VERSION 5.7 ;
  NOWIREEXTENSIONATPIN ON ;
  DIVIDERCHAR "/" ;
  BUSBITCHARS "[]" ;
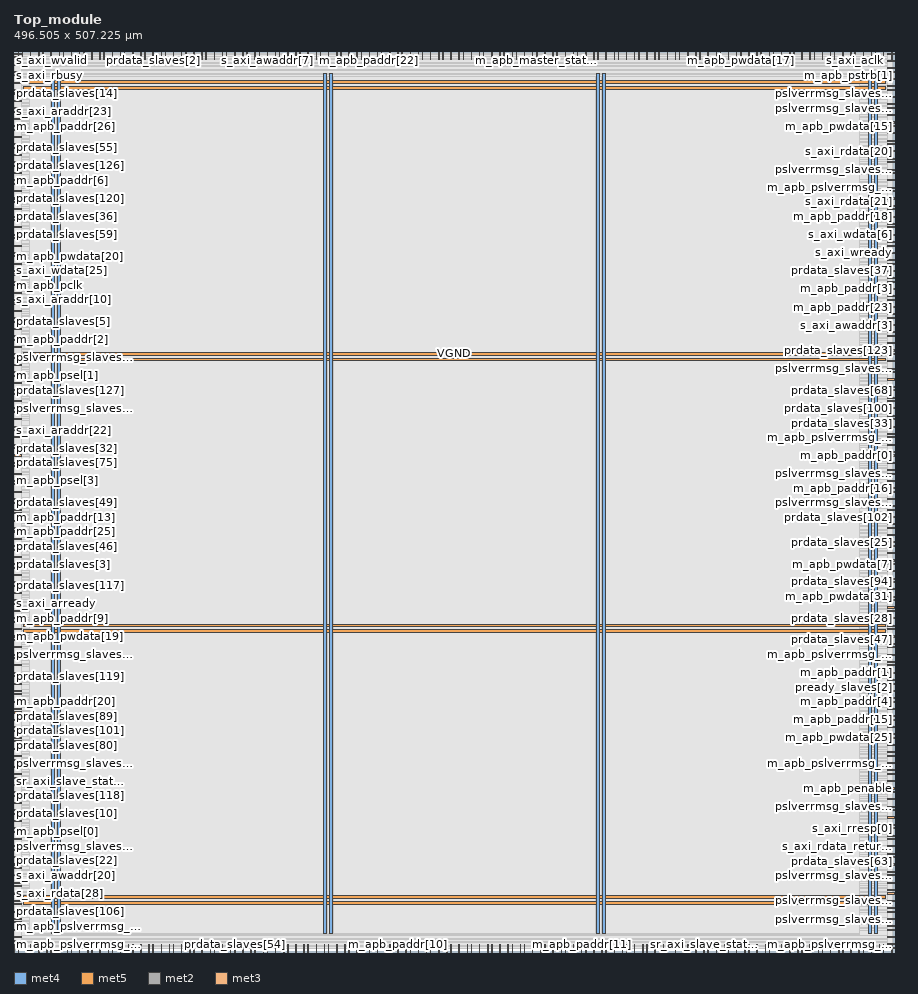
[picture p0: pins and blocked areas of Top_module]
MACRO Top_module
  CLASS BLOCK ;
  FOREIGN Top_module ;
  ORIGIN 0.000 0.000 ;
  SIZE 496.505 BY 507.225 ;
  PIN VGND
    DIRECTION INOUT ;
    USE GROUND ;
    PORT
      LAYER met4 ;
        RECT 24.340 10.640 25.940 495.280 ;
    END
    PORT
      LAYER met4 ;
        RECT 177.940 10.640 179.540 495.280 ;
    END
    PORT
      LAYER met4 ;
        RECT 331.540 10.640 333.140 495.280 ;
    END
    PORT
      LAYER met4 ;
        RECT 485.140 10.640 486.740 495.280 ;
    END
    PORT
      LAYER met5 ;
        RECT 5.280 30.030 491.060 31.630 ;
    END
    PORT
      LAYER met5 ;
        RECT 5.280 183.210 491.060 184.810 ;
    END
    PORT
      LAYER met5 ;
        RECT 5.280 336.390 491.060 337.990 ;
    END
    PORT
      LAYER met5 ;
        RECT 5.280 489.570 491.060 491.170 ;
    END
  END VGND
  PIN VPWR
    DIRECTION INOUT ;
    USE POWER ;
    PORT
      LAYER met4 ;
        RECT 21.040 10.640 22.640 495.280 ;
    END
    PORT
      LAYER met4 ;
        RECT 174.640 10.640 176.240 495.280 ;
    END
    PORT
      LAYER met4 ;
        RECT 328.240 10.640 329.840 495.280 ;
    END
    PORT
      LAYER met4 ;
        RECT 481.840 10.640 483.440 495.280 ;
    END
    PORT
      LAYER met5 ;
        RECT 5.280 26.730 491.060 28.330 ;
    END
    PORT
      LAYER met5 ;
        RECT 5.280 179.910 491.060 181.510 ;
    END
    PORT
      LAYER met5 ;
        RECT 5.280 333.090 491.060 334.690 ;
    END
    PORT
      LAYER met5 ;
        RECT 5.280 486.270 491.060 487.870 ;
    END
  END VPWR
  PIN apb_master_busy
    DIRECTION OUTPUT TRISTATE ;
    USE SIGNAL ;
    ANTENNADIFFAREA 0.795200 ;
    PORT
      LAYER met2 ;
        RECT 494.590 503.225 494.870 507.225 ;
    END
  END apb_master_busy
  PIN m_apb_master_state[0]
    DIRECTION OUTPUT TRISTATE ;
    USE SIGNAL ;
    ANTENNADIFFAREA 0.795200 ;
    PORT
      LAYER met2 ;
        RECT 494.590 0.000 494.870 4.000 ;
    END
  END m_apb_master_state[0]
  PIN m_apb_master_state[1]
    DIRECTION OUTPUT TRISTATE ;
    USE SIGNAL ;
    ANTENNADIFFAREA 0.795200 ;
    PORT
      LAYER met3 ;
        RECT 0.000 304.000 4.000 304.600 ;
    END
  END m_apb_master_state[1]
  PIN m_apb_master_state[2]
    DIRECTION OUTPUT TRISTATE ;
    USE SIGNAL ;
    ANTENNADIFFAREA 0.795200 ;
    PORT
      LAYER met2 ;
        RECT 294.490 503.225 294.770 507.225 ;
    END
  END m_apb_master_state[2]
  PIN m_apb_paddr[0]
    DIRECTION OUTPUT TRISTATE ;
    USE SIGNAL ;
    ANTENNADIFFAREA 0.445500 ;
    PORT
      LAYER met3 ;
        RECT 492.505 279.520 496.505 280.120 ;
    END
  END m_apb_paddr[0]
  PIN m_apb_paddr[10]
    DIRECTION OUTPUT TRISTATE ;
    USE SIGNAL ;
    ANTENNADIFFAREA 0.795200 ;
    PORT
      LAYER met2 ;
        RECT 216.290 0.000 216.570 4.000 ;
    END
  END m_apb_paddr[10]
  PIN m_apb_paddr[11]
    DIRECTION OUTPUT TRISTATE ;
    USE SIGNAL ;
    ANTENNADIFFAREA 0.795200 ;
    PORT
      LAYER met2 ;
        RECT 319.790 0.000 320.070 4.000 ;
    END
  END m_apb_paddr[11]
  PIN m_apb_paddr[12]
    DIRECTION OUTPUT TRISTATE ;
    USE SIGNAL ;
    ANTENNADIFFAREA 0.795200 ;
    PORT
      LAYER met3 ;
        RECT 492.505 75.520 496.505 76.120 ;
    END
  END m_apb_paddr[12]
  PIN m_apb_paddr[13]
    DIRECTION OUTPUT TRISTATE ;
    USE SIGNAL ;
    ANTENNADIFFAREA 0.795200 ;
    PORT
      LAYER met3 ;
        RECT 0.000 248.920 4.000 249.520 ;
    END
  END m_apb_paddr[13]
  PIN m_apb_paddr[14]
    DIRECTION OUTPUT TRISTATE ;
    USE SIGNAL ;
    ANTENNADIFFAREA 0.795200 ;
    PORT
      LAYER met3 ;
        RECT 0.000 126.520 4.000 127.120 ;
    END
  END m_apb_paddr[14]
  PIN m_apb_paddr[15]
    DIRECTION OUTPUT TRISTATE ;
    USE SIGNAL ;
    ANTENNADIFFAREA 0.795200 ;
    PORT
      LAYER met3 ;
        RECT 492.505 130.600 496.505 131.200 ;
    END
  END m_apb_paddr[15]
  PIN m_apb_paddr[16]
    DIRECTION OUTPUT TRISTATE ;
    USE SIGNAL ;
    ANTENNADIFFAREA 0.795200 ;
    PORT
      LAYER met3 ;
        RECT 492.505 261.160 496.505 261.760 ;
    END
  END m_apb_paddr[16]
  PIN m_apb_paddr[17]
    DIRECTION OUTPUT TRISTATE ;
    USE SIGNAL ;
    ANTENNADIFFAREA 0.795200 ;
    PORT
      LAYER met3 ;
        RECT 492.505 32.680 496.505 33.280 ;
    END
  END m_apb_paddr[17]
  PIN m_apb_paddr[18]
    DIRECTION OUTPUT TRISTATE ;
    USE SIGNAL ;
    ANTENNADIFFAREA 0.795200 ;
    PORT
      LAYER met3 ;
        RECT 492.505 414.160 496.505 414.760 ;
    END
  END m_apb_paddr[18]
  PIN m_apb_paddr[19]
    DIRECTION OUTPUT TRISTATE ;
    USE SIGNAL ;
    ANTENNADIFFAREA 0.795200 ;
    PORT
      LAYER met3 ;
        RECT 492.505 501.880 496.505 502.480 ;
    END
  END m_apb_paddr[19]
  PIN m_apb_paddr[1]
    DIRECTION OUTPUT TRISTATE ;
    USE SIGNAL ;
    ANTENNADIFFAREA 0.795200 ;
    PORT
      LAYER met3 ;
        RECT 492.505 157.120 496.505 157.720 ;
    END
  END m_apb_paddr[1]
  PIN m_apb_paddr[20]
    DIRECTION OUTPUT TRISTATE ;
    USE SIGNAL ;
    ANTENNADIFFAREA 0.795200 ;
    PORT
      LAYER met3 ;
        RECT 0.000 140.800 4.000 141.400 ;
    END
  END m_apb_paddr[20]
  PIN m_apb_paddr[21]
    DIRECTION OUTPUT TRISTATE ;
    USE SIGNAL ;
    ANTENNADIFFAREA 0.795200 ;
    PORT
      LAYER met2 ;
        RECT 211.690 0.000 211.970 4.000 ;
    END
  END m_apb_paddr[21]
  PIN m_apb_paddr[22]
    DIRECTION OUTPUT TRISTATE ;
    USE SIGNAL ;
    ANTENNADIFFAREA 0.795200 ;
    PORT
      LAYER met2 ;
        RECT 200.190 503.225 200.470 507.225 ;
    END
  END m_apb_paddr[22]
  PIN m_apb_paddr[23]
    DIRECTION OUTPUT TRISTATE ;
    USE SIGNAL ;
    ANTENNADIFFAREA 0.795200 ;
    PORT
      LAYER met3 ;
        RECT 492.505 363.160 496.505 363.760 ;
    END
  END m_apb_paddr[23]
  PIN m_apb_paddr[24]
    DIRECTION OUTPUT TRISTATE ;
    USE SIGNAL ;
    ANTENNADIFFAREA 0.795200 ;
    PORT
      LAYER met2 ;
        RECT 216.290 503.225 216.570 507.225 ;
    END
  END m_apb_paddr[24]
  PIN m_apb_paddr[25]
    DIRECTION OUTPUT TRISTATE ;
    USE SIGNAL ;
    ANTENNADIFFAREA 0.795200 ;
    PORT
      LAYER met3 ;
        RECT 0.000 236.680 4.000 237.280 ;
    END
  END m_apb_paddr[25]
  PIN m_apb_paddr[26]
    DIRECTION OUTPUT TRISTATE ;
    USE SIGNAL ;
    ANTENNADIFFAREA 0.795200 ;
    PORT
      LAYER met3 ;
        RECT 0.000 465.160 4.000 465.760 ;
    END
  END m_apb_paddr[26]
  PIN m_apb_paddr[27]
    DIRECTION OUTPUT TRISTATE ;
    USE SIGNAL ;
    ANTENNADIFFAREA 0.795200 ;
    PORT
      LAYER met2 ;
        RECT 361.190 503.225 361.470 507.225 ;
    END
  END m_apb_paddr[27]
  PIN m_apb_paddr[28]
    DIRECTION OUTPUT TRISTATE ;
    USE SIGNAL ;
    ANTENNADIFFAREA 0.795200 ;
    PORT
      LAYER met2 ;
        RECT 487.690 0.000 487.970 4.000 ;
    END
  END m_apb_paddr[28]
  PIN m_apb_paddr[29]
    DIRECTION OUTPUT TRISTATE ;
    USE SIGNAL ;
    ANTENNADIFFAREA 0.795200 ;
    PORT
      LAYER met2 ;
        RECT 349.690 503.225 349.970 507.225 ;
    END
  END m_apb_paddr[29]
  PIN m_apb_paddr[2]
    DIRECTION OUTPUT TRISTATE ;
    USE SIGNAL ;
    ANTENNADIFFAREA 0.795200 ;
    PORT
      LAYER met3 ;
        RECT 0.000 344.800 4.000 345.400 ;
    END
  END m_apb_paddr[2]
  PIN m_apb_paddr[30]
    DIRECTION OUTPUT TRISTATE ;
    USE SIGNAL ;
    ANTENNADIFFAREA 0.795200 ;
    PORT
      LAYER met3 ;
        RECT 492.505 34.720 496.505 35.320 ;
    END
  END m_apb_paddr[30]
  PIN m_apb_paddr[31]
    DIRECTION OUTPUT TRISTATE ;
    USE SIGNAL ;
    ANTENNADIFFAREA 0.795200 ;
    PORT
      LAYER met2 ;
        RECT 234.690 503.225 234.970 507.225 ;
    END
  END m_apb_paddr[31]
  PIN m_apb_paddr[3]
    DIRECTION OUTPUT TRISTATE ;
    USE SIGNAL ;
    ANTENNADIFFAREA 0.795200 ;
    PORT
      LAYER met3 ;
        RECT 492.505 373.360 496.505 373.960 ;
    END
  END m_apb_paddr[3]
  PIN m_apb_paddr[4]
    DIRECTION OUTPUT TRISTATE ;
    USE SIGNAL ;
    ANTENNADIFFAREA 0.445500 ;
    PORT
      LAYER met3 ;
        RECT 492.505 140.800 496.505 141.400 ;
    END
  END m_apb_paddr[4]
  PIN m_apb_paddr[5]
    DIRECTION OUTPUT TRISTATE ;
    USE SIGNAL ;
    ANTENNADIFFAREA 0.445500 ;
    PORT
      LAYER met3 ;
        RECT 492.505 197.920 496.505 198.520 ;
    END
  END m_apb_paddr[5]
  PIN m_apb_paddr[6]
    DIRECTION OUTPUT TRISTATE ;
    USE SIGNAL ;
    ANTENNADIFFAREA 0.795200 ;
    PORT
      LAYER met3 ;
        RECT 0.000 434.560 4.000 435.160 ;
    END
  END m_apb_paddr[6]
  PIN m_apb_paddr[7]
    DIRECTION OUTPUT TRISTATE ;
    USE SIGNAL ;
    ANTENNADIFFAREA 0.795200 ;
    PORT
      LAYER met3 ;
        RECT 0.000 263.200 4.000 263.800 ;
    END
  END m_apb_paddr[7]
  PIN m_apb_paddr[8]
    DIRECTION OUTPUT TRISTATE ;
    USE SIGNAL ;
    ANTENNADIFFAREA 0.445500 ;
    PORT
      LAYER met3 ;
        RECT 492.505 326.440 496.505 327.040 ;
    END
  END m_apb_paddr[8]
  PIN m_apb_paddr[9]
    DIRECTION OUTPUT TRISTATE ;
    USE SIGNAL ;
    ANTENNADIFFAREA 0.795200 ;
    PORT
      LAYER met3 ;
        RECT 0.000 187.720 4.000 188.320 ;
    END
  END m_apb_paddr[9]
  PIN m_apb_pclk
    DIRECTION INPUT ;
    USE SIGNAL ;
    ANTENNAGATEAREA 0.247500 ;
    PORT
      LAYER met3 ;
        RECT 0.000 375.400 4.000 376.000 ;
    END
  END m_apb_pclk
  PIN m_apb_penable
    DIRECTION OUTPUT TRISTATE ;
    USE SIGNAL ;
    ANTENNADIFFAREA 0.445500 ;
    PORT
      LAYER met3 ;
        RECT 492.505 91.840 496.505 92.440 ;
    END
  END m_apb_penable
  PIN m_apb_presetn
    DIRECTION INPUT ;
    USE SIGNAL ;
    ANTENNAGATEAREA 0.126000 ;
    PORT
      LAYER met2 ;
        RECT 142.690 0.000 142.970 4.000 ;
    END
  END m_apb_presetn
  PIN m_apb_psel[0]
    DIRECTION OUTPUT TRISTATE ;
    USE SIGNAL ;
    ANTENNADIFFAREA 0.795200 ;
    PORT
      LAYER met3 ;
        RECT 0.000 67.360 4.000 67.960 ;
    END
  END m_apb_psel[0]
  PIN m_apb_psel[1]
    DIRECTION OUTPUT TRISTATE ;
    USE SIGNAL ;
    ANTENNADIFFAREA 0.795200 ;
    PORT
      LAYER met3 ;
        RECT 0.000 320.320 4.000 320.920 ;
    END
  END m_apb_psel[1]
  PIN m_apb_psel[2]
    DIRECTION OUTPUT TRISTATE ;
    USE SIGNAL ;
    ANTENNADIFFAREA 0.795200 ;
    PORT
      LAYER met2 ;
        RECT 197.890 0.000 198.170 4.000 ;
    END
  END m_apb_psel[2]
  PIN m_apb_psel[3]
    DIRECTION OUTPUT TRISTATE ;
    USE SIGNAL ;
    ANTENNADIFFAREA 0.795200 ;
    PORT
      LAYER met3 ;
        RECT 0.000 265.240 4.000 265.840 ;
    END
  END m_apb_psel[3]
  PIN m_apb_pslverrmsg_mux[0]
    DIRECTION OUTPUT TRISTATE ;
    USE SIGNAL ;
    ANTENNADIFFAREA 0.795200 ;
    PORT
      LAYER met3 ;
        RECT 0.000 18.400 4.000 19.000 ;
    END
  END m_apb_pslverrmsg_mux[0]
  PIN m_apb_pslverrmsg_mux[10]
    DIRECTION OUTPUT TRISTATE ;
    USE SIGNAL ;
    PORT
      LAYER met2 ;
        RECT 170.290 503.225 170.570 507.225 ;
    END
  END m_apb_pslverrmsg_mux[10]
  PIN m_apb_pslverrmsg_mux[11]
    DIRECTION OUTPUT TRISTATE ;
    USE SIGNAL ;
    PORT
      LAYER met2 ;
        RECT 395.690 503.225 395.970 507.225 ;
    END
  END m_apb_pslverrmsg_mux[11]
  PIN m_apb_pslverrmsg_mux[12]
    DIRECTION OUTPUT TRISTATE ;
    USE SIGNAL ;
    PORT
      LAYER met3 ;
        RECT 492.505 163.240 496.505 163.840 ;
    END
  END m_apb_pslverrmsg_mux[12]
  PIN m_apb_pslverrmsg_mux[13]
    DIRECTION OUTPUT TRISTATE ;
    USE SIGNAL ;
    PORT
      LAYER met2 ;
        RECT 418.690 503.225 418.970 507.225 ;
    END
  END m_apb_pslverrmsg_mux[13]
  PIN m_apb_pslverrmsg_mux[14]
    DIRECTION OUTPUT TRISTATE ;
    USE SIGNAL ;
    PORT
      LAYER met2 ;
        RECT 117.390 503.225 117.670 507.225 ;
    END
  END m_apb_pslverrmsg_mux[14]
  PIN m_apb_pslverrmsg_mux[15]
    DIRECTION OUTPUT TRISTATE ;
    USE SIGNAL ;
    PORT
      LAYER met2 ;
        RECT 407.190 0.000 407.470 4.000 ;
    END
  END m_apb_pslverrmsg_mux[15]
  PIN m_apb_pslverrmsg_mux[16]
    DIRECTION OUTPUT TRISTATE ;
    USE SIGNAL ;
    PORT
      LAYER met3 ;
        RECT 492.505 289.720 496.505 290.320 ;
    END
  END m_apb_pslverrmsg_mux[16]
  PIN m_apb_pslverrmsg_mux[17]
    DIRECTION OUTPUT TRISTATE ;
    USE SIGNAL ;
    PORT
      LAYER met2 ;
        RECT 71.390 0.000 71.670 4.000 ;
    END
  END m_apb_pslverrmsg_mux[17]
  PIN m_apb_pslverrmsg_mux[18]
    DIRECTION OUTPUT TRISTATE ;
    USE SIGNAL ;
    PORT
      LAYER met2 ;
        RECT 27.690 503.225 27.970 507.225 ;
    END
  END m_apb_pslverrmsg_mux[18]
  PIN m_apb_pslverrmsg_mux[19]
    DIRECTION OUTPUT TRISTATE ;
    USE SIGNAL ;
    PORT
      LAYER met3 ;
        RECT 0.000 397.840 4.000 398.440 ;
    END
  END m_apb_pslverrmsg_mux[19]
  PIN m_apb_pslverrmsg_mux[1]
    DIRECTION OUTPUT TRISTATE ;
    USE SIGNAL ;
    PORT
      LAYER met3 ;
        RECT 492.505 403.960 496.505 404.560 ;
    END
  END m_apb_pslverrmsg_mux[1]
  PIN m_apb_pslverrmsg_mux[20]
    DIRECTION OUTPUT TRISTATE ;
    USE SIGNAL ;
    PORT
      LAYER met2 ;
        RECT 391.090 503.225 391.370 507.225 ;
    END
  END m_apb_pslverrmsg_mux[20]
  PIN m_apb_pslverrmsg_mux[21]
    DIRECTION OUTPUT TRISTATE ;
    USE SIGNAL ;
    PORT
      LAYER met3 ;
        RECT 492.505 281.560 496.505 282.160 ;
    END
  END m_apb_pslverrmsg_mux[21]
  PIN m_apb_pslverrmsg_mux[22]
    DIRECTION OUTPUT TRISTATE ;
    USE SIGNAL ;
    PORT
      LAYER met2 ;
        RECT 193.290 503.225 193.570 507.225 ;
    END
  END m_apb_pslverrmsg_mux[22]
  PIN m_apb_pslverrmsg_mux[23]
    DIRECTION OUTPUT TRISTATE ;
    USE SIGNAL ;
    PORT
      LAYER met3 ;
        RECT 492.505 106.120 496.505 106.720 ;
    END
  END m_apb_pslverrmsg_mux[23]
  PIN m_apb_pslverrmsg_mux[24]
    DIRECTION OUTPUT TRISTATE ;
    USE SIGNAL ;
    PORT
      LAYER met2 ;
        RECT 466.990 0.000 467.270 4.000 ;
    END
  END m_apb_pslverrmsg_mux[24]
  PIN m_apb_pslverrmsg_mux[25]
    DIRECTION OUTPUT TRISTATE ;
    USE SIGNAL ;
    PORT
      LAYER met2 ;
        RECT 64.490 0.000 64.770 4.000 ;
    END
  END m_apb_pslverrmsg_mux[25]
  PIN m_apb_pslverrmsg_mux[26]
    DIRECTION OUTPUT TRISTATE ;
    USE SIGNAL ;
    PORT
      LAYER met2 ;
        RECT 13.890 0.000 14.170 4.000 ;
    END
  END m_apb_pslverrmsg_mux[26]
  PIN m_apb_pslverrmsg_mux[27]
    DIRECTION OUTPUT TRISTATE ;
    USE SIGNAL ;
    PORT
      LAYER met2 ;
        RECT 200.190 0.000 200.470 4.000 ;
    END
  END m_apb_pslverrmsg_mux[27]
  PIN m_apb_pslverrmsg_mux[28]
    DIRECTION OUTPUT TRISTATE ;
    USE SIGNAL ;
    PORT
      LAYER met2 ;
        RECT 282.990 503.225 283.270 507.225 ;
    END
  END m_apb_pslverrmsg_mux[28]
  PIN m_apb_pslverrmsg_mux[29]
    DIRECTION OUTPUT TRISTATE ;
    USE SIGNAL ;
    PORT
      LAYER met3 ;
        RECT 492.505 430.480 496.505 431.080 ;
    END
  END m_apb_pslverrmsg_mux[29]
  PIN m_apb_pslverrmsg_mux[2]
    DIRECTION OUTPUT TRISTATE ;
    USE SIGNAL ;
    PORT
      LAYER met2 ;
        RECT 253.090 503.225 253.370 507.225 ;
    END
  END m_apb_pslverrmsg_mux[2]
  PIN m_apb_pslverrmsg_mux[30]
    DIRECTION OUTPUT TRISTATE ;
    USE SIGNAL ;
    PORT
      LAYER met2 ;
        RECT 149.590 503.225 149.870 507.225 ;
    END
  END m_apb_pslverrmsg_mux[30]
  PIN m_apb_pslverrmsg_mux[31]
    DIRECTION OUTPUT TRISTATE ;
    USE SIGNAL ;
    PORT
      LAYER met2 ;
        RECT 455.490 0.000 455.770 4.000 ;
    END
  END m_apb_pslverrmsg_mux[31]
  PIN m_apb_pslverrmsg_mux[3]
    DIRECTION OUTPUT TRISTATE ;
    USE SIGNAL ;
    PORT
      LAYER met3 ;
        RECT 492.505 367.240 496.505 367.840 ;
    END
  END m_apb_pslverrmsg_mux[3]
  PIN m_apb_pslverrmsg_mux[4]
    DIRECTION OUTPUT TRISTATE ;
    USE SIGNAL ;
    PORT
      LAYER met3 ;
        RECT 492.505 8.200 496.505 8.800 ;
    END
  END m_apb_pslverrmsg_mux[4]
  PIN m_apb_pslverrmsg_mux[5]
    DIRECTION OUTPUT TRISTATE ;
    USE SIGNAL ;
    PORT
      LAYER met3 ;
        RECT 492.505 387.640 496.505 388.240 ;
    END
  END m_apb_pslverrmsg_mux[5]
  PIN m_apb_pslverrmsg_mux[6]
    DIRECTION OUTPUT TRISTATE ;
    USE SIGNAL ;
    PORT
      LAYER met3 ;
        RECT 0.000 346.840 4.000 347.440 ;
    END
  END m_apb_pslverrmsg_mux[6]
  PIN m_apb_pslverrmsg_mux[7]
    DIRECTION OUTPUT TRISTATE ;
    USE SIGNAL ;
    PORT
      LAYER met2 ;
        RECT 273.790 503.225 274.070 507.225 ;
    END
  END m_apb_pslverrmsg_mux[7]
  PIN m_apb_pslverrmsg_mux[8]
    DIRECTION OUTPUT TRISTATE ;
    USE SIGNAL ;
    PORT
      LAYER met3 ;
        RECT 492.505 24.520 496.505 25.120 ;
    END
  END m_apb_pslverrmsg_mux[8]
  PIN m_apb_pslverrmsg_mux[9]
    DIRECTION OUTPUT TRISTATE ;
    USE SIGNAL ;
    PORT
      LAYER met2 ;
        RECT 105.890 503.225 106.170 507.225 ;
    END
  END m_apb_pslverrmsg_mux[9]
  PIN m_apb_pstrb[0]
    DIRECTION OUTPUT TRISTATE ;
    USE SIGNAL ;
    ANTENNADIFFAREA 0.795200 ;
    PORT
      LAYER met3 ;
        RECT 0.000 355.000 4.000 355.600 ;
    END
  END m_apb_pstrb[0]
  PIN m_apb_pstrb[1]
    DIRECTION OUTPUT TRISTATE ;
    USE SIGNAL ;
    ANTENNADIFFAREA 0.795200 ;
    PORT
      LAYER met3 ;
        RECT 492.505 497.800 496.505 498.400 ;
    END
  END m_apb_pstrb[1]
  PIN m_apb_pstrb[2]
    DIRECTION OUTPUT TRISTATE ;
    USE SIGNAL ;
    ANTENNADIFFAREA 0.795200 ;
    PORT
      LAYER met2 ;
        RECT 345.090 0.000 345.370 4.000 ;
    END
  END m_apb_pstrb[2]
  PIN m_apb_pstrb[3]
    DIRECTION OUTPUT TRISTATE ;
    USE SIGNAL ;
    ANTENNADIFFAREA 0.795200 ;
    PORT
      LAYER met2 ;
        RECT 285.290 0.000 285.570 4.000 ;
    END
  END m_apb_pstrb[3]
  PIN m_apb_pwdata[0]
    DIRECTION OUTPUT TRISTATE ;
    USE SIGNAL ;
    ANTENNADIFFAREA 0.445500 ;
    PORT
      LAYER met3 ;
        RECT 492.505 424.360 496.505 424.960 ;
    END
  END m_apb_pwdata[0]
  PIN m_apb_pwdata[10]
    DIRECTION OUTPUT TRISTATE ;
    USE SIGNAL ;
    ANTENNADIFFAREA 0.795200 ;
    PORT
      LAYER met2 ;
        RECT 287.590 0.000 287.870 4.000 ;
    END
  END m_apb_pwdata[10]
  PIN m_apb_pwdata[11]
    DIRECTION OUTPUT TRISTATE ;
    USE SIGNAL ;
    ANTENNADIFFAREA 0.795200 ;
    PORT
      LAYER met3 ;
        RECT 492.505 428.440 496.505 429.040 ;
    END
  END m_apb_pwdata[11]
  PIN m_apb_pwdata[12]
    DIRECTION OUTPUT TRISTATE ;
    USE SIGNAL ;
    ANTENNADIFFAREA 0.795200 ;
    PORT
      LAYER met2 ;
        RECT 119.690 503.225 119.970 507.225 ;
    END
  END m_apb_pwdata[12]
  PIN m_apb_pwdata[13]
    DIRECTION OUTPUT TRISTATE ;
    USE SIGNAL ;
    ANTENNADIFFAREA 0.795200 ;
    PORT
      LAYER met3 ;
        RECT 492.505 295.840 496.505 296.440 ;
    END
  END m_apb_pwdata[13]
  PIN m_apb_pwdata[14]
    DIRECTION OUTPUT TRISTATE ;
    USE SIGNAL ;
    ANTENNADIFFAREA 0.795200 ;
    PORT
      LAYER met3 ;
        RECT 0.000 495.760 4.000 496.360 ;
    END
  END m_apb_pwdata[14]
  PIN m_apb_pwdata[15]
    DIRECTION OUTPUT TRISTATE ;
    USE SIGNAL ;
    ANTENNADIFFAREA 0.445500 ;
    PORT
      LAYER met3 ;
        RECT 492.505 465.160 496.505 465.760 ;
    END
  END m_apb_pwdata[15]
  PIN m_apb_pwdata[16]
    DIRECTION OUTPUT TRISTATE ;
    USE SIGNAL ;
    ANTENNADIFFAREA 0.795200 ;
    PORT
      LAYER met3 ;
        RECT 492.505 310.120 496.505 310.720 ;
    END
  END m_apb_pwdata[16]
  PIN m_apb_pwdata[17]
    DIRECTION OUTPUT TRISTATE ;
    USE SIGNAL ;
    ANTENNADIFFAREA 0.795200 ;
    PORT
      LAYER met2 ;
        RECT 409.490 503.225 409.770 507.225 ;
    END
  END m_apb_pwdata[17]
  PIN m_apb_pwdata[18]
    DIRECTION OUTPUT TRISTATE ;
    USE SIGNAL ;
    ANTENNADIFFAREA 0.795200 ;
    PORT
      LAYER met3 ;
        RECT 0.000 146.920 4.000 147.520 ;
    END
  END m_apb_pwdata[18]
  PIN m_apb_pwdata[19]
    DIRECTION OUTPUT TRISTATE ;
    USE SIGNAL ;
    ANTENNADIFFAREA 0.795200 ;
    PORT
      LAYER met3 ;
        RECT 0.000 177.520 4.000 178.120 ;
    END
  END m_apb_pwdata[19]
  PIN m_apb_pwdata[1]
    DIRECTION OUTPUT TRISTATE ;
    USE SIGNAL ;
    ANTENNADIFFAREA 0.795200 ;
    PORT
      LAYER met3 ;
        RECT 0.000 12.280 4.000 12.880 ;
    END
  END m_apb_pwdata[1]
  PIN m_apb_pwdata[20]
    DIRECTION OUTPUT TRISTATE ;
    USE SIGNAL ;
    ANTENNADIFFAREA 0.795200 ;
    PORT
      LAYER met3 ;
        RECT 0.000 391.720 4.000 392.320 ;
    END
  END m_apb_pwdata[20]
  PIN m_apb_pwdata[21]
    DIRECTION OUTPUT TRISTATE ;
    USE SIGNAL ;
    ANTENNADIFFAREA 0.795200 ;
    PORT
      LAYER met3 ;
        RECT 0.000 79.600 4.000 80.200 ;
    END
  END m_apb_pwdata[21]
  PIN m_apb_pwdata[22]
    DIRECTION OUTPUT TRISTATE ;
    USE SIGNAL ;
    ANTENNADIFFAREA 0.795200 ;
    PORT
      LAYER met3 ;
        RECT 0.000 326.440 4.000 327.040 ;
    END
  END m_apb_pwdata[22]
  PIN m_apb_pwdata[23]
    DIRECTION OUTPUT TRISTATE ;
    USE SIGNAL ;
    ANTENNADIFFAREA 0.795200 ;
    PORT
      LAYER met3 ;
        RECT 0.000 185.680 4.000 186.280 ;
    END
  END m_apb_pwdata[23]
  PIN m_apb_pwdata[24]
    DIRECTION OUTPUT TRISTATE ;
    USE SIGNAL ;
    ANTENNADIFFAREA 0.795200 ;
    PORT
      LAYER met3 ;
        RECT 492.505 454.960 496.505 455.560 ;
    END
  END m_apb_pwdata[24]
  PIN m_apb_pwdata[25]
    DIRECTION OUTPUT TRISTATE ;
    USE SIGNAL ;
    ANTENNADIFFAREA 0.795200 ;
    PORT
      LAYER met3 ;
        RECT 492.505 120.400 496.505 121.000 ;
    END
  END m_apb_pwdata[25]
  PIN m_apb_pwdata[26]
    DIRECTION OUTPUT TRISTATE ;
    USE SIGNAL ;
    ANTENNADIFFAREA 0.795200 ;
    PORT
      LAYER met2 ;
        RECT 462.390 503.225 462.670 507.225 ;
    END
  END m_apb_pwdata[26]
  PIN m_apb_pwdata[27]
    DIRECTION OUTPUT TRISTATE ;
    USE SIGNAL ;
    ANTENNADIFFAREA 0.795200 ;
    PORT
      LAYER met3 ;
        RECT 0.000 63.280 4.000 63.880 ;
    END
  END m_apb_pwdata[27]
  PIN m_apb_pwdata[28]
    DIRECTION OUTPUT TRISTATE ;
    USE SIGNAL ;
    ANTENNADIFFAREA 0.795200 ;
    PORT
      LAYER met2 ;
        RECT 437.090 503.225 437.370 507.225 ;
    END
  END m_apb_pwdata[28]
  PIN m_apb_pwdata[29]
    DIRECTION OUTPUT TRISTATE ;
    USE SIGNAL ;
    ANTENNADIFFAREA 0.795200 ;
    PORT
      LAYER met2 ;
        RECT 280.690 503.225 280.970 507.225 ;
    END
  END m_apb_pwdata[29]
  PIN m_apb_pwdata[2]
    DIRECTION OUTPUT TRISTATE ;
    USE SIGNAL ;
    ANTENNADIFFAREA 0.795200 ;
    PORT
      LAYER met2 ;
        RECT 489.990 503.225 490.270 507.225 ;
    END
  END m_apb_pwdata[2]
  PIN m_apb_pwdata[30]
    DIRECTION OUTPUT TRISTATE ;
    USE SIGNAL ;
    ANTENNADIFFAREA 0.795200 ;
    PORT
      LAYER met2 ;
        RECT 246.190 0.000 246.470 4.000 ;
    END
  END m_apb_pwdata[30]
  PIN m_apb_pwdata[31]
    DIRECTION OUTPUT TRISTATE ;
    USE SIGNAL ;
    ANTENNADIFFAREA 0.795200 ;
    PORT
      LAYER met3 ;
        RECT 492.505 199.960 496.505 200.560 ;
    END
  END m_apb_pwdata[31]
  PIN m_apb_pwdata[3]
    DIRECTION OUTPUT TRISTATE ;
    USE SIGNAL ;
    ANTENNADIFFAREA 0.795200 ;
    PORT
      LAYER met2 ;
        RECT 402.590 503.225 402.870 507.225 ;
    END
  END m_apb_pwdata[3]
  PIN m_apb_pwdata[4]
    DIRECTION OUTPUT TRISTATE ;
    USE SIGNAL ;
    ANTENNADIFFAREA 0.795200 ;
    PORT
      LAYER met2 ;
        RECT 193.290 0.000 193.570 4.000 ;
    END
  END m_apb_pwdata[4]
  PIN m_apb_pwdata[5]
    DIRECTION OUTPUT TRISTATE ;
    USE SIGNAL ;
    ANTENNADIFFAREA 0.795200 ;
    PORT
      LAYER met2 ;
        RECT 432.490 0.000 432.770 4.000 ;
    END
  END m_apb_pwdata[5]
  PIN m_apb_pwdata[6]
    DIRECTION OUTPUT TRISTATE ;
    USE SIGNAL ;
    ANTENNADIFFAREA 0.795200 ;
    PORT
      LAYER met2 ;
        RECT 400.290 0.000 400.570 4.000 ;
    END
  END m_apb_pwdata[6]
  PIN m_apb_pwdata[7]
    DIRECTION OUTPUT TRISTATE ;
    USE SIGNAL ;
    ANTENNADIFFAREA 0.445500 ;
    PORT
      LAYER met3 ;
        RECT 492.505 218.320 496.505 218.920 ;
    END
  END m_apb_pwdata[7]
  PIN m_apb_pwdata[8]
    DIRECTION OUTPUT TRISTATE ;
    USE SIGNAL ;
    ANTENNADIFFAREA 0.795200 ;
    PORT
      LAYER met2 ;
        RECT 443.990 0.000 444.270 4.000 ;
    END
  END m_apb_pwdata[8]
  PIN m_apb_pwdata[9]
    DIRECTION OUTPUT TRISTATE ;
    USE SIGNAL ;
    ANTENNADIFFAREA 0.795200 ;
    PORT
      LAYER met2 ;
        RECT 379.590 503.225 379.870 507.225 ;
    END
  END m_apb_pwdata[9]
  PIN m_apb_pwrite
    DIRECTION OUTPUT TRISTATE ;
    USE SIGNAL ;
    ANTENNADIFFAREA 0.795200 ;
    PORT
      LAYER met2 ;
        RECT 105.890 0.000 106.170 4.000 ;
    END
  END m_apb_pwrite
  PIN prdata_slaves[0]
    DIRECTION INPUT ;
    USE SIGNAL ;
    ANTENNAGATEAREA 0.213000 ;
    PORT
      LAYER met2 ;
        RECT 110.490 0.000 110.770 4.000 ;
    END
  END prdata_slaves[0]
  PIN prdata_slaves[100]
    DIRECTION INPUT ;
    USE SIGNAL ;
    ANTENNAGATEAREA 0.196500 ;
    PORT
      LAYER met3 ;
        RECT 492.505 306.040 496.505 306.640 ;
    END
  END prdata_slaves[100]
  PIN prdata_slaves[101]
    DIRECTION INPUT ;
    USE SIGNAL ;
    ANTENNAGATEAREA 0.159000 ;
    PORT
      LAYER met3 ;
        RECT 0.000 124.480 4.000 125.080 ;
    END
  END prdata_slaves[101]
  PIN prdata_slaves[102]
    DIRECTION INPUT ;
    USE SIGNAL ;
    ANTENNAGATEAREA 0.213000 ;
    PORT
      LAYER met3 ;
        RECT 492.505 244.840 496.505 245.440 ;
    END
  END prdata_slaves[102]
  PIN prdata_slaves[103]
    DIRECTION INPUT ;
    USE SIGNAL ;
    ANTENNAGATEAREA 0.159000 ;
    PORT
      LAYER met2 ;
        RECT 36.890 0.000 37.170 4.000 ;
    END
  END prdata_slaves[103]
  PIN prdata_slaves[104]
    DIRECTION INPUT ;
    USE SIGNAL ;
    ANTENNAGATEAREA 0.159000 ;
    PORT
      LAYER met2 ;
        RECT 489.990 0.000 490.270 4.000 ;
    END
  END prdata_slaves[104]
  PIN prdata_slaves[105]
    DIRECTION INPUT ;
    USE SIGNAL ;
    ANTENNAGATEAREA 0.196500 ;
    PORT
      LAYER met3 ;
        RECT 492.505 318.280 496.505 318.880 ;
    END
  END prdata_slaves[105]
  PIN prdata_slaves[106]
    DIRECTION INPUT ;
    USE SIGNAL ;
    ANTENNAGATEAREA 0.159000 ;
    PORT
      LAYER met3 ;
        RECT 0.000 22.480 4.000 23.080 ;
    END
  END prdata_slaves[106]
  PIN prdata_slaves[107]
    DIRECTION INPUT ;
    USE SIGNAL ;
    ANTENNAGATEAREA 0.213000 ;
    PORT
      LAYER met2 ;
        RECT 439.390 503.225 439.670 507.225 ;
    END
  END prdata_slaves[107]
  PIN prdata_slaves[108]
    DIRECTION INPUT ;
    USE SIGNAL ;
    ANTENNAGATEAREA 0.213000 ;
    PORT
      LAYER met2 ;
        RECT 230.090 503.225 230.370 507.225 ;
    END
  END prdata_slaves[108]
  PIN prdata_slaves[109]
    DIRECTION INPUT ;
    USE SIGNAL ;
    ANTENNAGATEAREA 0.196500 ;
    PORT
      LAYER met2 ;
        RECT 340.490 503.225 340.770 507.225 ;
    END
  END prdata_slaves[109]
  PIN prdata_slaves[10]
    DIRECTION INPUT ;
    USE SIGNAL ;
    ANTENNAGATEAREA 0.213000 ;
    PORT
      LAYER met3 ;
        RECT 0.000 77.560 4.000 78.160 ;
    END
  END prdata_slaves[10]
  PIN prdata_slaves[110]
    DIRECTION INPUT ;
    USE SIGNAL ;
    ANTENNAGATEAREA 0.247500 ;
    PORT
      LAYER met2 ;
        RECT 308.290 0.000 308.570 4.000 ;
    END
  END prdata_slaves[110]
  PIN prdata_slaves[111]
    DIRECTION INPUT ;
    USE SIGNAL ;
    ANTENNAGATEAREA 0.159000 ;
    PORT
      LAYER met2 ;
        RECT 32.290 503.225 32.570 507.225 ;
    END
  END prdata_slaves[111]
  PIN prdata_slaves[112]
    DIRECTION INPUT ;
    USE SIGNAL ;
    ANTENNAGATEAREA 0.159000 ;
    PORT
      LAYER met2 ;
        RECT 384.190 503.225 384.470 507.225 ;
    END
  END prdata_slaves[112]
  PIN prdata_slaves[113]
    DIRECTION INPUT ;
    USE SIGNAL ;
    ANTENNAGATEAREA 0.213000 ;
    PORT
      LAYER met2 ;
        RECT 2.390 503.225 2.670 507.225 ;
    END
  END prdata_slaves[113]
  PIN prdata_slaves[114]
    DIRECTION INPUT ;
    USE SIGNAL ;
    ANTENNAGATEAREA 0.213000 ;
    PORT
      LAYER met2 ;
        RECT 287.590 503.225 287.870 507.225 ;
    END
  END prdata_slaves[114]
  PIN prdata_slaves[115]
    DIRECTION INPUT ;
    USE SIGNAL ;
    ANTENNAGATEAREA 0.159000 ;
    PORT
      LAYER met2 ;
        RECT 243.890 0.000 244.170 4.000 ;
    END
  END prdata_slaves[115]
  PIN prdata_slaves[116]
    DIRECTION INPUT ;
    USE SIGNAL ;
    ANTENNAGATEAREA 0.159000 ;
    PORT
      LAYER met3 ;
        RECT 0.000 463.120 4.000 463.720 ;
    END
  END prdata_slaves[116]
  PIN prdata_slaves[117]
    DIRECTION INPUT ;
    USE SIGNAL ;
    ANTENNAGATEAREA 0.159000 ;
    PORT
      LAYER met3 ;
        RECT 0.000 206.080 4.000 206.680 ;
    END
  END prdata_slaves[117]
  PIN prdata_slaves[118]
    DIRECTION INPUT ;
    USE SIGNAL ;
    ANTENNAGATEAREA 0.213000 ;
    PORT
      LAYER met3 ;
        RECT 0.000 87.760 4.000 88.360 ;
    END
  END prdata_slaves[118]
  PIN prdata_slaves[119]
    DIRECTION INPUT ;
    USE SIGNAL ;
    ANTENNAGATEAREA 0.126000 ;
    PORT
      LAYER met3 ;
        RECT 0.000 155.080 4.000 155.680 ;
    END
  END prdata_slaves[119]
  PIN prdata_slaves[11]
    DIRECTION INPUT ;
    USE SIGNAL ;
    ANTENNAGATEAREA 0.196500 ;
    PORT
      LAYER met2 ;
        RECT 16.190 503.225 16.470 507.225 ;
    END
  END prdata_slaves[11]
  PIN prdata_slaves[120]
    DIRECTION INPUT ;
    USE SIGNAL ;
    ANTENNAGATEAREA 0.126000 ;
    PORT
      LAYER met3 ;
        RECT 0.000 424.360 4.000 424.960 ;
    END
  END prdata_slaves[120]
  PIN prdata_slaves[121]
    DIRECTION INPUT ;
    USE SIGNAL ;
    ANTENNAGATEAREA 0.159000 ;
    PORT
      LAYER met2 ;
        RECT 338.190 0.000 338.470 4.000 ;
    END
  END prdata_slaves[121]
  PIN prdata_slaves[122]
    DIRECTION INPUT ;
    USE SIGNAL ;
    ANTENNAGATEAREA 0.196500 ;
    PORT
      LAYER met2 ;
        RECT 322.090 503.225 322.370 507.225 ;
    END
  END prdata_slaves[122]
  PIN prdata_slaves[123]
    DIRECTION INPUT ;
    USE SIGNAL ;
    ANTENNAGATEAREA 0.213000 ;
    PORT
      LAYER met3 ;
        RECT 492.505 338.680 496.505 339.280 ;
    END
  END prdata_slaves[123]
  PIN prdata_slaves[124]
    DIRECTION INPUT ;
    USE SIGNAL ;
    ANTENNAGATEAREA 0.213000 ;
    PORT
      LAYER met2 ;
        RECT 255.390 0.000 255.670 4.000 ;
    END
  END prdata_slaves[124]
  PIN prdata_slaves[125]
    DIRECTION INPUT ;
    USE SIGNAL ;
    ANTENNAGATEAREA 0.159000 ;
    PORT
      LAYER met3 ;
        RECT 492.505 477.400 496.505 478.000 ;
    END
  END prdata_slaves[125]
  PIN prdata_slaves[126]
    DIRECTION INPUT ;
    USE SIGNAL ;
    ANTENNAGATEAREA 0.159000 ;
    PORT
      LAYER met3 ;
        RECT 0.000 442.720 4.000 443.320 ;
    END
  END prdata_slaves[126]
  PIN prdata_slaves[127]
    DIRECTION INPUT ;
    USE SIGNAL ;
    ANTENNAGATEAREA 0.213000 ;
    PORT
      LAYER met3 ;
        RECT 0.000 316.240 4.000 316.840 ;
    END
  END prdata_slaves[127]
  PIN prdata_slaves[12]
    DIRECTION INPUT ;
    USE SIGNAL ;
    ANTENNAGATEAREA 0.159000 ;
    PORT
      LAYER met3 ;
        RECT 0.000 134.680 4.000 135.280 ;
    END
  END prdata_slaves[12]
  PIN prdata_slaves[13]
    DIRECTION INPUT ;
    USE SIGNAL ;
    ANTENNAGATEAREA 0.196500 ;
    PORT
      LAYER met2 ;
        RECT 386.490 503.225 386.770 507.225 ;
    END
  END prdata_slaves[13]
  PIN prdata_slaves[14]
    DIRECTION INPUT ;
    USE SIGNAL ;
    ANTENNAGATEAREA 0.196500 ;
    PORT
      LAYER met3 ;
        RECT 0.000 479.440 4.000 480.040 ;
    END
  END prdata_slaves[14]
  PIN prdata_slaves[15]
    DIRECTION INPUT ;
    USE SIGNAL ;
    ANTENNAGATEAREA 0.196500 ;
    PORT
      LAYER met2 ;
        RECT 241.590 503.225 241.870 507.225 ;
    END
  END prdata_slaves[15]
  PIN prdata_slaves[16]
    DIRECTION INPUT ;
    USE SIGNAL ;
    ANTENNAGATEAREA 0.196500 ;
    PORT
      LAYER met2 ;
        RECT 218.590 503.225 218.870 507.225 ;
    END
  END prdata_slaves[16]
  PIN prdata_slaves[17]
    DIRECTION INPUT ;
    USE SIGNAL ;
    ANTENNAGATEAREA 0.213000 ;
    PORT
      LAYER met2 ;
        RECT 55.290 0.000 55.570 4.000 ;
    END
  END prdata_slaves[17]
  PIN prdata_slaves[18]
    DIRECTION INPUT ;
    USE SIGNAL ;
    ANTENNAGATEAREA 0.159000 ;
    PORT
      LAYER met2 ;
        RECT 209.390 0.000 209.670 4.000 ;
    END
  END prdata_slaves[18]
  PIN prdata_slaves[19]
    DIRECTION INPUT ;
    USE SIGNAL ;
    ANTENNAGATEAREA 0.247500 ;
    PORT
      LAYER met2 ;
        RECT 2.390 0.000 2.670 4.000 ;
    END
  END prdata_slaves[19]
  PIN prdata_slaves[1]
    DIRECTION INPUT ;
    USE SIGNAL ;
    ANTENNAGATEAREA 0.196500 ;
    PORT
      LAYER met3 ;
        RECT 492.505 369.280 496.505 369.880 ;
    END
  END prdata_slaves[1]
  PIN prdata_slaves[20]
    DIRECTION INPUT ;
    USE SIGNAL ;
    ANTENNAGATEAREA 0.213000 ;
    PORT
      LAYER met2 ;
        RECT 349.690 0.000 349.970 4.000 ;
    END
  END prdata_slaves[20]
  PIN prdata_slaves[21]
    DIRECTION INPUT ;
    USE SIGNAL ;
    ANTENNAGATEAREA 0.213000 ;
    PORT
      LAYER met2 ;
        RECT 50.690 503.225 50.970 507.225 ;
    END
  END prdata_slaves[21]
  PIN prdata_slaves[22]
    DIRECTION INPUT ;
    USE SIGNAL ;
    ANTENNAGATEAREA 0.213000 ;
    PORT
      LAYER met3 ;
        RECT 0.000 46.960 4.000 47.560 ;
    END
  END prdata_slaves[22]
  PIN prdata_slaves[23]
    DIRECTION INPUT ;
    USE SIGNAL ;
    ANTENNAGATEAREA 0.159000 ;
    PORT
      LAYER met3 ;
        RECT 492.505 126.520 496.505 127.120 ;
    END
  END prdata_slaves[23]
  PIN prdata_slaves[24]
    DIRECTION INPUT ;
    USE SIGNAL ;
    ANTENNAGATEAREA 0.213000 ;
    PORT
      LAYER met2 ;
        RECT 62.190 503.225 62.470 507.225 ;
    END
  END prdata_slaves[24]
  PIN prdata_slaves[25]
    DIRECTION INPUT ;
    USE SIGNAL ;
    ANTENNAGATEAREA 0.213000 ;
    PORT
      LAYER met3 ;
        RECT 492.505 230.560 496.505 231.160 ;
    END
  END prdata_slaves[25]
  PIN prdata_slaves[26]
    DIRECTION INPUT ;
    USE SIGNAL ;
    ANTENNAGATEAREA 0.196500 ;
    PORT
      LAYER met2 ;
        RECT 397.990 503.225 398.270 507.225 ;
    END
  END prdata_slaves[26]
  PIN prdata_slaves[27]
    DIRECTION INPUT ;
    USE SIGNAL ;
    ANTENNAGATEAREA 0.213000 ;
    PORT
      LAYER met2 ;
        RECT 9.290 503.225 9.570 507.225 ;
    END
  END prdata_slaves[27]
  PIN prdata_slaves[28]
    DIRECTION INPUT ;
    USE SIGNAL ;
    ANTENNAGATEAREA 0.213000 ;
    PORT
      LAYER met3 ;
        RECT 492.505 187.720 496.505 188.320 ;
    END
  END prdata_slaves[28]
  PIN prdata_slaves[29]
    DIRECTION INPUT ;
    USE SIGNAL ;
    ANTENNAGATEAREA 0.196500 ;
    PORT
      LAYER met2 ;
        RECT 239.290 503.225 239.570 507.225 ;
    END
  END prdata_slaves[29]
  PIN prdata_slaves[2]
    DIRECTION INPUT ;
    USE SIGNAL ;
    ANTENNAGATEAREA 0.213000 ;
    PORT
      LAYER met2 ;
        RECT 78.290 503.225 78.570 507.225 ;
    END
  END prdata_slaves[2]
  PIN prdata_slaves[30]
    DIRECTION INPUT ;
    USE SIGNAL ;
    ANTENNAGATEAREA 0.213000 ;
    PORT
      LAYER met2 ;
        RECT 427.890 503.225 428.170 507.225 ;
    END
  END prdata_slaves[30]
  PIN prdata_slaves[31]
    DIRECTION INPUT ;
    USE SIGNAL ;
    ANTENNAGATEAREA 0.159000 ;
    PORT
      LAYER met2 ;
        RECT 112.790 503.225 113.070 507.225 ;
    END
  END prdata_slaves[31]
  PIN prdata_slaves[32]
    DIRECTION INPUT ;
    USE SIGNAL ;
    ANTENNAGATEAREA 0.213000 ;
    PORT
      LAYER met3 ;
        RECT 0.000 283.600 4.000 284.200 ;
    END
  END prdata_slaves[32]
  PIN prdata_slaves[33]
    DIRECTION INPUT ;
    USE SIGNAL ;
    ANTENNAGATEAREA 0.196500 ;
    PORT
      LAYER met3 ;
        RECT 492.505 301.960 496.505 302.560 ;
    END
  END prdata_slaves[33]
  PIN prdata_slaves[34]
    DIRECTION INPUT ;
    USE SIGNAL ;
    ANTENNAGATEAREA 0.159000 ;
    PORT
      LAYER met3 ;
        RECT 492.505 38.800 496.505 39.400 ;
    END
  END prdata_slaves[34]
  PIN prdata_slaves[35]
    DIRECTION INPUT ;
    USE SIGNAL ;
    ANTENNAGATEAREA 0.126000 ;
    PORT
      LAYER met2 ;
        RECT 71.390 503.225 71.670 507.225 ;
    END
  END prdata_slaves[35]
  PIN prdata_slaves[36]
    DIRECTION INPUT ;
    USE SIGNAL ;
    ANTENNAGATEAREA 0.213000 ;
    PORT
      LAYER met3 ;
        RECT 0.000 414.160 4.000 414.760 ;
    END
  END prdata_slaves[36]
  PIN prdata_slaves[37]
    DIRECTION INPUT ;
    USE SIGNAL ;
    ANTENNAGATEAREA 0.213000 ;
    PORT
      LAYER met3 ;
        RECT 492.505 379.480 496.505 380.080 ;
    END
  END prdata_slaves[37]
  PIN prdata_slaves[38]
    DIRECTION INPUT ;
    USE SIGNAL ;
    ANTENNAGATEAREA 0.159000 ;
    PORT
      LAYER met2 ;
        RECT 154.190 503.225 154.470 507.225 ;
    END
  END prdata_slaves[38]
  PIN prdata_slaves[39]
    DIRECTION INPUT ;
    USE SIGNAL ;
    ANTENNAGATEAREA 0.213000 ;
    PORT
      LAYER met3 ;
        RECT 492.505 383.560 496.505 384.160 ;
    END
  END prdata_slaves[39]
  PIN prdata_slaves[3]
    DIRECTION INPUT ;
    USE SIGNAL ;
    ANTENNAGATEAREA 0.213000 ;
    PORT
      LAYER met3 ;
        RECT 0.000 218.320 4.000 218.920 ;
    END
  END prdata_slaves[3]
  PIN prdata_slaves[40]
    DIRECTION INPUT ;
    USE SIGNAL ;
    ANTENNAGATEAREA 0.159000 ;
    PORT
      LAYER met2 ;
        RECT 418.690 0.000 418.970 4.000 ;
    END
  END prdata_slaves[40]
  PIN prdata_slaves[41]
    DIRECTION INPUT ;
    USE SIGNAL ;
    ANTENNAGATEAREA 0.196500 ;
    PORT
      LAYER met3 ;
        RECT 492.505 291.760 496.505 292.360 ;
    END
  END prdata_slaves[41]
  PIN prdata_slaves[42]
    DIRECTION INPUT ;
    USE SIGNAL ;
    ANTENNAGATEAREA 0.159000 ;
    PORT
      LAYER met2 ;
        RECT 181.790 503.225 182.070 507.225 ;
    END
  END prdata_slaves[42]
  PIN prdata_slaves[43]
    DIRECTION INPUT ;
    USE SIGNAL ;
    ANTENNAGATEAREA 0.213000 ;
    PORT
      LAYER met2 ;
        RECT 443.990 503.225 444.270 507.225 ;
    END
  END prdata_slaves[43]
  PIN prdata_slaves[44]
    DIRECTION INPUT ;
    USE SIGNAL ;
    ANTENNAGATEAREA 0.196500 ;
    PORT
      LAYER met2 ;
        RECT 147.290 503.225 147.570 507.225 ;
    END
  END prdata_slaves[44]
  PIN prdata_slaves[45]
    DIRECTION INPUT ;
    USE SIGNAL ;
    ANTENNAGATEAREA 0.159000 ;
    PORT
      LAYER met3 ;
        RECT 492.505 142.840 496.505 143.440 ;
    END
  END prdata_slaves[45]
  PIN prdata_slaves[46]
    DIRECTION INPUT ;
    USE SIGNAL ;
    ANTENNAGATEAREA 0.196500 ;
    PORT
      LAYER met3 ;
        RECT 0.000 232.600 4.000 233.200 ;
    END
  END prdata_slaves[46]
  PIN prdata_slaves[47]
    DIRECTION INPUT ;
    USE SIGNAL ;
    ANTENNAGATEAREA 0.213000 ;
    PORT
      LAYER met3 ;
        RECT 492.505 171.400 496.505 172.000 ;
    END
  END prdata_slaves[47]
  PIN prdata_slaves[48]
    DIRECTION INPUT ;
    USE SIGNAL ;
    ANTENNAGATEAREA 0.159000 ;
    PORT
      LAYER met2 ;
        RECT 165.690 0.000 165.970 4.000 ;
    END
  END prdata_slaves[48]
  PIN prdata_slaves[49]
    DIRECTION INPUT ;
    USE SIGNAL ;
    ANTENNAGATEAREA 0.196500 ;
    PORT
      LAYER met3 ;
        RECT 0.000 253.000 4.000 253.600 ;
    END
  END prdata_slaves[49]
  PIN prdata_slaves[4]
    DIRECTION INPUT ;
    USE SIGNAL ;
    ANTENNAGATEAREA 0.247500 ;
    PORT
      LAYER met3 ;
        RECT 0.000 104.080 4.000 104.680 ;
    END
  END prdata_slaves[4]
  PIN prdata_slaves[50]
    DIRECTION INPUT ;
    USE SIGNAL ;
    ANTENNAGATEAREA 0.196500 ;
    PORT
      LAYER met3 ;
        RECT 0.000 228.520 4.000 229.120 ;
    END
  END prdata_slaves[50]
  PIN prdata_slaves[51]
    DIRECTION INPUT ;
    USE SIGNAL ;
    ANTENNAGATEAREA 0.159000 ;
    PORT
      LAYER met2 ;
        RECT 483.090 503.225 483.370 507.225 ;
    END
  END prdata_slaves[51]
  PIN prdata_slaves[52]
    DIRECTION INPUT ;
    USE SIGNAL ;
    ANTENNAGATEAREA 0.159000 ;
    PORT
      LAYER met3 ;
        RECT 492.505 181.600 496.505 182.200 ;
    END
  END prdata_slaves[52]
  PIN prdata_slaves[53]
    DIRECTION INPUT ;
    USE SIGNAL ;
    ANTENNAGATEAREA 0.159000 ;
    PORT
      LAYER met2 ;
        RECT 414.090 503.225 414.370 507.225 ;
    END
  END prdata_slaves[53]
  PIN prdata_slaves[54]
    DIRECTION INPUT ;
    USE SIGNAL ;
    ANTENNAGATEAREA 0.196500 ;
    PORT
      LAYER met2 ;
        RECT 124.290 0.000 124.570 4.000 ;
    END
  END prdata_slaves[54]
  PIN prdata_slaves[55]
    DIRECTION INPUT ;
    USE SIGNAL ;
    ANTENNAGATEAREA 0.213000 ;
    PORT
      LAYER met3 ;
        RECT 0.000 452.920 4.000 453.520 ;
    END
  END prdata_slaves[55]
  PIN prdata_slaves[56]
    DIRECTION INPUT ;
    USE SIGNAL ;
    ANTENNAGATEAREA 0.159000 ;
    PORT
      LAYER met2 ;
        RECT 163.390 0.000 163.670 4.000 ;
    END
  END prdata_slaves[56]
  PIN prdata_slaves[57]
    DIRECTION INPUT ;
    USE SIGNAL ;
    ANTENNAGATEAREA 0.213000 ;
    PORT
      LAYER met3 ;
        RECT 0.000 503.920 4.000 504.520 ;
    END
  END prdata_slaves[57]
  PIN prdata_slaves[58]
    DIRECTION INPUT ;
    USE SIGNAL ;
    ANTENNAGATEAREA 0.126000 ;
    PORT
      LAYER met3 ;
        RECT 492.505 457.000 496.505 457.600 ;
    END
  END prdata_slaves[58]
  PIN prdata_slaves[59]
    DIRECTION INPUT ;
    USE SIGNAL ;
    ANTENNAGATEAREA 0.126000 ;
    PORT
      LAYER met3 ;
        RECT 0.000 408.040 4.000 408.640 ;
    END
  END prdata_slaves[59]
  PIN prdata_slaves[5]
    DIRECTION INPUT ;
    USE SIGNAL ;
    ANTENNAGATEAREA 0.196500 ;
    PORT
      LAYER met3 ;
        RECT 0.000 350.920 4.000 351.520 ;
    END
  END prdata_slaves[5]
  PIN prdata_slaves[60]
    DIRECTION INPUT ;
    USE SIGNAL ;
    ANTENNAGATEAREA 0.159000 ;
    PORT
      LAYER met3 ;
        RECT 0.000 53.080 4.000 53.680 ;
    END
  END prdata_slaves[60]
  PIN prdata_slaves[61]
    DIRECTION INPUT ;
    USE SIGNAL ;
    ANTENNAGATEAREA 0.213000 ;
    PORT
      LAYER met2 ;
        RECT 154.190 0.000 154.470 4.000 ;
    END
  END prdata_slaves[61]
  PIN prdata_slaves[62]
    DIRECTION INPUT ;
    USE SIGNAL ;
    ANTENNAGATEAREA 0.247500 ;
    PORT
      LAYER met2 ;
        RECT 82.890 0.000 83.170 4.000 ;
    END
  END prdata_slaves[62]
  PIN prdata_slaves[63]
    DIRECTION INPUT ;
    USE SIGNAL ;
    ANTENNAGATEAREA 0.213000 ;
    PORT
      LAYER met3 ;
        RECT 492.505 55.120 496.505 55.720 ;
    END
  END prdata_slaves[63]
  PIN prdata_slaves[64]
    DIRECTION INPUT ;
    USE SIGNAL ;
    ANTENNAGATEAREA 0.213000 ;
    PORT
      LAYER met2 ;
        RECT 257.690 0.000 257.970 4.000 ;
    END
  END prdata_slaves[64]
  PIN prdata_slaves[65]
    DIRECTION INPUT ;
    USE SIGNAL ;
    ANTENNAGATEAREA 0.159000 ;
    PORT
      LAYER met3 ;
        RECT 492.505 18.400 496.505 19.000 ;
    END
  END prdata_slaves[65]
  PIN prdata_slaves[66]
    DIRECTION INPUT ;
    USE SIGNAL ;
    ANTENNAGATEAREA 0.247500 ;
    PORT
      LAYER met2 ;
        RECT 101.290 0.000 101.570 4.000 ;
    END
  END prdata_slaves[66]
  PIN prdata_slaves[67]
    DIRECTION INPUT ;
    USE SIGNAL ;
    ANTENNAGATEAREA 0.213000 ;
    PORT
      LAYER met2 ;
        RECT 204.790 503.225 205.070 507.225 ;
    END
  END prdata_slaves[67]
  PIN prdata_slaves[68]
    DIRECTION INPUT ;
    USE SIGNAL ;
    ANTENNAGATEAREA 0.196500 ;
    PORT
      LAYER met3 ;
        RECT 492.505 312.160 496.505 312.760 ;
    END
  END prdata_slaves[68]
  PIN prdata_slaves[69]
    DIRECTION INPUT ;
    USE SIGNAL ;
    ANTENNAGATEAREA 0.196500 ;
    PORT
      LAYER met2 ;
        RECT 96.690 503.225 96.970 507.225 ;
    END
  END prdata_slaves[69]
  PIN prdata_slaves[6]
    DIRECTION INPUT ;
    USE SIGNAL ;
    ANTENNAGATEAREA 0.213000 ;
    PORT
      LAYER met2 ;
        RECT 303.690 0.000 303.970 4.000 ;
    END
  END prdata_slaves[6]
  PIN prdata_slaves[70]
    DIRECTION INPUT ;
    USE SIGNAL ;
    ANTENNAGATEAREA 0.126000 ;
    PORT
      LAYER met3 ;
        RECT 492.505 485.560 496.505 486.160 ;
    END
  END prdata_slaves[70]
  PIN prdata_slaves[71]
    DIRECTION INPUT ;
    USE SIGNAL ;
    ANTENNAGATEAREA 0.196500 ;
    PORT
      LAYER met3 ;
        RECT 0.000 401.920 4.000 402.520 ;
    END
  END prdata_slaves[71]
  PIN prdata_slaves[72]
    DIRECTION INPUT ;
    USE SIGNAL ;
    ANTENNAGATEAREA 0.126000 ;
    PORT
      LAYER met3 ;
        RECT 492.505 224.440 496.505 225.040 ;
    END
  END prdata_slaves[72]
  PIN prdata_slaves[73]
    DIRECTION INPUT ;
    USE SIGNAL ;
    ANTENNAGATEAREA 0.247500 ;
    PORT
      LAYER met2 ;
        RECT 135.790 0.000 136.070 4.000 ;
    END
  END prdata_slaves[73]
  PIN prdata_slaves[74]
    DIRECTION INPUT ;
    USE SIGNAL ;
    ANTENNAGATEAREA 0.196500 ;
    PORT
      LAYER met3 ;
        RECT 0.000 361.120 4.000 361.720 ;
    END
  END prdata_slaves[74]
  PIN prdata_slaves[75]
    DIRECTION INPUT ;
    USE SIGNAL ;
    ANTENNAGATEAREA 0.196500 ;
    PORT
      LAYER met3 ;
        RECT 0.000 275.440 4.000 276.040 ;
    END
  END prdata_slaves[75]
  PIN prdata_slaves[76]
    DIRECTION INPUT ;
    USE SIGNAL ;
    ANTENNAGATEAREA 0.213000 ;
    PORT
      LAYER met2 ;
        RECT 280.690 0.000 280.970 4.000 ;
    END
  END prdata_slaves[76]
  PIN prdata_slaves[77]
    DIRECTION INPUT ;
    USE SIGNAL ;
    ANTENNAGATEAREA 0.126000 ;
    PORT
      LAYER met3 ;
        RECT 492.505 299.920 496.505 300.520 ;
    END
  END prdata_slaves[77]
  PIN prdata_slaves[78]
    DIRECTION INPUT ;
    USE SIGNAL ;
    ANTENNAGATEAREA 0.159000 ;
    PORT
      LAYER met2 ;
        RECT 195.590 503.225 195.870 507.225 ;
    END
  END prdata_slaves[78]
  PIN prdata_slaves[79]
    DIRECTION INPUT ;
    USE SIGNAL ;
    ANTENNAGATEAREA 0.213000 ;
    PORT
      LAYER met2 ;
        RECT 423.290 0.000 423.570 4.000 ;
    END
  END prdata_slaves[79]
  PIN prdata_slaves[7]
    DIRECTION INPUT ;
    USE SIGNAL ;
    ANTENNAGATEAREA 0.196500 ;
    PORT
      LAYER met3 ;
        RECT 0.000 428.440 4.000 429.040 ;
    END
  END prdata_slaves[7]
  PIN prdata_slaves[80]
    DIRECTION INPUT ;
    USE SIGNAL ;
    ANTENNAGATEAREA 0.213000 ;
    PORT
      LAYER met3 ;
        RECT 0.000 120.400 4.000 121.000 ;
    END
  END prdata_slaves[80]
  PIN prdata_slaves[81]
    DIRECTION INPUT ;
    USE SIGNAL ;
    ANTENNAGATEAREA 0.159000 ;
    PORT
      LAYER met2 ;
        RECT 181.790 0.000 182.070 4.000 ;
    END
  END prdata_slaves[81]
  PIN prdata_slaves[82]
    DIRECTION INPUT ;
    USE SIGNAL ;
    ANTENNAGATEAREA 0.213000 ;
    PORT
      LAYER met3 ;
        RECT 0.000 26.560 4.000 27.160 ;
    END
  END prdata_slaves[82]
  PIN prdata_slaves[83]
    DIRECTION INPUT ;
    USE SIGNAL ;
    ANTENNAGATEAREA 0.159000 ;
    PORT
      LAYER met3 ;
        RECT 492.505 467.200 496.505 467.800 ;
    END
  END prdata_slaves[83]
  PIN prdata_slaves[84]
    DIRECTION INPUT ;
    USE SIGNAL ;
    ANTENNAGATEAREA 0.126000 ;
    PORT
      LAYER met3 ;
        RECT 0.000 238.720 4.000 239.320 ;
    END
  END prdata_slaves[84]
  PIN prdata_slaves[85]
    DIRECTION INPUT ;
    USE SIGNAL ;
    ANTENNAGATEAREA 0.159000 ;
    PORT
      LAYER met3 ;
        RECT 492.505 336.640 496.505 337.240 ;
    END
  END prdata_slaves[85]
  PIN prdata_slaves[86]
    DIRECTION INPUT ;
    USE SIGNAL ;
    ANTENNAGATEAREA 0.247500 ;
    PORT
      LAYER met3 ;
        RECT 492.505 505.960 496.505 506.560 ;
    END
  END prdata_slaves[86]
  PIN prdata_slaves[87]
    DIRECTION INPUT ;
    USE SIGNAL ;
    ANTENNAGATEAREA 0.213000 ;
    PORT
      LAYER met3 ;
        RECT 492.505 89.800 496.505 90.400 ;
    END
  END prdata_slaves[87]
  PIN prdata_slaves[88]
    DIRECTION INPUT ;
    USE SIGNAL ;
    ANTENNAGATEAREA 0.159000 ;
    PORT
      LAYER met2 ;
        RECT 158.790 0.000 159.070 4.000 ;
    END
  END prdata_slaves[88]
  PIN prdata_slaves[89]
    DIRECTION INPUT ;
    USE SIGNAL ;
    ANTENNAGATEAREA 0.159000 ;
    PORT
      LAYER met3 ;
        RECT 0.000 136.720 4.000 137.320 ;
    END
  END prdata_slaves[89]
  PIN prdata_slaves[8]
    DIRECTION INPUT ;
    USE SIGNAL ;
    ANTENNAGATEAREA 0.213000 ;
    PORT
      LAYER met2 ;
        RECT 39.190 503.225 39.470 507.225 ;
    END
  END prdata_slaves[8]
  PIN prdata_slaves[90]
    DIRECTION INPUT ;
    USE SIGNAL ;
    ANTENNAGATEAREA 0.196500 ;
    PORT
      LAYER met2 ;
        RECT 368.090 503.225 368.370 507.225 ;
    END
  END prdata_slaves[90]
  PIN prdata_slaves[91]
    DIRECTION INPUT ;
    USE SIGNAL ;
    ANTENNAGATEAREA 0.196500 ;
    PORT
      LAYER met2 ;
        RECT 161.090 503.225 161.370 507.225 ;
    END
  END prdata_slaves[91]
  PIN prdata_slaves[92]
    DIRECTION INPUT ;
    USE SIGNAL ;
    ANTENNAGATEAREA 0.159000 ;
    PORT
      LAYER met3 ;
        RECT 0.000 49.000 4.000 49.600 ;
    END
  END prdata_slaves[92]
  PIN prdata_slaves[93]
    DIRECTION INPUT ;
    USE SIGNAL ;
    ANTENNAGATEAREA 0.213000 ;
    PORT
      LAYER met2 ;
        RECT 78.290 0.000 78.570 4.000 ;
    END
  END prdata_slaves[93]
  PIN prdata_slaves[94]
    DIRECTION INPUT ;
    USE SIGNAL ;
    ANTENNAGATEAREA 0.159000 ;
    PORT
      LAYER met3 ;
        RECT 492.505 204.040 496.505 204.640 ;
    END
  END prdata_slaves[94]
  PIN prdata_slaves[95]
    DIRECTION INPUT ;
    USE SIGNAL ;
    ANTENNAGATEAREA 0.213000 ;
    PORT
      LAYER met2 ;
        RECT 420.990 503.225 421.270 507.225 ;
    END
  END prdata_slaves[95]
  PIN prdata_slaves[96]
    DIRECTION INPUT ;
    USE SIGNAL ;
    ANTENNAGATEAREA 0.213000 ;
    PORT
      LAYER met2 ;
        RECT 257.690 503.225 257.970 507.225 ;
    END
  END prdata_slaves[96]
  PIN prdata_slaves[97]
    DIRECTION INPUT ;
    USE SIGNAL ;
    ANTENNAGATEAREA 0.213000 ;
    PORT
      LAYER met3 ;
        RECT 0.000 269.320 4.000 269.920 ;
    END
  END prdata_slaves[97]
  PIN prdata_slaves[98]
    DIRECTION INPUT ;
    USE SIGNAL ;
    ANTENNAGATEAREA 0.196500 ;
    PORT
      LAYER met3 ;
        RECT 492.505 348.880 496.505 349.480 ;
    END
  END prdata_slaves[98]
  PIN prdata_slaves[99]
    DIRECTION INPUT ;
    USE SIGNAL ;
    ANTENNAGATEAREA 0.159000 ;
    PORT
      LAYER met3 ;
        RECT 0.000 151.000 4.000 151.600 ;
    END
  END prdata_slaves[99]
  PIN prdata_slaves[9]
    DIRECTION INPUT ;
    USE SIGNAL ;
    ANTENNAGATEAREA 0.159000 ;
    PORT
      LAYER met2 ;
        RECT 207.090 503.225 207.370 507.225 ;
    END
  END prdata_slaves[9]
  PIN pready_slaves[0]
    DIRECTION INPUT ;
    USE SIGNAL ;
    ANTENNAGATEAREA 0.213000 ;
    PORT
      LAYER met3 ;
        RECT 0.000 403.960 4.000 404.560 ;
    END
  END pready_slaves[0]
  PIN pready_slaves[1]
    DIRECTION INPUT ;
    USE SIGNAL ;
    ANTENNAGATEAREA 0.213000 ;
    PORT
      LAYER met3 ;
        RECT 0.000 181.600 4.000 182.200 ;
    END
  END pready_slaves[1]
  PIN pready_slaves[2]
    DIRECTION INPUT ;
    USE SIGNAL ;
    ANTENNAGATEAREA 0.159000 ;
    PORT
      LAYER met3 ;
        RECT 492.505 153.040 496.505 153.640 ;
    END
  END pready_slaves[2]
  PIN pready_slaves[3]
    DIRECTION INPUT ;
    USE SIGNAL ;
    ANTENNAGATEAREA 0.126000 ;
    PORT
      LAYER met2 ;
        RECT 223.190 0.000 223.470 4.000 ;
    END
  END pready_slaves[3]
  PIN pslverr_slaves[0]
    DIRECTION INPUT ;
    USE SIGNAL ;
    ANTENNAGATEAREA 0.159000 ;
    PORT
      LAYER met3 ;
        RECT 0.000 273.400 4.000 274.000 ;
    END
  END pslverr_slaves[0]
  PIN pslverr_slaves[1]
    DIRECTION INPUT ;
    USE SIGNAL ;
    ANTENNAGATEAREA 0.213000 ;
    PORT
      LAYER met3 ;
        RECT 492.505 461.080 496.505 461.680 ;
    END
  END pslverr_slaves[1]
  PIN pslverr_slaves[2]
    DIRECTION INPUT ;
    USE SIGNAL ;
    ANTENNAGATEAREA 0.159000 ;
    PORT
      LAYER met3 ;
        RECT 0.000 242.800 4.000 243.400 ;
    END
  END pslverr_slaves[2]
  PIN pslverr_slaves[3]
    DIRECTION INPUT ;
    USE SIGNAL ;
    ANTENNAGATEAREA 0.159000 ;
    PORT
      LAYER met3 ;
        RECT 0.000 393.760 4.000 394.360 ;
    END
  END pslverr_slaves[3]
  PIN pslverrmsg_slaves[0]
    DIRECTION INPUT ;
    USE SIGNAL ;
    ANTENNAGATEAREA 0.213000 ;
    PORT
      LAYER met3 ;
        RECT 492.505 122.440 496.505 123.040 ;
    END
  END pslverrmsg_slaves[0]
  PIN pslverrmsg_slaves[100]
    DIRECTION INPUT ;
    USE SIGNAL ;
    PORT
      LAYER met3 ;
        RECT 0.000 246.880 4.000 247.480 ;
    END
  END pslverrmsg_slaves[100]
  PIN pslverrmsg_slaves[101]
    DIRECTION INPUT ;
    USE SIGNAL ;
    PORT
      LAYER met3 ;
        RECT 0.000 448.840 4.000 449.440 ;
    END
  END pslverrmsg_slaves[101]
  PIN pslverrmsg_slaves[102]
    DIRECTION INPUT ;
    USE SIGNAL ;
    PORT
      LAYER met3 ;
        RECT 492.505 28.600 496.505 29.200 ;
    END
  END pslverrmsg_slaves[102]
  PIN pslverrmsg_slaves[103]
    DIRECTION INPUT ;
    USE SIGNAL ;
    PORT
      LAYER met3 ;
        RECT 492.505 399.880 496.505 400.480 ;
    END
  END pslverrmsg_slaves[103]
  PIN pslverrmsg_slaves[104]
    DIRECTION INPUT ;
    USE SIGNAL ;
    PORT
      LAYER met2 ;
        RECT 356.590 503.225 356.870 507.225 ;
    END
  END pslverrmsg_slaves[104]
  PIN pslverrmsg_slaves[105]
    DIRECTION INPUT ;
    USE SIGNAL ;
    PORT
      LAYER met2 ;
        RECT 471.590 0.000 471.870 4.000 ;
    END
  END pslverrmsg_slaves[105]
  PIN pslverrmsg_slaves[106]
    DIRECTION INPUT ;
    USE SIGNAL ;
    PORT
      LAYER met3 ;
        RECT 0.000 365.200 4.000 365.800 ;
    END
  END pslverrmsg_slaves[106]
  PIN pslverrmsg_slaves[107]
    DIRECTION INPUT ;
    USE SIGNAL ;
    PORT
      LAYER met2 ;
        RECT 59.890 503.225 60.170 507.225 ;
    END
  END pslverrmsg_slaves[107]
  PIN pslverrmsg_slaves[108]
    DIRECTION INPUT ;
    USE SIGNAL ;
    PORT
      LAYER met3 ;
        RECT 492.505 151.000 496.505 151.600 ;
    END
  END pslverrmsg_slaves[108]
  PIN pslverrmsg_slaves[109]
    DIRECTION INPUT ;
    USE SIGNAL ;
    PORT
      LAYER met2 ;
        RECT 234.690 0.000 234.970 4.000 ;
    END
  END pslverrmsg_slaves[109]
  PIN pslverrmsg_slaves[10]
    DIRECTION INPUT ;
    USE SIGNAL ;
    ANTENNAGATEAREA 0.213000 ;
    PORT
      LAYER met3 ;
        RECT 492.505 112.240 496.505 112.840 ;
    END
  END pslverrmsg_slaves[10]
  PIN pslverrmsg_slaves[110]
    DIRECTION INPUT ;
    USE SIGNAL ;
    PORT
      LAYER met3 ;
        RECT 0.000 279.520 4.000 280.120 ;
    END
  END pslverrmsg_slaves[110]
  PIN pslverrmsg_slaves[111]
    DIRECTION INPUT ;
    USE SIGNAL ;
    PORT
      LAYER met2 ;
        RECT 342.790 0.000 343.070 4.000 ;
    END
  END pslverrmsg_slaves[111]
  PIN pslverrmsg_slaves[112]
    DIRECTION INPUT ;
    USE SIGNAL ;
    PORT
      LAYER met2 ;
        RECT 188.690 503.225 188.970 507.225 ;
    END
  END pslverrmsg_slaves[112]
  PIN pslverrmsg_slaves[113]
    DIRECTION INPUT ;
    USE SIGNAL ;
    PORT
      LAYER met2 ;
        RECT 29.990 0.000 30.270 4.000 ;
    END
  END pslverrmsg_slaves[113]
  PIN pslverrmsg_slaves[114]
    DIRECTION INPUT ;
    USE SIGNAL ;
    PORT
      LAYER met2 ;
        RECT 48.390 0.000 48.670 4.000 ;
    END
  END pslverrmsg_slaves[114]
  PIN pslverrmsg_slaves[115]
    DIRECTION INPUT ;
    USE SIGNAL ;
    PORT
      LAYER met2 ;
        RECT 414.090 0.000 414.370 4.000 ;
    END
  END pslverrmsg_slaves[115]
  PIN pslverrmsg_slaves[116]
    DIRECTION INPUT ;
    USE SIGNAL ;
    PORT
      LAYER met3 ;
        RECT 492.505 12.280 496.505 12.880 ;
    END
  END pslverrmsg_slaves[116]
  PIN pslverrmsg_slaves[117]
    DIRECTION INPUT ;
    USE SIGNAL ;
    PORT
      LAYER met3 ;
        RECT 0.000 171.400 4.000 172.000 ;
    END
  END pslverrmsg_slaves[117]
  PIN pslverrmsg_slaves[118]
    DIRECTION INPUT ;
    USE SIGNAL ;
    PORT
      LAYER met3 ;
        RECT 492.505 110.200 496.505 110.800 ;
    END
  END pslverrmsg_slaves[118]
  PIN pslverrmsg_slaves[119]
    DIRECTION INPUT ;
    USE SIGNAL ;
    PORT
      LAYER met3 ;
        RECT 0.000 144.880 4.000 145.480 ;
    END
  END pslverrmsg_slaves[119]
  PIN pslverrmsg_slaves[11]
    DIRECTION INPUT ;
    USE SIGNAL ;
    ANTENNAGATEAREA 0.213000 ;
    PORT
      LAYER met2 ;
        RECT 177.190 503.225 177.470 507.225 ;
    END
  END pslverrmsg_slaves[11]
  PIN pslverrmsg_slaves[120]
    DIRECTION INPUT ;
    USE SIGNAL ;
    PORT
      LAYER met2 ;
        RECT 135.790 503.225 136.070 507.225 ;
    END
  END pslverrmsg_slaves[120]
  PIN pslverrmsg_slaves[121]
    DIRECTION INPUT ;
    USE SIGNAL ;
    PORT
      LAYER met3 ;
        RECT 0.000 59.200 4.000 59.800 ;
    END
  END pslverrmsg_slaves[121]
  PIN pslverrmsg_slaves[122]
    DIRECTION INPUT ;
    USE SIGNAL ;
    PORT
      LAYER met2 ;
        RECT 172.590 503.225 172.870 507.225 ;
    END
  END pslverrmsg_slaves[122]
  PIN pslverrmsg_slaves[123]
    DIRECTION INPUT ;
    USE SIGNAL ;
    PORT
      LAYER met3 ;
        RECT 0.000 499.840 4.000 500.440 ;
    END
  END pslverrmsg_slaves[123]
  PIN pslverrmsg_slaves[124]
    DIRECTION INPUT ;
    USE SIGNAL ;
    PORT
      LAYER met3 ;
        RECT 492.505 220.360 496.505 220.960 ;
    END
  END pslverrmsg_slaves[124]
  PIN pslverrmsg_slaves[125]
    DIRECTION INPUT ;
    USE SIGNAL ;
    PORT
      LAYER met3 ;
        RECT 492.505 22.480 496.505 23.080 ;
    END
  END pslverrmsg_slaves[125]
  PIN pslverrmsg_slaves[126]
    DIRECTION INPUT ;
    USE SIGNAL ;
    PORT
      LAYER met3 ;
        RECT 492.505 210.160 496.505 210.760 ;
    END
  END pslverrmsg_slaves[126]
  PIN pslverrmsg_slaves[127]
    DIRECTION INPUT ;
    USE SIGNAL ;
    PORT
      LAYER met2 ;
        RECT 250.790 503.225 251.070 507.225 ;
    END
  END pslverrmsg_slaves[127]
  PIN pslverrmsg_slaves[12]
    DIRECTION INPUT ;
    USE SIGNAL ;
    ANTENNAGATEAREA 0.213000 ;
    PORT
      LAYER met2 ;
        RECT 262.290 0.000 262.570 4.000 ;
    END
  END pslverrmsg_slaves[12]
  PIN pslverrmsg_slaves[13]
    DIRECTION INPUT ;
    USE SIGNAL ;
    ANTENNAGATEAREA 0.196500 ;
    PORT
      LAYER met2 ;
        RECT 292.190 503.225 292.470 507.225 ;
    END
  END pslverrmsg_slaves[13]
  PIN pslverrmsg_slaves[14]
    DIRECTION INPUT ;
    USE SIGNAL ;
    ANTENNAGATEAREA 0.213000 ;
    PORT
      LAYER met3 ;
        RECT 0.000 505.960 4.000 506.560 ;
    END
  END pslverrmsg_slaves[14]
  PIN pslverrmsg_slaves[15]
    DIRECTION INPUT ;
    USE SIGNAL ;
    ANTENNAGATEAREA 0.213000 ;
    PORT
      LAYER met3 ;
        RECT 492.505 487.600 496.505 488.200 ;
    END
  END pslverrmsg_slaves[15]
  PIN pslverrmsg_slaves[16]
    DIRECTION INPUT ;
    USE SIGNAL ;
    PORT
      LAYER met2 ;
        RECT 66.790 0.000 67.070 4.000 ;
    END
  END pslverrmsg_slaves[16]
  PIN pslverrmsg_slaves[17]
    DIRECTION INPUT ;
    USE SIGNAL ;
    PORT
      LAYER met2 ;
        RECT 391.090 0.000 391.370 4.000 ;
    END
  END pslverrmsg_slaves[17]
  PIN pslverrmsg_slaves[18]
    DIRECTION INPUT ;
    USE SIGNAL ;
    PORT
      LAYER met2 ;
        RECT 437.090 0.000 437.370 4.000 ;
    END
  END pslverrmsg_slaves[18]
  PIN pslverrmsg_slaves[19]
    DIRECTION INPUT ;
    USE SIGNAL ;
    PORT
      LAYER met3 ;
        RECT 492.505 238.720 496.505 239.320 ;
    END
  END pslverrmsg_slaves[19]
  PIN pslverrmsg_slaves[1]
    DIRECTION INPUT ;
    USE SIGNAL ;
    ANTENNAGATEAREA 0.213000 ;
    PORT
      LAYER met3 ;
        RECT 0.000 110.200 4.000 110.800 ;
    END
  END pslverrmsg_slaves[1]
  PIN pslverrmsg_slaves[20]
    DIRECTION INPUT ;
    USE SIGNAL ;
    PORT
      LAYER met3 ;
        RECT 492.505 63.280 496.505 63.880 ;
    END
  END pslverrmsg_slaves[20]
  PIN pslverrmsg_slaves[21]
    DIRECTION INPUT ;
    USE SIGNAL ;
    PORT
      LAYER met2 ;
        RECT 239.290 0.000 239.570 4.000 ;
    END
  END pslverrmsg_slaves[21]
  PIN pslverrmsg_slaves[22]
    DIRECTION INPUT ;
    USE SIGNAL ;
    PORT
      LAYER met2 ;
        RECT 356.590 0.000 356.870 4.000 ;
    END
  END pslverrmsg_slaves[22]
  PIN pslverrmsg_slaves[23]
    DIRECTION INPUT ;
    USE SIGNAL ;
    PORT
      LAYER met2 ;
        RECT 227.790 503.225 228.070 507.225 ;
    END
  END pslverrmsg_slaves[23]
  PIN pslverrmsg_slaves[24]
    DIRECTION INPUT ;
    USE SIGNAL ;
    PORT
      LAYER met3 ;
        RECT 0.000 118.360 4.000 118.960 ;
    END
  END pslverrmsg_slaves[24]
  PIN pslverrmsg_slaves[25]
    DIRECTION INPUT ;
    USE SIGNAL ;
    PORT
      LAYER met3 ;
        RECT 0.000 306.040 4.000 306.640 ;
    END
  END pslverrmsg_slaves[25]
  PIN pslverrmsg_slaves[26]
    DIRECTION INPUT ;
    USE SIGNAL ;
    PORT
      LAYER met2 ;
        RECT 377.290 0.000 377.570 4.000 ;
    END
  END pslverrmsg_slaves[26]
  PIN pslverrmsg_slaves[27]
    DIRECTION INPUT ;
    USE SIGNAL ;
    PORT
      LAYER met2 ;
        RECT 299.090 0.000 299.370 4.000 ;
    END
  END pslverrmsg_slaves[27]
  PIN pslverrmsg_slaves[28]
    DIRECTION INPUT ;
    USE SIGNAL ;
    PORT
      LAYER met3 ;
        RECT 0.000 259.120 4.000 259.720 ;
    END
  END pslverrmsg_slaves[28]
  PIN pslverrmsg_slaves[29]
    DIRECTION INPUT ;
    USE SIGNAL ;
    PORT
      LAYER met3 ;
        RECT 492.505 255.040 496.505 255.640 ;
    END
  END pslverrmsg_slaves[29]
  PIN pslverrmsg_slaves[2]
    DIRECTION INPUT ;
    USE SIGNAL ;
    ANTENNAGATEAREA 0.196500 ;
    PORT
      LAYER met2 ;
        RECT 250.790 0.000 251.070 4.000 ;
    END
  END pslverrmsg_slaves[2]
  PIN pslverrmsg_slaves[30]
    DIRECTION INPUT ;
    USE SIGNAL ;
    PORT
      LAYER met2 ;
        RECT 25.390 503.225 25.670 507.225 ;
    END
  END pslverrmsg_slaves[30]
  PIN pslverrmsg_slaves[31]
    DIRECTION INPUT ;
    USE SIGNAL ;
    PORT
      LAYER met2 ;
        RECT 476.190 0.000 476.470 4.000 ;
    END
  END pslverrmsg_slaves[31]
  PIN pslverrmsg_slaves[32]
    DIRECTION INPUT ;
    USE SIGNAL ;
    PORT
      LAYER met3 ;
        RECT 492.505 102.040 496.505 102.640 ;
    END
  END pslverrmsg_slaves[32]
  PIN pslverrmsg_slaves[33]
    DIRECTION INPUT ;
    USE SIGNAL ;
    PORT
      LAYER met3 ;
        RECT 492.505 79.600 496.505 80.200 ;
    END
  END pslverrmsg_slaves[33]
  PIN pslverrmsg_slaves[34]
    DIRECTION INPUT ;
    USE SIGNAL ;
    PORT
      LAYER met2 ;
        RECT 188.690 0.000 188.970 4.000 ;
    END
  END pslverrmsg_slaves[34]
  PIN pslverrmsg_slaves[35]
    DIRECTION INPUT ;
    USE SIGNAL ;
    PORT
      LAYER met3 ;
        RECT 0.000 489.640 4.000 490.240 ;
    END
  END pslverrmsg_slaves[35]
  PIN pslverrmsg_slaves[36]
    DIRECTION INPUT ;
    USE SIGNAL ;
    PORT
      LAYER met2 ;
        RECT 354.290 0.000 354.570 4.000 ;
    END
  END pslverrmsg_slaves[36]
  PIN pslverrmsg_slaves[37]
    DIRECTION INPUT ;
    USE SIGNAL ;
    PORT
      LAYER met3 ;
        RECT 0.000 412.120 4.000 412.720 ;
    END
  END pslverrmsg_slaves[37]
  PIN pslverrmsg_slaves[38]
    DIRECTION INPUT ;
    USE SIGNAL ;
    PORT
      LAYER met2 ;
        RECT 411.790 0.000 412.070 4.000 ;
    END
  END pslverrmsg_slaves[38]
  PIN pslverrmsg_slaves[39]
    DIRECTION INPUT ;
    USE SIGNAL ;
    PORT
      LAYER met3 ;
        RECT 492.505 410.080 496.505 410.680 ;
    END
  END pslverrmsg_slaves[39]
  PIN pslverrmsg_slaves[3]
    DIRECTION INPUT ;
    USE SIGNAL ;
    ANTENNAGATEAREA 0.213000 ;
    PORT
      LAYER met3 ;
        RECT 0.000 93.880 4.000 94.480 ;
    END
  END pslverrmsg_slaves[3]
  PIN pslverrmsg_slaves[40]
    DIRECTION INPUT ;
    USE SIGNAL ;
    PORT
      LAYER met3 ;
        RECT 492.505 4.120 496.505 4.720 ;
    END
  END pslverrmsg_slaves[40]
  PIN pslverrmsg_slaves[41]
    DIRECTION INPUT ;
    USE SIGNAL ;
    PORT
      LAYER met3 ;
        RECT 492.505 240.760 496.505 241.360 ;
    END
  END pslverrmsg_slaves[41]
  PIN pslverrmsg_slaves[42]
    DIRECTION INPUT ;
    USE SIGNAL ;
    PORT
      LAYER met3 ;
        RECT 0.000 108.160 4.000 108.760 ;
    END
  END pslverrmsg_slaves[42]
  PIN pslverrmsg_slaves[43]
    DIRECTION INPUT ;
    USE SIGNAL ;
    PORT
      LAYER met3 ;
        RECT 0.000 334.600 4.000 335.200 ;
    END
  END pslverrmsg_slaves[43]
  PIN pslverrmsg_slaves[44]
    DIRECTION INPUT ;
    USE SIGNAL ;
    PORT
      LAYER met2 ;
        RECT 128.890 0.000 129.170 4.000 ;
    END
  END pslverrmsg_slaves[44]
  PIN pslverrmsg_slaves[45]
    DIRECTION INPUT ;
    USE SIGNAL ;
    PORT
      LAYER met2 ;
        RECT 4.690 503.225 4.970 507.225 ;
    END
  END pslverrmsg_slaves[45]
  PIN pslverrmsg_slaves[46]
    DIRECTION INPUT ;
    USE SIGNAL ;
    PORT
      LAYER met2 ;
        RECT 379.590 0.000 379.870 4.000 ;
    END
  END pslverrmsg_slaves[46]
  PIN pslverrmsg_slaves[47]
    DIRECTION INPUT ;
    USE SIGNAL ;
    PORT
      LAYER met3 ;
        RECT 0.000 89.800 4.000 90.400 ;
    END
  END pslverrmsg_slaves[47]
  PIN pslverrmsg_slaves[48]
    DIRECTION INPUT ;
    USE SIGNAL ;
    PORT
      LAYER met2 ;
        RECT 478.490 503.225 478.770 507.225 ;
    END
  END pslverrmsg_slaves[48]
  PIN pslverrmsg_slaves[49]
    DIRECTION INPUT ;
    USE SIGNAL ;
    PORT
      LAYER met3 ;
        RECT 0.000 422.320 4.000 422.920 ;
    END
  END pslverrmsg_slaves[49]
  PIN pslverrmsg_slaves[4]
    DIRECTION INPUT ;
    USE SIGNAL ;
    ANTENNAGATEAREA 0.159000 ;
    PORT
      LAYER met2 ;
        RECT 82.890 503.225 83.170 507.225 ;
    END
  END pslverrmsg_slaves[4]
  PIN pslverrmsg_slaves[50]
    DIRECTION INPUT ;
    USE SIGNAL ;
    PORT
      LAYER met2 ;
        RECT 395.690 0.000 395.970 4.000 ;
    END
  END pslverrmsg_slaves[50]
  PIN pslverrmsg_slaves[51]
    DIRECTION INPUT ;
    USE SIGNAL ;
    PORT
      LAYER met3 ;
        RECT 492.505 146.920 496.505 147.520 ;
    END
  END pslverrmsg_slaves[51]
  PIN pslverrmsg_slaves[52]
    DIRECTION INPUT ;
    USE SIGNAL ;
    PORT
      LAYER met2 ;
        RECT 20.790 503.225 21.070 507.225 ;
    END
  END pslverrmsg_slaves[52]
  PIN pslverrmsg_slaves[53]
    DIRECTION INPUT ;
    USE SIGNAL ;
    PORT
      LAYER met2 ;
        RECT 460.090 503.225 460.370 507.225 ;
    END
  END pslverrmsg_slaves[53]
  PIN pslverrmsg_slaves[54]
    DIRECTION INPUT ;
    USE SIGNAL ;
    PORT
      LAYER met3 ;
        RECT 492.505 14.320 496.505 14.920 ;
    END
  END pslverrmsg_slaves[54]
  PIN pslverrmsg_slaves[55]
    DIRECTION INPUT ;
    USE SIGNAL ;
    PORT
      LAYER met2 ;
        RECT 232.390 0.000 232.670 4.000 ;
    END
  END pslverrmsg_slaves[55]
  PIN pslverrmsg_slaves[56]
    DIRECTION INPUT ;
    USE SIGNAL ;
    PORT
      LAYER met2 ;
        RECT 269.190 0.000 269.470 4.000 ;
    END
  END pslverrmsg_slaves[56]
  PIN pslverrmsg_slaves[57]
    DIRECTION INPUT ;
    USE SIGNAL ;
    PORT
      LAYER met3 ;
        RECT 492.505 450.880 496.505 451.480 ;
    END
  END pslverrmsg_slaves[57]
  PIN pslverrmsg_slaves[58]
    DIRECTION INPUT ;
    USE SIGNAL ;
    PORT
      LAYER met3 ;
        RECT 492.505 65.320 496.505 65.920 ;
    END
  END pslverrmsg_slaves[58]
  PIN pslverrmsg_slaves[59]
    DIRECTION INPUT ;
    USE SIGNAL ;
    PORT
      LAYER met2 ;
        RECT 466.990 503.225 467.270 507.225 ;
    END
  END pslverrmsg_slaves[59]
  PIN pslverrmsg_slaves[5]
    DIRECTION INPUT ;
    USE SIGNAL ;
    ANTENNAGATEAREA 0.196500 ;
    PORT
      LAYER met2 ;
        RECT 133.490 0.000 133.770 4.000 ;
    END
  END pslverrmsg_slaves[5]
  PIN pslverrmsg_slaves[60]
    DIRECTION INPUT ;
    USE SIGNAL ;
    PORT
      LAYER met2 ;
        RECT 138.090 503.225 138.370 507.225 ;
    END
  END pslverrmsg_slaves[60]
  PIN pslverrmsg_slaves[61]
    DIRECTION INPUT ;
    USE SIGNAL ;
    PORT
      LAYER met2 ;
        RECT 43.790 503.225 44.070 507.225 ;
    END
  END pslverrmsg_slaves[61]
  PIN pslverrmsg_slaves[62]
    DIRECTION INPUT ;
    USE SIGNAL ;
    PORT
      LAYER met2 ;
        RECT 124.290 503.225 124.570 507.225 ;
    END
  END pslverrmsg_slaves[62]
  PIN pslverrmsg_slaves[63]
    DIRECTION INPUT ;
    USE SIGNAL ;
    PORT
      LAYER met3 ;
        RECT 492.505 265.240 496.505 265.840 ;
    END
  END pslverrmsg_slaves[63]
  PIN pslverrmsg_slaves[64]
    DIRECTION INPUT ;
    USE SIGNAL ;
    PORT
      LAYER met2 ;
        RECT 372.690 503.225 372.970 507.225 ;
    END
  END pslverrmsg_slaves[64]
  PIN pslverrmsg_slaves[65]
    DIRECTION INPUT ;
    USE SIGNAL ;
    PORT
      LAYER met2 ;
        RECT 432.490 503.225 432.770 507.225 ;
    END
  END pslverrmsg_slaves[65]
  PIN pslverrmsg_slaves[66]
    DIRECTION INPUT ;
    USE SIGNAL ;
    PORT
      LAYER met3 ;
        RECT 0.000 38.800 4.000 39.400 ;
    END
  END pslverrmsg_slaves[66]
  PIN pslverrmsg_slaves[67]
    DIRECTION INPUT ;
    USE SIGNAL ;
    PORT
      LAYER met3 ;
        RECT 0.000 418.240 4.000 418.840 ;
    END
  END pslverrmsg_slaves[67]
  PIN pslverrmsg_slaves[68]
    DIRECTION INPUT ;
    USE SIGNAL ;
    PORT
      LAYER met2 ;
        RECT 372.690 0.000 372.970 4.000 ;
    END
  END pslverrmsg_slaves[68]
  PIN pslverrmsg_slaves[69]
    DIRECTION INPUT ;
    USE SIGNAL ;
    PORT
      LAYER met3 ;
        RECT 492.505 248.920 496.505 249.520 ;
    END
  END pslverrmsg_slaves[69]
  PIN pslverrmsg_slaves[6]
    DIRECTION INPUT ;
    USE SIGNAL ;
    ANTENNAGATEAREA 0.196500 ;
    PORT
      LAYER met2 ;
        RECT 98.990 0.000 99.270 4.000 ;
    END
  END pslverrmsg_slaves[6]
  PIN pslverrmsg_slaves[70]
    DIRECTION INPUT ;
    USE SIGNAL ;
    PORT
      LAYER met2 ;
        RECT 328.990 503.225 329.270 507.225 ;
    END
  END pslverrmsg_slaves[70]
  PIN pslverrmsg_slaves[71]
    DIRECTION INPUT ;
    USE SIGNAL ;
    PORT
      LAYER met2 ;
        RECT 296.790 0.000 297.070 4.000 ;
    END
  END pslverrmsg_slaves[71]
  PIN pslverrmsg_slaves[72]
    DIRECTION INPUT ;
    USE SIGNAL ;
    PORT
      LAYER met3 ;
        RECT 0.000 459.040 4.000 459.640 ;
    END
  END pslverrmsg_slaves[72]
  PIN pslverrmsg_slaves[73]
    DIRECTION INPUT ;
    USE SIGNAL ;
    PORT
      LAYER met2 ;
        RECT 73.690 503.225 73.970 507.225 ;
    END
  END pslverrmsg_slaves[73]
  PIN pslverrmsg_slaves[74]
    DIRECTION INPUT ;
    USE SIGNAL ;
    PORT
      LAYER met3 ;
        RECT 492.505 191.800 496.505 192.400 ;
    END
  END pslverrmsg_slaves[74]
  PIN pslverrmsg_slaves[75]
    DIRECTION INPUT ;
    USE SIGNAL ;
    PORT
      LAYER met3 ;
        RECT 492.505 42.880 496.505 43.480 ;
    END
  END pslverrmsg_slaves[75]
  PIN pslverrmsg_slaves[76]
    DIRECTION INPUT ;
    USE SIGNAL ;
    PORT
      LAYER met3 ;
        RECT 492.505 271.360 496.505 271.960 ;
    END
  END pslverrmsg_slaves[76]
  PIN pslverrmsg_slaves[77]
    DIRECTION INPUT ;
    USE SIGNAL ;
    PORT
      LAYER met3 ;
        RECT 0.000 340.720 4.000 341.320 ;
    END
  END pslverrmsg_slaves[77]
  PIN pslverrmsg_slaves[78]
    DIRECTION INPUT ;
    USE SIGNAL ;
    PORT
      LAYER met2 ;
        RECT 186.390 0.000 186.670 4.000 ;
    END
  END pslverrmsg_slaves[78]
  PIN pslverrmsg_slaves[79]
    DIRECTION INPUT ;
    USE SIGNAL ;
    PORT
      LAYER met2 ;
        RECT 128.890 503.225 129.170 507.225 ;
    END
  END pslverrmsg_slaves[79]
  PIN pslverrmsg_slaves[7]
    DIRECTION INPUT ;
    USE SIGNAL ;
    ANTENNAGATEAREA 0.159000 ;
    PORT
      LAYER met2 ;
        RECT 94.390 503.225 94.670 507.225 ;
    END
  END pslverrmsg_slaves[7]
  PIN pslverrmsg_slaves[80]
    DIRECTION INPUT ;
    USE SIGNAL ;
    PORT
      LAYER met2 ;
        RECT 108.190 503.225 108.470 507.225 ;
    END
  END pslverrmsg_slaves[80]
  PIN pslverrmsg_slaves[81]
    DIRECTION INPUT ;
    USE SIGNAL ;
    PORT
      LAYER met3 ;
        RECT 492.505 234.640 496.505 235.240 ;
    END
  END pslverrmsg_slaves[81]
  PIN pslverrmsg_slaves[82]
    DIRECTION INPUT ;
    USE SIGNAL ;
    PORT
      LAYER met3 ;
        RECT 0.000 255.040 4.000 255.640 ;
    END
  END pslverrmsg_slaves[82]
  PIN pslverrmsg_slaves[83]
    DIRECTION INPUT ;
    USE SIGNAL ;
    PORT
      LAYER met3 ;
        RECT 492.505 132.640 496.505 133.240 ;
    END
  END pslverrmsg_slaves[83]
  PIN pslverrmsg_slaves[84]
    DIRECTION INPUT ;
    USE SIGNAL ;
    PORT
      LAYER met3 ;
        RECT 492.505 328.480 496.505 329.080 ;
    END
  END pslverrmsg_slaves[84]
  PIN pslverrmsg_slaves[85]
    DIRECTION INPUT ;
    USE SIGNAL ;
    PORT
      LAYER met3 ;
        RECT 0.000 8.200 4.000 8.800 ;
    END
  END pslverrmsg_slaves[85]
  PIN pslverrmsg_slaves[86]
    DIRECTION INPUT ;
    USE SIGNAL ;
    PORT
      LAYER met3 ;
        RECT 0.000 69.400 4.000 70.000 ;
    END
  END pslverrmsg_slaves[86]
  PIN pslverrmsg_slaves[87]
    DIRECTION INPUT ;
    USE SIGNAL ;
    PORT
      LAYER met2 ;
        RECT 278.390 0.000 278.670 4.000 ;
    END
  END pslverrmsg_slaves[87]
  PIN pslverrmsg_slaves[88]
    DIRECTION INPUT ;
    USE SIGNAL ;
    PORT
      LAYER met3 ;
        RECT 0.000 381.520 4.000 382.120 ;
    END
  END pslverrmsg_slaves[88]
  PIN pslverrmsg_slaves[89]
    DIRECTION INPUT ;
    USE SIGNAL ;
    PORT
      LAYER met3 ;
        RECT 492.505 95.920 496.505 96.520 ;
    END
  END pslverrmsg_slaves[89]
  PIN pslverrmsg_slaves[8]
    DIRECTION INPUT ;
    USE SIGNAL ;
    ANTENNAGATEAREA 0.213000 ;
    PORT
      LAYER met2 ;
        RECT 32.290 0.000 32.570 4.000 ;
    END
  END pslverrmsg_slaves[8]
  PIN pslverrmsg_slaves[90]
    DIRECTION INPUT ;
    USE SIGNAL ;
    PORT
      LAYER met2 ;
        RECT 151.890 0.000 152.170 4.000 ;
    END
  END pslverrmsg_slaves[90]
  PIN pslverrmsg_slaves[91]
    DIRECTION INPUT ;
    USE SIGNAL ;
    PORT
      LAYER met3 ;
        RECT 492.505 85.720 496.505 86.320 ;
    END
  END pslverrmsg_slaves[91]
  PIN pslverrmsg_slaves[92]
    DIRECTION INPUT ;
    USE SIGNAL ;
    PORT
      LAYER met3 ;
        RECT 492.505 440.680 496.505 441.280 ;
    END
  END pslverrmsg_slaves[92]
  PIN pslverrmsg_slaves[93]
    DIRECTION INPUT ;
    USE SIGNAL ;
    PORT
      LAYER met3 ;
        RECT 492.505 208.120 496.505 208.720 ;
    END
  END pslverrmsg_slaves[93]
  PIN pslverrmsg_slaves[94]
    DIRECTION INPUT ;
    USE SIGNAL ;
    PORT
      LAYER met3 ;
        RECT 0.000 336.640 4.000 337.240 ;
    END
  END pslverrmsg_slaves[94]
  PIN pslverrmsg_slaves[95]
    DIRECTION INPUT ;
    USE SIGNAL ;
    PORT
      LAYER met3 ;
        RECT 492.505 177.520 496.505 178.120 ;
    END
  END pslverrmsg_slaves[95]
  PIN pslverrmsg_slaves[96]
    DIRECTION INPUT ;
    USE SIGNAL ;
    PORT
      LAYER met2 ;
        RECT 361.190 0.000 361.470 4.000 ;
    END
  END pslverrmsg_slaves[96]
  PIN pslverrmsg_slaves[97]
    DIRECTION INPUT ;
    USE SIGNAL ;
    PORT
      LAYER met2 ;
        RECT 471.590 503.225 471.870 507.225 ;
    END
  END pslverrmsg_slaves[97]
  PIN pslverrmsg_slaves[98]
    DIRECTION INPUT ;
    USE SIGNAL ;
    PORT
      LAYER met2 ;
        RECT 333.590 0.000 333.870 4.000 ;
    END
  END pslverrmsg_slaves[98]
  PIN pslverrmsg_slaves[99]
    DIRECTION INPUT ;
    USE SIGNAL ;
    PORT
      LAYER met3 ;
        RECT 0.000 2.080 4.000 2.680 ;
    END
  END pslverrmsg_slaves[99]
  PIN pslverrmsg_slaves[9]
    DIRECTION INPUT ;
    USE SIGNAL ;
    ANTENNAGATEAREA 0.213000 ;
    PORT
      LAYER met3 ;
        RECT 492.505 475.360 496.505 475.960 ;
    END
  END pslverrmsg_slaves[9]
  PIN s_axi_aclk
    DIRECTION INPUT ;
    USE SIGNAL ;
    ANTENNAGATEAREA 1.286700 ;
    ANTENNADIFFAREA 0.434700 ;
    PORT
      LAYER met2 ;
        RECT 473.890 503.225 474.170 507.225 ;
    END
  END s_axi_aclk
  PIN s_axi_araddr[0]
    DIRECTION INPUT ;
    USE SIGNAL ;
    ANTENNAGATEAREA 0.159000 ;
    PORT
      LAYER met2 ;
        RECT 345.090 503.225 345.370 507.225 ;
    END
  END s_axi_araddr[0]
  PIN s_axi_araddr[10]
    DIRECTION INPUT ;
    USE SIGNAL ;
    ANTENNAGATEAREA 0.196500 ;
    PORT
      LAYER met3 ;
        RECT 0.000 367.240 4.000 367.840 ;
    END
  END s_axi_araddr[10]
  PIN s_axi_araddr[11]
    DIRECTION INPUT ;
    USE SIGNAL ;
    ANTENNAGATEAREA 0.213000 ;
    PORT
      LAYER met2 ;
        RECT 158.790 503.225 159.070 507.225 ;
    END
  END s_axi_araddr[11]
  PIN s_axi_araddr[12]
    DIRECTION INPUT ;
    USE SIGNAL ;
    ANTENNAGATEAREA 0.196500 ;
    PORT
      LAYER met2 ;
        RECT 170.290 0.000 170.570 4.000 ;
    END
  END s_axi_araddr[12]
  PIN s_axi_araddr[13]
    DIRECTION INPUT ;
    USE SIGNAL ;
    ANTENNAGATEAREA 0.126000 ;
    PORT
      LAYER met2 ;
        RECT 66.790 503.225 67.070 507.225 ;
    END
  END s_axi_araddr[13]
  PIN s_axi_araddr[14]
    DIRECTION INPUT ;
    USE SIGNAL ;
    ANTENNAGATEAREA 0.196500 ;
    PORT
      LAYER met3 ;
        RECT 0.000 357.040 4.000 357.640 ;
    END
  END s_axi_araddr[14]
  PIN s_axi_araddr[15]
    DIRECTION INPUT ;
    USE SIGNAL ;
    ANTENNAGATEAREA 0.213000 ;
    PORT
      LAYER met3 ;
        RECT 492.505 285.640 496.505 286.240 ;
    END
  END s_axi_araddr[15]
  PIN s_axi_araddr[16]
    DIRECTION INPUT ;
    USE SIGNAL ;
    ANTENNAGATEAREA 0.159000 ;
    PORT
      LAYER met2 ;
        RECT 264.590 503.225 264.870 507.225 ;
    END
  END s_axi_araddr[16]
  PIN s_axi_araddr[17]
    DIRECTION INPUT ;
    USE SIGNAL ;
    ANTENNAGATEAREA 0.159000 ;
    PORT
      LAYER met2 ;
        RECT 402.590 0.000 402.870 4.000 ;
    END
  END s_axi_araddr[17]
  PIN s_axi_araddr[18]
    DIRECTION INPUT ;
    USE SIGNAL ;
    ANTENNAGATEAREA 0.196500 ;
    PORT
      LAYER met3 ;
        RECT 0.000 32.680 4.000 33.280 ;
    END
  END s_axi_araddr[18]
  PIN s_axi_araddr[19]
    DIRECTION INPUT ;
    USE SIGNAL ;
    ANTENNAGATEAREA 0.213000 ;
    PORT
      LAYER met3 ;
        RECT 492.505 332.560 496.505 333.160 ;
    END
  END s_axi_araddr[19]
  PIN s_axi_araddr[1]
    DIRECTION INPUT ;
    USE SIGNAL ;
    ANTENNAGATEAREA 0.213000 ;
    PORT
      LAYER met2 ;
        RECT 485.390 503.225 485.670 507.225 ;
    END
  END s_axi_araddr[1]
  PIN s_axi_araddr[20]
    DIRECTION INPUT ;
    USE SIGNAL ;
    ANTENNAGATEAREA 0.213000 ;
    PORT
      LAYER met3 ;
        RECT 492.505 434.560 496.505 435.160 ;
    END
  END s_axi_araddr[20]
  PIN s_axi_araddr[21]
    DIRECTION INPUT ;
    USE SIGNAL ;
    ANTENNAGATEAREA 0.159000 ;
    PORT
      LAYER met2 ;
        RECT 483.090 0.000 483.370 4.000 ;
    END
  END s_axi_araddr[21]
  PIN s_axi_araddr[22]
    DIRECTION INPUT ;
    USE SIGNAL ;
    ANTENNAGATEAREA 0.196500 ;
    PORT
      LAYER met3 ;
        RECT 0.000 293.800 4.000 294.400 ;
    END
  END s_axi_araddr[22]
  PIN s_axi_araddr[23]
    DIRECTION INPUT ;
    USE SIGNAL ;
    ANTENNAGATEAREA 0.213000 ;
    PORT
      LAYER met3 ;
        RECT 0.000 469.240 4.000 469.840 ;
    END
  END s_axi_araddr[23]
  PIN s_axi_araddr[24]
    DIRECTION INPUT ;
    USE SIGNAL ;
    ANTENNAGATEAREA 0.196500 ;
    PORT
      LAYER met3 ;
        RECT 0.000 377.440 4.000 378.040 ;
    END
  END s_axi_araddr[24]
  PIN s_axi_araddr[25]
    DIRECTION INPUT ;
    USE SIGNAL ;
    ANTENNAGATEAREA 0.196500 ;
    PORT
      LAYER met2 ;
        RECT 94.390 0.000 94.670 4.000 ;
    END
  END s_axi_araddr[25]
  PIN s_axi_araddr[26]
    DIRECTION INPUT ;
    USE SIGNAL ;
    ANTENNAGATEAREA 0.196500 ;
    PORT
      LAYER met2 ;
        RECT 140.390 0.000 140.670 4.000 ;
    END
  END s_axi_araddr[26]
  PIN s_axi_araddr[27]
    DIRECTION INPUT ;
    USE SIGNAL ;
    ANTENNAGATEAREA 0.159000 ;
    PORT
      LAYER met3 ;
        RECT 492.505 2.080 496.505 2.680 ;
    END
  END s_axi_araddr[27]
  PIN s_axi_araddr[28]
    DIRECTION INPUT ;
    USE SIGNAL ;
    ANTENNAGATEAREA 0.159000 ;
    PORT
      LAYER met3 ;
        RECT 0.000 473.320 4.000 473.920 ;
    END
  END s_axi_araddr[28]
  PIN s_axi_araddr[29]
    DIRECTION INPUT ;
    USE SIGNAL ;
    ANTENNAGATEAREA 0.213000 ;
    PORT
      LAYER met3 ;
        RECT 492.505 397.840 496.505 398.440 ;
    END
  END s_axi_araddr[29]
  PIN s_axi_araddr[2]
    DIRECTION INPUT ;
    USE SIGNAL ;
    ANTENNAGATEAREA 0.196500 ;
    PORT
      LAYER met3 ;
        RECT 0.000 208.120 4.000 208.720 ;
    END
  END s_axi_araddr[2]
  PIN s_axi_araddr[30]
    DIRECTION INPUT ;
    USE SIGNAL ;
    ANTENNAGATEAREA 0.213000 ;
    PORT
      LAYER met2 ;
        RECT 246.190 503.225 246.470 507.225 ;
    END
  END s_axi_araddr[30]
  PIN s_axi_araddr[31]
    DIRECTION INPUT ;
    USE SIGNAL ;
    ANTENNAGATEAREA 0.126000 ;
    PORT
      LAYER met2 ;
        RECT 165.690 503.225 165.970 507.225 ;
    END
  END s_axi_araddr[31]
  PIN s_axi_araddr[3]
    DIRECTION INPUT ;
    USE SIGNAL ;
    ANTENNAGATEAREA 0.196500 ;
    PORT
      LAYER met3 ;
        RECT 0.000 167.320 4.000 167.920 ;
    END
  END s_axi_araddr[3]
  PIN s_axi_araddr[4]
    DIRECTION INPUT ;
    USE SIGNAL ;
    ANTENNAGATEAREA 0.196500 ;
    PORT
      LAYER met3 ;
        RECT 0.000 330.520 4.000 331.120 ;
    END
  END s_axi_araddr[4]
  PIN s_axi_araddr[5]
    DIRECTION INPUT ;
    USE SIGNAL ;
    ANTENNAGATEAREA 0.213000 ;
    PORT
      LAYER met3 ;
        RECT 492.505 49.000 496.505 49.600 ;
    END
  END s_axi_araddr[5]
  PIN s_axi_araddr[6]
    DIRECTION INPUT ;
    USE SIGNAL ;
    ANTENNAGATEAREA 0.159000 ;
    PORT
      LAYER met2 ;
        RECT 131.190 503.225 131.470 507.225 ;
    END
  END s_axi_araddr[6]
  PIN s_axi_araddr[7]
    DIRECTION INPUT ;
    USE SIGNAL ;
    ANTENNAGATEAREA 0.196500 ;
    PORT
      LAYER met3 ;
        RECT 0.000 73.480 4.000 74.080 ;
    END
  END s_axi_araddr[7]
  PIN s_axi_araddr[8]
    DIRECTION INPUT ;
    USE SIGNAL ;
    ANTENNAGATEAREA 0.159000 ;
    PORT
      LAYER met3 ;
        RECT 492.505 393.760 496.505 394.360 ;
    END
  END s_axi_araddr[8]
  PIN s_axi_araddr[9]
    DIRECTION INPUT ;
    USE SIGNAL ;
    ANTENNAGATEAREA 0.196500 ;
    PORT
      LAYER met3 ;
        RECT 0.000 175.480 4.000 176.080 ;
    END
  END s_axi_araddr[9]
  PIN s_axi_aresetn
    DIRECTION INPUT ;
    USE SIGNAL ;
    ANTENNAGATEAREA 0.126000 ;
    PORT
      LAYER met2 ;
        RECT 333.590 503.225 333.870 507.225 ;
    END
  END s_axi_aresetn
  PIN s_axi_arready
    DIRECTION OUTPUT TRISTATE ;
    USE SIGNAL ;
    ANTENNADIFFAREA 0.795200 ;
    PORT
      LAYER met3 ;
        RECT 0.000 191.800 4.000 192.400 ;
    END
  END s_axi_arready
  PIN s_axi_arvalid
    DIRECTION INPUT ;
    USE SIGNAL ;
    ANTENNAGATEAREA 0.159000 ;
    PORT
      LAYER met2 ;
        RECT 448.590 503.225 448.870 507.225 ;
    END
  END s_axi_arvalid
  PIN s_axi_awaddr[0]
    DIRECTION INPUT ;
    USE SIGNAL ;
    ANTENNAGATEAREA 0.126000 ;
    PORT
      LAYER met2 ;
        RECT 455.490 503.225 455.770 507.225 ;
    END
  END s_axi_awaddr[0]
  PIN s_axi_awaddr[10]
    DIRECTION INPUT ;
    USE SIGNAL ;
    ANTENNAGATEAREA 0.196500 ;
    PORT
      LAYER met3 ;
        RECT 0.000 289.720 4.000 290.320 ;
    END
  END s_axi_awaddr[10]
  PIN s_axi_awaddr[11]
    DIRECTION INPUT ;
    USE SIGNAL ;
    ANTENNAGATEAREA 0.159000 ;
    PORT
      LAYER met2 ;
        RECT 276.090 503.225 276.370 507.225 ;
    END
  END s_axi_awaddr[11]
  PIN s_axi_awaddr[12]
    DIRECTION INPUT ;
    USE SIGNAL ;
    ANTENNAGATEAREA 0.196500 ;
    PORT
      LAYER met2 ;
        RECT 18.490 0.000 18.770 4.000 ;
    END
  END s_axi_awaddr[12]
  PIN s_axi_awaddr[13]
    DIRECTION INPUT ;
    USE SIGNAL ;
    ANTENNAGATEAREA 0.196500 ;
    PORT
      LAYER met2 ;
        RECT 6.990 0.000 7.270 4.000 ;
    END
  END s_axi_awaddr[13]
  PIN s_axi_awaddr[14]
    DIRECTION INPUT ;
    USE SIGNAL ;
    ANTENNAGATEAREA 0.196500 ;
    PORT
      LAYER met3 ;
        RECT 0.000 299.920 4.000 300.520 ;
    END
  END s_axi_awaddr[14]
  PIN s_axi_awaddr[15]
    DIRECTION INPUT ;
    USE SIGNAL ;
    ANTENNAGATEAREA 0.159000 ;
    PORT
      LAYER met2 ;
        RECT 315.190 0.000 315.470 4.000 ;
    END
  END s_axi_awaddr[15]
  PIN s_axi_awaddr[16]
    DIRECTION INPUT ;
    USE SIGNAL ;
    ANTENNAGATEAREA 0.213000 ;
    PORT
      LAYER met3 ;
        RECT 492.505 116.320 496.505 116.920 ;
    END
  END s_axi_awaddr[16]
  PIN s_axi_awaddr[17]
    DIRECTION INPUT ;
    USE SIGNAL ;
    ANTENNAGATEAREA 0.159000 ;
    PORT
      LAYER met2 ;
        RECT 326.690 503.225 326.970 507.225 ;
    END
  END s_axi_awaddr[17]
  PIN s_axi_awaddr[18]
    DIRECTION INPUT ;
    USE SIGNAL ;
    ANTENNAGATEAREA 0.213000 ;
    PORT
      LAYER met3 ;
        RECT 492.505 161.200 496.505 161.800 ;
    END
  END s_axi_awaddr[18]
  PIN s_axi_awaddr[19]
    DIRECTION INPUT ;
    USE SIGNAL ;
    ANTENNAGATEAREA 0.126000 ;
    PORT
      LAYER met3 ;
        RECT 0.000 485.560 4.000 486.160 ;
    END
  END s_axi_awaddr[19]
  PIN s_axi_awaddr[1]
    DIRECTION INPUT ;
    USE SIGNAL ;
    ANTENNAGATEAREA 0.196500 ;
    PORT
      LAYER met3 ;
        RECT 0.000 222.400 4.000 223.000 ;
    END
  END s_axi_awaddr[1]
  PIN s_axi_awaddr[20]
    DIRECTION INPUT ;
    USE SIGNAL ;
    ANTENNAGATEAREA 0.196500 ;
    PORT
      LAYER met3 ;
        RECT 0.000 42.880 4.000 43.480 ;
    END
  END s_axi_awaddr[20]
  PIN s_axi_awaddr[21]
    DIRECTION INPUT ;
    USE SIGNAL ;
    ANTENNAGATEAREA 0.196500 ;
    PORT
      LAYER met2 ;
        RECT 266.890 0.000 267.170 4.000 ;
    END
  END s_axi_awaddr[21]
  PIN s_axi_awaddr[22]
    DIRECTION INPUT ;
    USE SIGNAL ;
    ANTENNAGATEAREA 0.159000 ;
    PORT
      LAYER met2 ;
        RECT 262.290 503.225 262.570 507.225 ;
    END
  END s_axi_awaddr[22]
  PIN s_axi_awaddr[23]
    DIRECTION INPUT ;
    USE SIGNAL ;
    ANTENNAGATEAREA 0.159000 ;
    PORT
      LAYER met2 ;
        RECT 478.490 0.000 478.770 4.000 ;
    END
  END s_axi_awaddr[23]
  PIN s_axi_awaddr[24]
    DIRECTION INPUT ;
    USE SIGNAL ;
    ANTENNAGATEAREA 0.196500 ;
    PORT
      LAYER met2 ;
        RECT 227.790 0.000 228.070 4.000 ;
    END
  END s_axi_awaddr[24]
  PIN s_axi_awaddr[25]
    DIRECTION INPUT ;
    USE SIGNAL ;
    ANTENNAGATEAREA 0.213000 ;
    PORT
      LAYER met2 ;
        RECT 448.590 0.000 448.870 4.000 ;
    END
  END s_axi_awaddr[25]
  PIN s_axi_awaddr[26]
    DIRECTION INPUT ;
    USE SIGNAL ;
    ANTENNAGATEAREA 0.196500 ;
    PORT
      LAYER met3 ;
        RECT 0.000 165.280 4.000 165.880 ;
    END
  END s_axi_awaddr[26]
  PIN s_axi_awaddr[27]
    DIRECTION INPUT ;
    USE SIGNAL ;
    ANTENNAGATEAREA 0.213000 ;
    PORT
      LAYER met3 ;
        RECT 492.505 444.760 496.505 445.360 ;
    END
  END s_axi_awaddr[27]
  PIN s_axi_awaddr[28]
    DIRECTION INPUT ;
    USE SIGNAL ;
    ANTENNAGATEAREA 0.159000 ;
    PORT
      LAYER met2 ;
        RECT 460.090 0.000 460.370 4.000 ;
    END
  END s_axi_awaddr[28]
  PIN s_axi_awaddr[29]
    DIRECTION INPUT ;
    USE SIGNAL ;
    ANTENNAGATEAREA 0.126000 ;
    PORT
      LAYER met3 ;
        RECT 0.000 483.520 4.000 484.120 ;
    END
  END s_axi_awaddr[29]
  PIN s_axi_awaddr[2]
    DIRECTION INPUT ;
    USE SIGNAL ;
    ANTENNAGATEAREA 0.196500 ;
    PORT
      LAYER met3 ;
        RECT 492.505 81.640 496.505 82.240 ;
    END
  END s_axi_awaddr[2]
  PIN s_axi_awaddr[30]
    DIRECTION INPUT ;
    USE SIGNAL ;
    ANTENNAGATEAREA 0.159000 ;
    PORT
      LAYER met3 ;
        RECT 0.000 83.680 4.000 84.280 ;
    END
  END s_axi_awaddr[30]
  PIN s_axi_awaddr[31]
    DIRECTION INPUT ;
    USE SIGNAL ;
    ANTENNAGATEAREA 0.196500 ;
    PORT
      LAYER met2 ;
        RECT 184.090 503.225 184.370 507.225 ;
    END
  END s_axi_awaddr[31]
  PIN s_axi_awaddr[3]
    DIRECTION INPUT ;
    USE SIGNAL ;
    ANTENNAGATEAREA 0.196500 ;
    PORT
      LAYER met3 ;
        RECT 492.505 357.040 496.505 357.640 ;
    END
  END s_axi_awaddr[3]
  PIN s_axi_awaddr[4]
    DIRECTION INPUT ;
    USE SIGNAL ;
    ANTENNAGATEAREA 0.196500 ;
    PORT
      LAYER met3 ;
        RECT 0.000 161.200 4.000 161.800 ;
    END
  END s_axi_awaddr[4]
  PIN s_axi_awaddr[5]
    DIRECTION INPUT ;
    USE SIGNAL ;
    ANTENNAGATEAREA 0.196500 ;
    PORT
      LAYER met3 ;
        RECT 0.000 371.320 4.000 371.920 ;
    END
  END s_axi_awaddr[5]
  PIN s_axi_awaddr[6]
    DIRECTION INPUT ;
    USE SIGNAL ;
    ANTENNAGATEAREA 0.196500 ;
    PORT
      LAYER met3 ;
        RECT 492.505 136.720 496.505 137.320 ;
    END
  END s_axi_awaddr[6]
  PIN s_axi_awaddr[7]
    DIRECTION INPUT ;
    USE SIGNAL ;
    ANTENNAGATEAREA 0.126000 ;
    PORT
      LAYER met2 ;
        RECT 142.690 503.225 142.970 507.225 ;
    END
  END s_axi_awaddr[7]
  PIN s_axi_awaddr[8]
    DIRECTION INPUT ;
    USE SIGNAL ;
    ANTENNAGATEAREA 0.196500 ;
    PORT
      LAYER met3 ;
        RECT 492.505 44.920 496.505 45.520 ;
    END
  END s_axi_awaddr[8]
  PIN s_axi_awaddr[9]
    DIRECTION INPUT ;
    USE SIGNAL ;
    ANTENNAGATEAREA 0.196500 ;
    PORT
      LAYER met3 ;
        RECT 0.000 454.960 4.000 455.560 ;
    END
  END s_axi_awaddr[9]
  PIN s_axi_awready
    DIRECTION OUTPUT TRISTATE ;
    USE SIGNAL ;
    ANTENNADIFFAREA 0.795200 ;
    PORT
      LAYER met2 ;
        RECT 75.990 0.000 76.270 4.000 ;
    END
  END s_axi_awready
  PIN s_axi_awvalid
    DIRECTION INPUT ;
    USE SIGNAL ;
    ANTENNAGATEAREA 0.159000 ;
    PORT
      LAYER met3 ;
        RECT 492.505 342.760 496.505 343.360 ;
    END
  END s_axi_awvalid
  PIN s_axi_bready
    DIRECTION INPUT ;
    USE SIGNAL ;
    ANTENNAGATEAREA 0.213000 ;
    PORT
      LAYER met2 ;
        RECT 331.290 0.000 331.570 4.000 ;
    END
  END s_axi_bready
  PIN s_axi_bresp[0]
    DIRECTION OUTPUT TRISTATE ;
    USE SIGNAL ;
    PORT
      LAYER met3 ;
        RECT 492.505 420.280 496.505 420.880 ;
    END
  END s_axi_bresp[0]
  PIN s_axi_bresp[1]
    DIRECTION OUTPUT TRISTATE ;
    USE SIGNAL ;
    ANTENNADIFFAREA 0.795200 ;
    PORT
      LAYER met2 ;
        RECT 147.290 0.000 147.570 4.000 ;
    END
  END s_axi_bresp[1]
  PIN s_axi_bvalid
    DIRECTION OUTPUT TRISTATE ;
    USE SIGNAL ;
    ANTENNADIFFAREA 0.795200 ;
    PORT
      LAYER met3 ;
        RECT 0.000 314.200 4.000 314.800 ;
    END
  END s_axi_bvalid
  PIN s_axi_rbusy
    DIRECTION OUTPUT TRISTATE ;
    USE SIGNAL ;
    ANTENNADIFFAREA 0.795200 ;
    PORT
      LAYER met3 ;
        RECT 0.000 493.720 4.000 494.320 ;
    END
  END s_axi_rbusy
  PIN s_axi_rdata[0]
    DIRECTION OUTPUT TRISTATE ;
    USE SIGNAL ;
    ANTENNADIFFAREA 0.795200 ;
    PORT
      LAYER met2 ;
        RECT 315.190 503.225 315.470 507.225 ;
    END
  END s_axi_rdata[0]
  PIN s_axi_rdata[10]
    DIRECTION OUTPUT TRISTATE ;
    USE SIGNAL ;
    ANTENNADIFFAREA 0.445500 ;
    PORT
      LAYER met3 ;
        RECT 492.505 471.280 496.505 471.880 ;
    END
  END s_axi_rdata[10]
  PIN s_axi_rdata[11]
    DIRECTION OUTPUT TRISTATE ;
    USE SIGNAL ;
    ANTENNADIFFAREA 0.795200 ;
    PORT
      LAYER met3 ;
        RECT 0.000 475.360 4.000 475.960 ;
    END
  END s_axi_rdata[11]
  PIN s_axi_rdata[12]
    DIRECTION OUTPUT TRISTATE ;
    USE SIGNAL ;
    ANTENNADIFFAREA 0.795200 ;
    PORT
      LAYER met3 ;
        RECT 0.000 16.360 4.000 16.960 ;
    END
  END s_axi_rdata[12]
  PIN s_axi_rdata[13]
    DIRECTION OUTPUT TRISTATE ;
    USE SIGNAL ;
    ANTENNADIFFAREA 0.795200 ;
    PORT
      LAYER met3 ;
        RECT 492.505 167.320 496.505 167.920 ;
    END
  END s_axi_rdata[13]
  PIN s_axi_rdata[14]
    DIRECTION OUTPUT TRISTATE ;
    USE SIGNAL ;
    ANTENNADIFFAREA 0.795200 ;
    PORT
      LAYER met3 ;
        RECT 0.000 444.760 4.000 445.360 ;
    END
  END s_axi_rdata[14]
  PIN s_axi_rdata[15]
    DIRECTION OUTPUT TRISTATE ;
    USE SIGNAL ;
    ANTENNADIFFAREA 0.445500 ;
    PORT
      LAYER met3 ;
        RECT 492.505 250.960 496.505 251.560 ;
    END
  END s_axi_rdata[15]
  PIN s_axi_rdata[16]
    DIRECTION OUTPUT TRISTATE ;
    USE SIGNAL ;
    ANTENNADIFFAREA 0.795200 ;
    PORT
      LAYER met3 ;
        RECT 0.000 226.480 4.000 227.080 ;
    END
  END s_axi_rdata[16]
  PIN s_axi_rdata[17]
    DIRECTION OUTPUT TRISTATE ;
    USE SIGNAL ;
    ANTENNADIFFAREA 0.795200 ;
    PORT
      LAYER met2 ;
        RECT 89.790 503.225 90.070 507.225 ;
    END
  END s_axi_rdata[17]
  PIN s_axi_rdata[18]
    DIRECTION OUTPUT TRISTATE ;
    USE SIGNAL ;
    ANTENNADIFFAREA 0.795200 ;
    PORT
      LAYER met3 ;
        RECT 0.000 6.160 4.000 6.760 ;
    END
  END s_axi_rdata[18]
  PIN s_axi_rdata[19]
    DIRECTION OUTPUT TRISTATE ;
    USE SIGNAL ;
    ANTENNADIFFAREA 0.795200 ;
    PORT
      LAYER met2 ;
        RECT 52.990 0.000 53.270 4.000 ;
    END
  END s_axi_rdata[19]
  PIN s_axi_rdata[1]
    DIRECTION OUTPUT TRISTATE ;
    USE SIGNAL ;
    ANTENNADIFFAREA 0.795200 ;
    PORT
      LAYER met3 ;
        RECT 0.000 212.200 4.000 212.800 ;
    END
  END s_axi_rdata[1]
  PIN s_axi_rdata[20]
    DIRECTION OUTPUT TRISTATE ;
    USE SIGNAL ;
    ANTENNADIFFAREA 0.445500 ;
    PORT
      LAYER met3 ;
        RECT 492.505 446.800 496.505 447.400 ;
    END
  END s_axi_rdata[20]
  PIN s_axi_rdata[21]
    DIRECTION OUTPUT TRISTATE ;
    USE SIGNAL ;
    ANTENNADIFFAREA 0.445500 ;
    PORT
      LAYER met3 ;
        RECT 492.505 418.240 496.505 418.840 ;
    END
  END s_axi_rdata[21]
  PIN s_axi_rdata[22]
    DIRECTION OUTPUT TRISTATE ;
    USE SIGNAL ;
    ANTENNADIFFAREA 0.795200 ;
    PORT
      LAYER met3 ;
        RECT 0.000 97.960 4.000 98.560 ;
    END
  END s_axi_rdata[22]
  PIN s_axi_rdata[23]
    DIRECTION OUTPUT TRISTATE ;
    USE SIGNAL ;
    ANTENNADIFFAREA 0.795200 ;
    PORT
      LAYER met3 ;
        RECT 492.505 377.440 496.505 378.040 ;
    END
  END s_axi_rdata[23]
  PIN s_axi_rdata[24]
    DIRECTION OUTPUT TRISTATE ;
    USE SIGNAL ;
    ANTENNADIFFAREA 0.795200 ;
    PORT
      LAYER met3 ;
        RECT 492.505 228.520 496.505 229.120 ;
    END
  END s_axi_rdata[24]
  PIN s_axi_rdata[25]
    DIRECTION OUTPUT TRISTATE ;
    USE SIGNAL ;
    ANTENNADIFFAREA 0.795200 ;
    PORT
      LAYER met3 ;
        RECT 492.505 53.080 496.505 53.680 ;
    END
  END s_axi_rdata[25]
  PIN s_axi_rdata[26]
    DIRECTION OUTPUT TRISTATE ;
    USE SIGNAL ;
    ANTENNADIFFAREA 0.795200 ;
    PORT
      LAYER met2 ;
        RECT 211.690 503.225 211.970 507.225 ;
    END
  END s_axi_rdata[26]
  PIN s_axi_rdata[27]
    DIRECTION OUTPUT TRISTATE ;
    USE SIGNAL ;
    ANTENNADIFFAREA 0.795200 ;
    PORT
      LAYER met2 ;
        RECT 374.990 503.225 375.270 507.225 ;
    END
  END s_axi_rdata[27]
  PIN s_axi_rdata[28]
    DIRECTION OUTPUT TRISTATE ;
    USE SIGNAL ;
    ANTENNADIFFAREA 0.795200 ;
    PORT
      LAYER met3 ;
        RECT 0.000 28.600 4.000 29.200 ;
    END
  END s_axi_rdata[28]
  PIN s_axi_rdata[29]
    DIRECTION OUTPUT TRISTATE ;
    USE SIGNAL ;
    ANTENNADIFFAREA 0.795200 ;
    PORT
      LAYER met2 ;
        RECT 464.690 0.000 464.970 4.000 ;
    END
  END s_axi_rdata[29]
  PIN s_axi_rdata[2]
    DIRECTION OUTPUT TRISTATE ;
    USE SIGNAL ;
    ANTENNADIFFAREA 0.795200 ;
    PORT
      LAYER met3 ;
        RECT 492.505 183.640 496.505 184.240 ;
    END
  END s_axi_rdata[2]
  PIN s_axi_rdata[30]
    DIRECTION OUTPUT TRISTATE ;
    USE SIGNAL ;
    ANTENNADIFFAREA 0.795200 ;
    PORT
      LAYER met3 ;
        RECT 0.000 202.000 4.000 202.600 ;
    END
  END s_axi_rdata[30]
  PIN s_axi_rdata[31]
    DIRECTION OUTPUT TRISTATE ;
    USE SIGNAL ;
    ANTENNADIFFAREA 0.795200 ;
    PORT
      LAYER met2 ;
        RECT 310.590 0.000 310.870 4.000 ;
    END
  END s_axi_rdata[31]
  PIN s_axi_rdata[3]
    DIRECTION OUTPUT TRISTATE ;
    USE SIGNAL ;
    ANTENNADIFFAREA 0.795200 ;
    PORT
      LAYER met2 ;
        RECT 59.890 0.000 60.170 4.000 ;
    END
  END s_axi_rdata[3]
  PIN s_axi_rdata[4]
    DIRECTION OUTPUT TRISTATE ;
    USE SIGNAL ;
    ANTENNADIFFAREA 0.795200 ;
    PORT
      LAYER met2 ;
        RECT 48.390 503.225 48.670 507.225 ;
    END
  END s_axi_rdata[4]
  PIN s_axi_rdata[5]
    DIRECTION OUTPUT TRISTATE ;
    USE SIGNAL ;
    ANTENNADIFFAREA 0.795200 ;
    PORT
      LAYER met3 ;
        RECT 492.505 359.080 496.505 359.680 ;
    END
  END s_axi_rdata[5]
  PIN s_axi_rdata[6]
    DIRECTION OUTPUT TRISTATE ;
    USE SIGNAL ;
    ANTENNADIFFAREA 0.795200 ;
    PORT
      LAYER met2 ;
        RECT 450.890 503.225 451.170 507.225 ;
    END
  END s_axi_rdata[6]
  PIN s_axi_rdata[7]
    DIRECTION OUTPUT TRISTATE ;
    USE SIGNAL ;
    ANTENNADIFFAREA 0.795200 ;
    PORT
      LAYER met2 ;
        RECT 220.890 0.000 221.170 4.000 ;
    END
  END s_axi_rdata[7]
  PIN s_axi_rdata[8]
    DIRECTION OUTPUT TRISTATE ;
    USE SIGNAL ;
    ANTENNADIFFAREA 0.795200 ;
    PORT
      LAYER met2 ;
        RECT 310.590 503.225 310.870 507.225 ;
    END
  END s_axi_rdata[8]
  PIN s_axi_rdata[9]
    DIRECTION OUTPUT TRISTATE ;
    USE SIGNAL ;
    ANTENNADIFFAREA 0.795200 ;
    PORT
      LAYER met3 ;
        RECT 492.505 275.440 496.505 276.040 ;
    END
  END s_axi_rdata[9]
  PIN s_axi_rdata_return[0]
    DIRECTION OUTPUT TRISTATE ;
    USE SIGNAL ;
    ANTENNADIFFAREA 0.795200 ;
    PORT
      LAYER met2 ;
        RECT 441.690 0.000 441.970 4.000 ;
    END
  END s_axi_rdata_return[0]
  PIN s_axi_rdata_return[10]
    DIRECTION OUTPUT TRISTATE ;
    USE SIGNAL ;
    ANTENNADIFFAREA 0.795200 ;
    PORT
      LAYER met2 ;
        RECT 303.690 503.225 303.970 507.225 ;
    END
  END s_axi_rdata_return[10]
  PIN s_axi_rdata_return[11]
    DIRECTION OUTPUT TRISTATE ;
    USE SIGNAL ;
    ANTENNADIFFAREA 0.795200 ;
    PORT
      LAYER met2 ;
        RECT 425.590 0.000 425.870 4.000 ;
    END
  END s_axi_rdata_return[11]
  PIN s_axi_rdata_return[12]
    DIRECTION OUTPUT TRISTATE ;
    USE SIGNAL ;
    ANTENNADIFFAREA 0.795200 ;
    PORT
      LAYER met2 ;
        RECT 177.190 0.000 177.470 4.000 ;
    END
  END s_axi_rdata_return[12]
  PIN s_axi_rdata_return[13]
    DIRECTION OUTPUT TRISTATE ;
    USE SIGNAL ;
    ANTENNADIFFAREA 0.795200 ;
    PORT
      LAYER met2 ;
        RECT 25.390 0.000 25.670 4.000 ;
    END
  END s_axi_rdata_return[13]
  PIN s_axi_rdata_return[14]
    DIRECTION OUTPUT TRISTATE ;
    USE SIGNAL ;
    ANTENNADIFFAREA 0.445500 ;
    PORT
      LAYER met3 ;
        RECT 492.505 59.200 496.505 59.800 ;
    END
  END s_axi_rdata_return[14]
  PIN s_axi_rdata_return[15]
    DIRECTION OUTPUT TRISTATE ;
    USE SIGNAL ;
    ANTENNADIFFAREA 0.795200 ;
    PORT
      LAYER met3 ;
        RECT 0.000 157.120 4.000 157.720 ;
    END
  END s_axi_rdata_return[15]
  PIN s_axi_rdata_return[16]
    DIRECTION OUTPUT TRISTATE ;
    USE SIGNAL ;
    ANTENNADIFFAREA 0.795200 ;
    PORT
      LAYER met2 ;
        RECT 55.290 503.225 55.570 507.225 ;
    END
  END s_axi_rdata_return[16]
  PIN s_axi_rdata_return[17]
    DIRECTION OUTPUT TRISTATE ;
    USE SIGNAL ;
    ANTENNADIFFAREA 0.795200 ;
    PORT
      LAYER met3 ;
        RECT 492.505 495.760 496.505 496.360 ;
    END
  END s_axi_rdata_return[17]
  PIN s_axi_rdata_return[18]
    DIRECTION OUTPUT TRISTATE ;
    USE SIGNAL ;
    ANTENNADIFFAREA 0.795200 ;
    PORT
      LAYER met3 ;
        RECT 0.000 285.640 4.000 286.240 ;
    END
  END s_axi_rdata_return[18]
  PIN s_axi_rdata_return[19]
    DIRECTION OUTPUT TRISTATE ;
    USE SIGNAL ;
    ANTENNADIFFAREA 0.795200 ;
    PORT
      LAYER met3 ;
        RECT 0.000 324.400 4.000 325.000 ;
    END
  END s_axi_rdata_return[19]
  PIN s_axi_rdata_return[1]
    DIRECTION OUTPUT TRISTATE ;
    USE SIGNAL ;
    ANTENNADIFFAREA 0.795200 ;
    PORT
      LAYER met3 ;
        RECT 0.000 310.120 4.000 310.720 ;
    END
  END s_axi_rdata_return[1]
  PIN s_axi_rdata_return[20]
    DIRECTION OUTPUT TRISTATE ;
    USE SIGNAL ;
    ANTENNADIFFAREA 0.795200 ;
    PORT
      LAYER met2 ;
        RECT 20.790 0.000 21.070 4.000 ;
    END
  END s_axi_rdata_return[20]
  PIN s_axi_rdata_return[21]
    DIRECTION OUTPUT TRISTATE ;
    USE SIGNAL ;
    ANTENNADIFFAREA 0.795200 ;
    PORT
      LAYER met2 ;
        RECT 121.990 0.000 122.270 4.000 ;
    END
  END s_axi_rdata_return[21]
  PIN s_axi_rdata_return[22]
    DIRECTION OUTPUT TRISTATE ;
    USE SIGNAL ;
    ANTENNADIFFAREA 0.795200 ;
    PORT
      LAYER met3 ;
        RECT 492.505 316.240 496.505 316.840 ;
    END
  END s_axi_rdata_return[22]
  PIN s_axi_rdata_return[23]
    DIRECTION OUTPUT TRISTATE ;
    USE SIGNAL ;
    ANTENNADIFFAREA 0.795200 ;
    PORT
      LAYER met3 ;
        RECT 0.000 36.760 4.000 37.360 ;
    END
  END s_axi_rdata_return[23]
  PIN s_axi_rdata_return[24]
    DIRECTION OUTPUT TRISTATE ;
    USE SIGNAL ;
    ANTENNADIFFAREA 0.795200 ;
    PORT
      LAYER met2 ;
        RECT 269.190 503.225 269.470 507.225 ;
    END
  END s_axi_rdata_return[24]
  PIN s_axi_rdata_return[25]
    DIRECTION OUTPUT TRISTATE ;
    USE SIGNAL ;
    ANTENNADIFFAREA 0.795200 ;
    PORT
      LAYER met2 ;
        RECT 407.190 503.225 407.470 507.225 ;
    END
  END s_axi_rdata_return[25]
  PIN s_axi_rdata_return[26]
    DIRECTION OUTPUT TRISTATE ;
    USE SIGNAL ;
    ANTENNADIFFAREA 0.795200 ;
    PORT
      LAYER met3 ;
        RECT 0.000 438.640 4.000 439.240 ;
    END
  END s_axi_rdata_return[26]
  PIN s_axi_rdata_return[27]
    DIRECTION OUTPUT TRISTATE ;
    USE SIGNAL ;
    ANTENNADIFFAREA 0.795200 ;
    PORT
      LAYER met2 ;
        RECT 87.490 0.000 87.770 4.000 ;
    END
  END s_axi_rdata_return[27]
  PIN s_axi_rdata_return[28]
    DIRECTION OUTPUT TRISTATE ;
    USE SIGNAL ;
    ANTENNADIFFAREA 0.795200 ;
    PORT
      LAYER met3 ;
        RECT 492.505 352.960 496.505 353.560 ;
    END
  END s_axi_rdata_return[28]
  PIN s_axi_rdata_return[29]
    DIRECTION OUTPUT TRISTATE ;
    USE SIGNAL ;
    ANTENNADIFFAREA 0.795200 ;
    PORT
      LAYER met2 ;
        RECT 425.590 503.225 425.870 507.225 ;
    END
  END s_axi_rdata_return[29]
  PIN s_axi_rdata_return[2]
    DIRECTION OUTPUT TRISTATE ;
    USE SIGNAL ;
    ANTENNADIFFAREA 0.795200 ;
    PORT
      LAYER met3 ;
        RECT 0.000 216.280 4.000 216.880 ;
    END
  END s_axi_rdata_return[2]
  PIN s_axi_rdata_return[30]
    DIRECTION OUTPUT TRISTATE ;
    USE SIGNAL ;
    ANTENNADIFFAREA 0.445500 ;
    PORT
      LAYER met3 ;
        RECT 492.505 438.640 496.505 439.240 ;
    END
  END s_axi_rdata_return[30]
  PIN s_axi_rdata_return[31]
    DIRECTION OUTPUT TRISTATE ;
    USE SIGNAL ;
    ANTENNADIFFAREA 0.795200 ;
    PORT
      LAYER met3 ;
        RECT 492.505 214.240 496.505 214.840 ;
    END
  END s_axi_rdata_return[31]
  PIN s_axi_rdata_return[3]
    DIRECTION OUTPUT TRISTATE ;
    USE SIGNAL ;
    ANTENNADIFFAREA 0.795200 ;
    PORT
      LAYER met2 ;
        RECT 384.190 0.000 384.470 4.000 ;
    END
  END s_axi_rdata_return[3]
  PIN s_axi_rdata_return[4]
    DIRECTION OUTPUT TRISTATE ;
    USE SIGNAL ;
    ANTENNADIFFAREA 0.795200 ;
    PORT
      LAYER met2 ;
        RECT 363.490 503.225 363.770 507.225 ;
    END
  END s_axi_rdata_return[4]
  PIN s_axi_rdata_return[5]
    DIRECTION OUTPUT TRISTATE ;
    USE SIGNAL ;
    ANTENNADIFFAREA 0.795200 ;
    PORT
      LAYER met2 ;
        RECT 36.890 503.225 37.170 507.225 ;
    END
  END s_axi_rdata_return[5]
  PIN s_axi_rdata_return[6]
    DIRECTION OUTPUT TRISTATE ;
    USE SIGNAL ;
    ANTENNADIFFAREA 0.795200 ;
    PORT
      LAYER met2 ;
        RECT 174.890 0.000 175.170 4.000 ;
    END
  END s_axi_rdata_return[6]
  PIN s_axi_rdata_return[7]
    DIRECTION OUTPUT TRISTATE ;
    USE SIGNAL ;
    ANTENNADIFFAREA 0.445500 ;
    PORT
      LAYER met3 ;
        RECT 492.505 346.840 496.505 347.440 ;
    END
  END s_axi_rdata_return[7]
  PIN s_axi_rdata_return[8]
    DIRECTION OUTPUT TRISTATE ;
    USE SIGNAL ;
    ANTENNADIFFAREA 0.795200 ;
    PORT
      LAYER met2 ;
        RECT 453.190 0.000 453.470 4.000 ;
    END
  END s_axi_rdata_return[8]
  PIN s_axi_rdata_return[9]
    DIRECTION OUTPUT TRISTATE ;
    USE SIGNAL ;
    ANTENNADIFFAREA 0.795200 ;
    PORT
      LAYER met3 ;
        RECT 492.505 193.840 496.505 194.440 ;
    END
  END s_axi_rdata_return[9]
  PIN s_axi_rready
    DIRECTION INPUT ;
    USE SIGNAL ;
    ANTENNAGATEAREA 0.213000 ;
    PORT
      LAYER met3 ;
        RECT 0.000 197.920 4.000 198.520 ;
    END
  END s_axi_rready
  PIN s_axi_rresp[0]
    DIRECTION OUTPUT TRISTATE ;
    USE SIGNAL ;
    PORT
      LAYER met3 ;
        RECT 492.505 69.400 496.505 70.000 ;
    END
  END s_axi_rresp[0]
  PIN s_axi_rresp[1]
    DIRECTION OUTPUT TRISTATE ;
    USE SIGNAL ;
    PORT
      LAYER met2 ;
        RECT 89.790 0.000 90.070 4.000 ;
    END
  END s_axi_rresp[1]
  PIN s_axi_rvalid
    DIRECTION OUTPUT TRISTATE ;
    USE SIGNAL ;
    ANTENNADIFFAREA 0.795200 ;
    PORT
      LAYER met2 ;
        RECT 273.790 0.000 274.070 4.000 ;
    END
  END s_axi_rvalid
  PIN s_axi_wdata[0]
    DIRECTION INPUT ;
    USE SIGNAL ;
    ANTENNAGATEAREA 0.196500 ;
    PORT
      LAYER met3 ;
        RECT 492.505 259.120 496.505 259.720 ;
    END
  END s_axi_wdata[0]
  PIN s_axi_wdata[10]
    DIRECTION INPUT ;
    USE SIGNAL ;
    ANTENNAGATEAREA 0.213000 ;
    PORT
      LAYER met2 ;
        RECT 351.990 503.225 352.270 507.225 ;
    END
  END s_axi_wdata[10]
  PIN s_axi_wdata[11]
    DIRECTION INPUT ;
    USE SIGNAL ;
    ANTENNAGATEAREA 0.213000 ;
    PORT
      LAYER met3 ;
        RECT 492.505 481.480 496.505 482.080 ;
    END
  END s_axi_wdata[11]
  PIN s_axi_wdata[12]
    DIRECTION INPUT ;
    USE SIGNAL ;
    ANTENNAGATEAREA 0.196500 ;
    PORT
      LAYER met3 ;
        RECT 492.505 71.440 496.505 72.040 ;
    END
  END s_axi_wdata[12]
  PIN s_axi_wdata[13]
    DIRECTION INPUT ;
    USE SIGNAL ;
    ANTENNAGATEAREA 0.159000 ;
    PORT
      LAYER met2 ;
        RECT 43.790 0.000 44.070 4.000 ;
    END
  END s_axi_wdata[13]
  PIN s_axi_wdata[14]
    DIRECTION INPUT ;
    USE SIGNAL ;
    ANTENNAGATEAREA 0.196500 ;
    PORT
      LAYER met3 ;
        RECT 492.505 322.360 496.505 322.960 ;
    END
  END s_axi_wdata[14]
  PIN s_axi_wdata[15]
    DIRECTION INPUT ;
    USE SIGNAL ;
    ANTENNAGATEAREA 0.159000 ;
    PORT
      LAYER met2 ;
        RECT 9.290 0.000 9.570 4.000 ;
    END
  END s_axi_wdata[15]
  PIN s_axi_wdata[16]
    DIRECTION INPUT ;
    USE SIGNAL ;
    ANTENNAGATEAREA 0.159000 ;
    PORT
      LAYER met3 ;
        RECT 492.505 491.680 496.505 492.280 ;
    END
  END s_axi_wdata[16]
  PIN s_axi_wdata[17]
    DIRECTION INPUT ;
    USE SIGNAL ;
    ANTENNAGATEAREA 0.159000 ;
    PORT
      LAYER met2 ;
        RECT 338.190 503.225 338.470 507.225 ;
    END
  END s_axi_wdata[17]
  PIN s_axi_wdata[18]
    DIRECTION INPUT ;
    USE SIGNAL ;
    ANTENNAGATEAREA 0.196500 ;
    PORT
      LAYER met3 ;
        RECT 492.505 100.000 496.505 100.600 ;
    END
  END s_axi_wdata[18]
  PIN s_axi_wdata[19]
    DIRECTION INPUT ;
    USE SIGNAL ;
    ANTENNAGATEAREA 0.196500 ;
    PORT
      LAYER met3 ;
        RECT 0.000 57.160 4.000 57.760 ;
    END
  END s_axi_wdata[19]
  PIN s_axi_wdata[1]
    DIRECTION INPUT ;
    USE SIGNAL ;
    ANTENNAGATEAREA 0.159000 ;
    PORT
      LAYER met2 ;
        RECT 368.090 0.000 368.370 4.000 ;
    END
  END s_axi_wdata[1]
  PIN s_axi_wdata[20]
    DIRECTION INPUT ;
    USE SIGNAL ;
    ANTENNAGATEAREA 0.196500 ;
    PORT
      LAYER met3 ;
        RECT 0.000 114.280 4.000 114.880 ;
    END
  END s_axi_wdata[20]
  PIN s_axi_wdata[21]
    DIRECTION INPUT ;
    USE SIGNAL ;
    ANTENNAGATEAREA 0.196500 ;
    PORT
      LAYER met2 ;
        RECT 365.790 0.000 366.070 4.000 ;
    END
  END s_axi_wdata[21]
  PIN s_axi_wdata[22]
    DIRECTION INPUT ;
    USE SIGNAL ;
    ANTENNAGATEAREA 0.196500 ;
    PORT
      LAYER met2 ;
        RECT 0.090 0.000 0.370 4.000 ;
    END
  END s_axi_wdata[22]
  PIN s_axi_wdata[23]
    DIRECTION INPUT ;
    USE SIGNAL ;
    ANTENNAGATEAREA 0.196500 ;
    PORT
      LAYER met2 ;
        RECT 430.190 0.000 430.470 4.000 ;
    END
  END s_axi_wdata[23]
  PIN s_axi_wdata[24]
    DIRECTION INPUT ;
    USE SIGNAL ;
    ANTENNAGATEAREA 0.196500 ;
    PORT
      LAYER met3 ;
        RECT 0.000 195.880 4.000 196.480 ;
    END
  END s_axi_wdata[24]
  PIN s_axi_wdata[25]
    DIRECTION INPUT ;
    USE SIGNAL ;
    ANTENNAGATEAREA 0.213000 ;
    PORT
      LAYER met3 ;
        RECT 0.000 383.560 4.000 384.160 ;
    END
  END s_axi_wdata[25]
  PIN s_axi_wdata[26]
    DIRECTION INPUT ;
    USE SIGNAL ;
    ANTENNAGATEAREA 0.213000 ;
    PORT
      LAYER met2 ;
        RECT 85.190 503.225 85.470 507.225 ;
    END
  END s_axi_wdata[26]
  PIN s_axi_wdata[27]
    DIRECTION INPUT ;
    USE SIGNAL ;
    ANTENNAGATEAREA 0.213000 ;
    PORT
      LAYER met3 ;
        RECT 0.000 130.600 4.000 131.200 ;
    END
  END s_axi_wdata[27]
  PIN s_axi_wdata[28]
    DIRECTION INPUT ;
    USE SIGNAL ;
    ANTENNAGATEAREA 0.196500 ;
    PORT
      LAYER met2 ;
        RECT 112.790 0.000 113.070 4.000 ;
    END
  END s_axi_wdata[28]
  PIN s_axi_wdata[29]
    DIRECTION INPUT ;
    USE SIGNAL ;
    ANTENNAGATEAREA 0.196500 ;
    PORT
      LAYER met2 ;
        RECT 41.490 0.000 41.770 4.000 ;
    END
  END s_axi_wdata[29]
  PIN s_axi_wdata[2]
    DIRECTION INPUT ;
    USE SIGNAL ;
    ANTENNAGATEAREA 0.196500 ;
    PORT
      LAYER met2 ;
        RECT 223.190 503.225 223.470 507.225 ;
    END
  END s_axi_wdata[2]
  PIN s_axi_wdata[30]
    DIRECTION INPUT ;
    USE SIGNAL ;
    ANTENNAGATEAREA 0.213000 ;
    PORT
      LAYER met2 ;
        RECT 101.290 503.225 101.570 507.225 ;
    END
  END s_axi_wdata[30]
  PIN s_axi_wdata[31]
    DIRECTION INPUT ;
    USE SIGNAL ;
    ANTENNAGATEAREA 0.196500 ;
    PORT
      LAYER met2 ;
        RECT 292.190 0.000 292.470 4.000 ;
    END
  END s_axi_wdata[31]
  PIN s_axi_wdata[3]
    DIRECTION INPUT ;
    USE SIGNAL ;
    ANTENNAGATEAREA 0.196500 ;
    PORT
      LAYER met2 ;
        RECT 317.490 503.225 317.770 507.225 ;
    END
  END s_axi_wdata[3]
  PIN s_axi_wdata[4]
    DIRECTION INPUT ;
    USE SIGNAL ;
    ANTENNAGATEAREA 0.213000 ;
    PORT
      LAYER met3 ;
        RECT 492.505 173.440 496.505 174.040 ;
    END
  END s_axi_wdata[4]
  PIN s_axi_wdata[5]
    DIRECTION INPUT ;
    USE SIGNAL ;
    ANTENNAGATEAREA 0.159000 ;
    PORT
      LAYER met3 ;
        RECT 0.000 295.840 4.000 296.440 ;
    END
  END s_axi_wdata[5]
  PIN s_axi_wdata[6]
    DIRECTION INPUT ;
    USE SIGNAL ;
    ANTENNAGATEAREA 0.196500 ;
    PORT
      LAYER met3 ;
        RECT 492.505 408.040 496.505 408.640 ;
    END
  END s_axi_wdata[6]
  PIN s_axi_wdata[7]
    DIRECTION INPUT ;
    USE SIGNAL ;
    ANTENNAGATEAREA 0.213000 ;
    PORT
      LAYER met2 ;
        RECT 117.390 0.000 117.670 4.000 ;
    END
  END s_axi_wdata[7]
  PIN s_axi_wdata[8]
    DIRECTION INPUT ;
    USE SIGNAL ;
    ANTENNAGATEAREA 0.196500 ;
    PORT
      LAYER met2 ;
        RECT 204.790 0.000 205.070 4.000 ;
    END
  END s_axi_wdata[8]
  PIN s_axi_wdata[9]
    DIRECTION INPUT ;
    USE SIGNAL ;
    ANTENNAGATEAREA 0.196500 ;
    PORT
      LAYER met2 ;
        RECT 322.090 0.000 322.370 4.000 ;
    END
  END s_axi_wdata[9]
  PIN s_axi_wready
    DIRECTION OUTPUT TRISTATE ;
    USE SIGNAL ;
    ANTENNADIFFAREA 0.445500 ;
    PORT
      LAYER met3 ;
        RECT 492.505 389.680 496.505 390.280 ;
    END
  END s_axi_wready
  PIN s_axi_wstrb[0]
    DIRECTION INPUT ;
    USE SIGNAL ;
    ANTENNAGATEAREA 0.213000 ;
    PORT
      LAYER met2 ;
        RECT 326.690 0.000 326.970 4.000 ;
    END
  END s_axi_wstrb[0]
  PIN s_axi_wstrb[1]
    DIRECTION INPUT ;
    USE SIGNAL ;
    ANTENNAGATEAREA 0.196500 ;
    PORT
      LAYER met2 ;
        RECT 305.990 503.225 306.270 507.225 ;
    END
  END s_axi_wstrb[1]
  PIN s_axi_wstrb[2]
    DIRECTION INPUT ;
    USE SIGNAL ;
    ANTENNAGATEAREA 0.196500 ;
    PORT
      LAYER met2 ;
        RECT 299.090 503.225 299.370 507.225 ;
    END
  END s_axi_wstrb[2]
  PIN s_axi_wstrb[3]
    DIRECTION INPUT ;
    USE SIGNAL ;
    ANTENNAGATEAREA 0.159000 ;
    PORT
      LAYER met3 ;
        RECT 0.000 432.520 4.000 433.120 ;
    END
  END s_axi_wstrb[3]
  PIN s_axi_wvalid
    DIRECTION INPUT ;
    USE SIGNAL ;
    ANTENNAGATEAREA 0.159000 ;
    PORT
      LAYER met2 ;
        RECT 13.890 503.225 14.170 507.225 ;
    END
  END s_axi_wvalid
  PIN sr_axi_slave_state[0]
    DIRECTION OUTPUT TRISTATE ;
    USE SIGNAL ;
    ANTENNADIFFAREA 0.795200 ;
    PORT
      LAYER met2 ;
        RECT 388.790 0.000 389.070 4.000 ;
    END
  END sr_axi_slave_state[0]
  PIN sr_axi_slave_state[1]
    DIRECTION OUTPUT TRISTATE ;
    USE SIGNAL ;
    ANTENNADIFFAREA 0.795200 ;
    PORT
      LAYER met3 ;
        RECT 0.000 100.000 4.000 100.600 ;
    END
  END sr_axi_slave_state[1]
  PIN sw_axi_slave_state[0]
    DIRECTION OUTPUT TRISTATE ;
    USE SIGNAL ;
    ANTENNADIFFAREA 0.795200 ;
    PORT
      LAYER met3 ;
        RECT 0.000 387.640 4.000 388.240 ;
    END
  END sw_axi_slave_state[0]
  PIN sw_axi_slave_state[1]
    DIRECTION OUTPUT TRISTATE ;
    USE SIGNAL ;
    ANTENNADIFFAREA 0.795200 ;
    PORT
      LAYER met3 ;
        RECT 492.505 269.320 496.505 269.920 ;
    END
  END sw_axi_slave_state[1]
  OBS
      LAYER li1 ;
        RECT 5.520 10.795 490.820 495.125 ;
      LAYER met1 ;
        RECT 0.070 8.200 494.890 496.700 ;
      LAYER met2 ;
        RECT 0.100 502.945 2.110 506.445 ;
        RECT 2.950 502.945 4.410 506.445 ;
        RECT 5.250 502.945 9.010 506.445 ;
        RECT 9.850 502.945 13.610 506.445 ;
        RECT 14.450 502.945 15.910 506.445 ;
        RECT 16.750 502.945 20.510 506.445 ;
        RECT 21.350 502.945 25.110 506.445 ;
        RECT 25.950 502.945 27.410 506.445 ;
        RECT 28.250 502.945 32.010 506.445 ;
        RECT 32.850 502.945 36.610 506.445 ;
        RECT 37.450 502.945 38.910 506.445 ;
        RECT 39.750 502.945 43.510 506.445 ;
        RECT 44.350 502.945 48.110 506.445 ;
        RECT 48.950 502.945 50.410 506.445 ;
        RECT 51.250 502.945 55.010 506.445 ;
        RECT 55.850 502.945 59.610 506.445 ;
        RECT 60.450 502.945 61.910 506.445 ;
        RECT 62.750 502.945 66.510 506.445 ;
        RECT 67.350 502.945 71.110 506.445 ;
        RECT 71.950 502.945 73.410 506.445 ;
        RECT 74.250 502.945 78.010 506.445 ;
        RECT 78.850 502.945 82.610 506.445 ;
        RECT 83.450 502.945 84.910 506.445 ;
        RECT 85.750 502.945 89.510 506.445 ;
        RECT 90.350 502.945 94.110 506.445 ;
        RECT 94.950 502.945 96.410 506.445 ;
        RECT 97.250 502.945 101.010 506.445 ;
        RECT 101.850 502.945 105.610 506.445 ;
        RECT 106.450 502.945 107.910 506.445 ;
        RECT 108.750 502.945 112.510 506.445 ;
        RECT 113.350 502.945 117.110 506.445 ;
        RECT 117.950 502.945 119.410 506.445 ;
        RECT 120.250 502.945 124.010 506.445 ;
        RECT 124.850 502.945 128.610 506.445 ;
        RECT 129.450 502.945 130.910 506.445 ;
        RECT 131.750 502.945 135.510 506.445 ;
        RECT 136.350 502.945 137.810 506.445 ;
        RECT 138.650 502.945 142.410 506.445 ;
        RECT 143.250 502.945 147.010 506.445 ;
        RECT 147.850 502.945 149.310 506.445 ;
        RECT 150.150 502.945 153.910 506.445 ;
        RECT 154.750 502.945 158.510 506.445 ;
        RECT 159.350 502.945 160.810 506.445 ;
        RECT 161.650 502.945 165.410 506.445 ;
        RECT 166.250 502.945 170.010 506.445 ;
        RECT 170.850 502.945 172.310 506.445 ;
        RECT 173.150 502.945 176.910 506.445 ;
        RECT 177.750 502.945 181.510 506.445 ;
        RECT 182.350 502.945 183.810 506.445 ;
        RECT 184.650 502.945 188.410 506.445 ;
        RECT 189.250 502.945 193.010 506.445 ;
        RECT 193.850 502.945 195.310 506.445 ;
        RECT 196.150 502.945 199.910 506.445 ;
        RECT 200.750 502.945 204.510 506.445 ;
        RECT 205.350 502.945 206.810 506.445 ;
        RECT 207.650 502.945 211.410 506.445 ;
        RECT 212.250 502.945 216.010 506.445 ;
        RECT 216.850 502.945 218.310 506.445 ;
        RECT 219.150 502.945 222.910 506.445 ;
        RECT 223.750 502.945 227.510 506.445 ;
        RECT 228.350 502.945 229.810 506.445 ;
        RECT 230.650 502.945 234.410 506.445 ;
        RECT 235.250 502.945 239.010 506.445 ;
        RECT 239.850 502.945 241.310 506.445 ;
        RECT 242.150 502.945 245.910 506.445 ;
        RECT 246.750 502.945 250.510 506.445 ;
        RECT 251.350 502.945 252.810 506.445 ;
        RECT 253.650 502.945 257.410 506.445 ;
        RECT 258.250 502.945 262.010 506.445 ;
        RECT 262.850 502.945 264.310 506.445 ;
        RECT 265.150 502.945 268.910 506.445 ;
        RECT 269.750 502.945 273.510 506.445 ;
        RECT 274.350 502.945 275.810 506.445 ;
        RECT 276.650 502.945 280.410 506.445 ;
        RECT 281.250 502.945 282.710 506.445 ;
        RECT 283.550 502.945 287.310 506.445 ;
        RECT 288.150 502.945 291.910 506.445 ;
        RECT 292.750 502.945 294.210 506.445 ;
        RECT 295.050 502.945 298.810 506.445 ;
        RECT 299.650 502.945 303.410 506.445 ;
        RECT 304.250 502.945 305.710 506.445 ;
        RECT 306.550 502.945 310.310 506.445 ;
        RECT 311.150 502.945 314.910 506.445 ;
        RECT 315.750 502.945 317.210 506.445 ;
        RECT 318.050 502.945 321.810 506.445 ;
        RECT 322.650 502.945 326.410 506.445 ;
        RECT 327.250 502.945 328.710 506.445 ;
        RECT 329.550 502.945 333.310 506.445 ;
        RECT 334.150 502.945 337.910 506.445 ;
        RECT 338.750 502.945 340.210 506.445 ;
        RECT 341.050 502.945 344.810 506.445 ;
        RECT 345.650 502.945 349.410 506.445 ;
        RECT 350.250 502.945 351.710 506.445 ;
        RECT 352.550 502.945 356.310 506.445 ;
        RECT 357.150 502.945 360.910 506.445 ;
        RECT 361.750 502.945 363.210 506.445 ;
        RECT 364.050 502.945 367.810 506.445 ;
        RECT 368.650 502.945 372.410 506.445 ;
        RECT 373.250 502.945 374.710 506.445 ;
        RECT 375.550 502.945 379.310 506.445 ;
        RECT 380.150 502.945 383.910 506.445 ;
        RECT 384.750 502.945 386.210 506.445 ;
        RECT 387.050 502.945 390.810 506.445 ;
        RECT 391.650 502.945 395.410 506.445 ;
        RECT 396.250 502.945 397.710 506.445 ;
        RECT 398.550 502.945 402.310 506.445 ;
        RECT 403.150 502.945 406.910 506.445 ;
        RECT 407.750 502.945 409.210 506.445 ;
        RECT 410.050 502.945 413.810 506.445 ;
        RECT 414.650 502.945 418.410 506.445 ;
        RECT 419.250 502.945 420.710 506.445 ;
        RECT 421.550 502.945 425.310 506.445 ;
        RECT 426.150 502.945 427.610 506.445 ;
        RECT 428.450 502.945 432.210 506.445 ;
        RECT 433.050 502.945 436.810 506.445 ;
        RECT 437.650 502.945 439.110 506.445 ;
        RECT 439.950 502.945 443.710 506.445 ;
        RECT 444.550 502.945 448.310 506.445 ;
        RECT 449.150 502.945 450.610 506.445 ;
        RECT 451.450 502.945 455.210 506.445 ;
        RECT 456.050 502.945 459.810 506.445 ;
        RECT 460.650 502.945 462.110 506.445 ;
        RECT 462.950 502.945 466.710 506.445 ;
        RECT 467.550 502.945 471.310 506.445 ;
        RECT 472.150 502.945 473.610 506.445 ;
        RECT 474.450 502.945 478.210 506.445 ;
        RECT 479.050 502.945 482.810 506.445 ;
        RECT 483.650 502.945 485.110 506.445 ;
        RECT 485.950 502.945 489.710 506.445 ;
        RECT 490.550 502.945 494.310 506.445 ;
        RECT 0.100 4.280 494.860 502.945 ;
        RECT 0.650 2.195 2.110 4.280 ;
        RECT 2.950 2.195 6.710 4.280 ;
        RECT 7.550 2.195 9.010 4.280 ;
        RECT 9.850 2.195 13.610 4.280 ;
        RECT 14.450 2.195 18.210 4.280 ;
        RECT 19.050 2.195 20.510 4.280 ;
        RECT 21.350 2.195 25.110 4.280 ;
        RECT 25.950 2.195 29.710 4.280 ;
        RECT 30.550 2.195 32.010 4.280 ;
        RECT 32.850 2.195 36.610 4.280 ;
        RECT 37.450 2.195 41.210 4.280 ;
        RECT 42.050 2.195 43.510 4.280 ;
        RECT 44.350 2.195 48.110 4.280 ;
        RECT 48.950 2.195 52.710 4.280 ;
        RECT 53.550 2.195 55.010 4.280 ;
        RECT 55.850 2.195 59.610 4.280 ;
        RECT 60.450 2.195 64.210 4.280 ;
        RECT 65.050 2.195 66.510 4.280 ;
        RECT 67.350 2.195 71.110 4.280 ;
        RECT 71.950 2.195 75.710 4.280 ;
        RECT 76.550 2.195 78.010 4.280 ;
        RECT 78.850 2.195 82.610 4.280 ;
        RECT 83.450 2.195 87.210 4.280 ;
        RECT 88.050 2.195 89.510 4.280 ;
        RECT 90.350 2.195 94.110 4.280 ;
        RECT 94.950 2.195 98.710 4.280 ;
        RECT 99.550 2.195 101.010 4.280 ;
        RECT 101.850 2.195 105.610 4.280 ;
        RECT 106.450 2.195 110.210 4.280 ;
        RECT 111.050 2.195 112.510 4.280 ;
        RECT 113.350 2.195 117.110 4.280 ;
        RECT 117.950 2.195 121.710 4.280 ;
        RECT 122.550 2.195 124.010 4.280 ;
        RECT 124.850 2.195 128.610 4.280 ;
        RECT 129.450 2.195 133.210 4.280 ;
        RECT 134.050 2.195 135.510 4.280 ;
        RECT 136.350 2.195 140.110 4.280 ;
        RECT 140.950 2.195 142.410 4.280 ;
        RECT 143.250 2.195 147.010 4.280 ;
        RECT 147.850 2.195 151.610 4.280 ;
        RECT 152.450 2.195 153.910 4.280 ;
        RECT 154.750 2.195 158.510 4.280 ;
        RECT 159.350 2.195 163.110 4.280 ;
        RECT 163.950 2.195 165.410 4.280 ;
        RECT 166.250 2.195 170.010 4.280 ;
        RECT 170.850 2.195 174.610 4.280 ;
        RECT 175.450 2.195 176.910 4.280 ;
        RECT 177.750 2.195 181.510 4.280 ;
        RECT 182.350 2.195 186.110 4.280 ;
        RECT 186.950 2.195 188.410 4.280 ;
        RECT 189.250 2.195 193.010 4.280 ;
        RECT 193.850 2.195 197.610 4.280 ;
        RECT 198.450 2.195 199.910 4.280 ;
        RECT 200.750 2.195 204.510 4.280 ;
        RECT 205.350 2.195 209.110 4.280 ;
        RECT 209.950 2.195 211.410 4.280 ;
        RECT 212.250 2.195 216.010 4.280 ;
        RECT 216.850 2.195 220.610 4.280 ;
        RECT 221.450 2.195 222.910 4.280 ;
        RECT 223.750 2.195 227.510 4.280 ;
        RECT 228.350 2.195 232.110 4.280 ;
        RECT 232.950 2.195 234.410 4.280 ;
        RECT 235.250 2.195 239.010 4.280 ;
        RECT 239.850 2.195 243.610 4.280 ;
        RECT 244.450 2.195 245.910 4.280 ;
        RECT 246.750 2.195 250.510 4.280 ;
        RECT 251.350 2.195 255.110 4.280 ;
        RECT 255.950 2.195 257.410 4.280 ;
        RECT 258.250 2.195 262.010 4.280 ;
        RECT 262.850 2.195 266.610 4.280 ;
        RECT 267.450 2.195 268.910 4.280 ;
        RECT 269.750 2.195 273.510 4.280 ;
        RECT 274.350 2.195 278.110 4.280 ;
        RECT 278.950 2.195 280.410 4.280 ;
        RECT 281.250 2.195 285.010 4.280 ;
        RECT 285.850 2.195 287.310 4.280 ;
        RECT 288.150 2.195 291.910 4.280 ;
        RECT 292.750 2.195 296.510 4.280 ;
        RECT 297.350 2.195 298.810 4.280 ;
        RECT 299.650 2.195 303.410 4.280 ;
        RECT 304.250 2.195 308.010 4.280 ;
        RECT 308.850 2.195 310.310 4.280 ;
        RECT 311.150 2.195 314.910 4.280 ;
        RECT 315.750 2.195 319.510 4.280 ;
        RECT 320.350 2.195 321.810 4.280 ;
        RECT 322.650 2.195 326.410 4.280 ;
        RECT 327.250 2.195 331.010 4.280 ;
        RECT 331.850 2.195 333.310 4.280 ;
        RECT 334.150 2.195 337.910 4.280 ;
        RECT 338.750 2.195 342.510 4.280 ;
        RECT 343.350 2.195 344.810 4.280 ;
        RECT 345.650 2.195 349.410 4.280 ;
        RECT 350.250 2.195 354.010 4.280 ;
        RECT 354.850 2.195 356.310 4.280 ;
        RECT 357.150 2.195 360.910 4.280 ;
        RECT 361.750 2.195 365.510 4.280 ;
        RECT 366.350 2.195 367.810 4.280 ;
        RECT 368.650 2.195 372.410 4.280 ;
        RECT 373.250 2.195 377.010 4.280 ;
        RECT 377.850 2.195 379.310 4.280 ;
        RECT 380.150 2.195 383.910 4.280 ;
        RECT 384.750 2.195 388.510 4.280 ;
        RECT 389.350 2.195 390.810 4.280 ;
        RECT 391.650 2.195 395.410 4.280 ;
        RECT 396.250 2.195 400.010 4.280 ;
        RECT 400.850 2.195 402.310 4.280 ;
        RECT 403.150 2.195 406.910 4.280 ;
        RECT 407.750 2.195 411.510 4.280 ;
        RECT 412.350 2.195 413.810 4.280 ;
        RECT 414.650 2.195 418.410 4.280 ;
        RECT 419.250 2.195 423.010 4.280 ;
        RECT 423.850 2.195 425.310 4.280 ;
        RECT 426.150 2.195 429.910 4.280 ;
        RECT 430.750 2.195 432.210 4.280 ;
        RECT 433.050 2.195 436.810 4.280 ;
        RECT 437.650 2.195 441.410 4.280 ;
        RECT 442.250 2.195 443.710 4.280 ;
        RECT 444.550 2.195 448.310 4.280 ;
        RECT 449.150 2.195 452.910 4.280 ;
        RECT 453.750 2.195 455.210 4.280 ;
        RECT 456.050 2.195 459.810 4.280 ;
        RECT 460.650 2.195 464.410 4.280 ;
        RECT 465.250 2.195 466.710 4.280 ;
        RECT 467.550 2.195 471.310 4.280 ;
        RECT 472.150 2.195 475.910 4.280 ;
        RECT 476.750 2.195 478.210 4.280 ;
        RECT 479.050 2.195 482.810 4.280 ;
        RECT 483.650 2.195 487.410 4.280 ;
        RECT 488.250 2.195 489.710 4.280 ;
        RECT 490.550 2.195 494.310 4.280 ;
      LAYER met3 ;
        RECT 4.400 505.560 492.105 506.425 ;
        RECT 3.990 504.920 492.505 505.560 ;
        RECT 4.400 503.520 492.505 504.920 ;
        RECT 3.990 502.880 492.505 503.520 ;
        RECT 3.990 501.480 492.105 502.880 ;
        RECT 3.990 500.840 492.505 501.480 ;
        RECT 4.400 499.440 492.505 500.840 ;
        RECT 3.990 498.800 492.505 499.440 ;
        RECT 3.990 497.400 492.105 498.800 ;
        RECT 3.990 496.760 492.505 497.400 ;
        RECT 4.400 495.360 492.105 496.760 ;
        RECT 3.990 494.720 492.505 495.360 ;
        RECT 4.400 493.320 492.505 494.720 ;
        RECT 3.990 492.680 492.505 493.320 ;
        RECT 3.990 491.280 492.105 492.680 ;
        RECT 3.990 490.640 492.505 491.280 ;
        RECT 4.400 489.240 492.505 490.640 ;
        RECT 3.990 488.600 492.505 489.240 ;
        RECT 3.990 487.200 492.105 488.600 ;
        RECT 3.990 486.560 492.505 487.200 ;
        RECT 4.400 485.160 492.105 486.560 ;
        RECT 3.990 484.520 492.505 485.160 ;
        RECT 4.400 483.120 492.505 484.520 ;
        RECT 3.990 482.480 492.505 483.120 ;
        RECT 3.990 481.080 492.105 482.480 ;
        RECT 3.990 480.440 492.505 481.080 ;
        RECT 4.400 479.040 492.505 480.440 ;
        RECT 3.990 478.400 492.505 479.040 ;
        RECT 3.990 477.000 492.105 478.400 ;
        RECT 3.990 476.360 492.505 477.000 ;
        RECT 4.400 474.960 492.105 476.360 ;
        RECT 3.990 474.320 492.505 474.960 ;
        RECT 4.400 472.920 492.505 474.320 ;
        RECT 3.990 472.280 492.505 472.920 ;
        RECT 3.990 470.880 492.105 472.280 ;
        RECT 3.990 470.240 492.505 470.880 ;
        RECT 4.400 468.840 492.505 470.240 ;
        RECT 3.990 468.200 492.505 468.840 ;
        RECT 3.990 466.800 492.105 468.200 ;
        RECT 3.990 466.160 492.505 466.800 ;
        RECT 4.400 464.760 492.105 466.160 ;
        RECT 3.990 464.120 492.505 464.760 ;
        RECT 4.400 462.720 492.505 464.120 ;
        RECT 3.990 462.080 492.505 462.720 ;
        RECT 3.990 460.680 492.105 462.080 ;
        RECT 3.990 460.040 492.505 460.680 ;
        RECT 4.400 458.640 492.505 460.040 ;
        RECT 3.990 458.000 492.505 458.640 ;
        RECT 3.990 456.600 492.105 458.000 ;
        RECT 3.990 455.960 492.505 456.600 ;
        RECT 4.400 454.560 492.105 455.960 ;
        RECT 3.990 453.920 492.505 454.560 ;
        RECT 4.400 452.520 492.505 453.920 ;
        RECT 3.990 451.880 492.505 452.520 ;
        RECT 3.990 450.480 492.105 451.880 ;
        RECT 3.990 449.840 492.505 450.480 ;
        RECT 4.400 448.440 492.505 449.840 ;
        RECT 3.990 447.800 492.505 448.440 ;
        RECT 3.990 446.400 492.105 447.800 ;
        RECT 3.990 445.760 492.505 446.400 ;
        RECT 4.400 444.360 492.105 445.760 ;
        RECT 3.990 443.720 492.505 444.360 ;
        RECT 4.400 442.320 492.505 443.720 ;
        RECT 3.990 441.680 492.505 442.320 ;
        RECT 3.990 440.280 492.105 441.680 ;
        RECT 3.990 439.640 492.505 440.280 ;
        RECT 4.400 438.240 492.105 439.640 ;
        RECT 3.990 435.560 492.505 438.240 ;
        RECT 4.400 434.160 492.105 435.560 ;
        RECT 3.990 433.520 492.505 434.160 ;
        RECT 4.400 432.120 492.505 433.520 ;
        RECT 3.990 431.480 492.505 432.120 ;
        RECT 3.990 430.080 492.105 431.480 ;
        RECT 3.990 429.440 492.505 430.080 ;
        RECT 4.400 428.040 492.105 429.440 ;
        RECT 3.990 425.360 492.505 428.040 ;
        RECT 4.400 423.960 492.105 425.360 ;
        RECT 3.990 423.320 492.505 423.960 ;
        RECT 4.400 421.920 492.505 423.320 ;
        RECT 3.990 421.280 492.505 421.920 ;
        RECT 3.990 419.880 492.105 421.280 ;
        RECT 3.990 419.240 492.505 419.880 ;
        RECT 4.400 417.840 492.105 419.240 ;
        RECT 3.990 415.160 492.505 417.840 ;
        RECT 4.400 413.760 492.105 415.160 ;
        RECT 3.990 413.120 492.505 413.760 ;
        RECT 4.400 411.720 492.505 413.120 ;
        RECT 3.990 411.080 492.505 411.720 ;
        RECT 3.990 409.680 492.105 411.080 ;
        RECT 3.990 409.040 492.505 409.680 ;
        RECT 4.400 407.640 492.105 409.040 ;
        RECT 3.990 404.960 492.505 407.640 ;
        RECT 4.400 403.560 492.105 404.960 ;
        RECT 3.990 402.920 492.505 403.560 ;
        RECT 4.400 401.520 492.505 402.920 ;
        RECT 3.990 400.880 492.505 401.520 ;
        RECT 3.990 399.480 492.105 400.880 ;
        RECT 3.990 398.840 492.505 399.480 ;
        RECT 4.400 397.440 492.105 398.840 ;
        RECT 3.990 394.760 492.505 397.440 ;
        RECT 4.400 393.360 492.105 394.760 ;
        RECT 3.990 392.720 492.505 393.360 ;
        RECT 4.400 391.320 492.505 392.720 ;
        RECT 3.990 390.680 492.505 391.320 ;
        RECT 3.990 389.280 492.105 390.680 ;
        RECT 3.990 388.640 492.505 389.280 ;
        RECT 4.400 387.240 492.105 388.640 ;
        RECT 3.990 384.560 492.505 387.240 ;
        RECT 4.400 383.160 492.105 384.560 ;
        RECT 3.990 382.520 492.505 383.160 ;
        RECT 4.400 381.120 492.505 382.520 ;
        RECT 3.990 380.480 492.505 381.120 ;
        RECT 3.990 379.080 492.105 380.480 ;
        RECT 3.990 378.440 492.505 379.080 ;
        RECT 4.400 377.040 492.105 378.440 ;
        RECT 3.990 376.400 492.505 377.040 ;
        RECT 4.400 375.000 492.505 376.400 ;
        RECT 3.990 374.360 492.505 375.000 ;
        RECT 3.990 372.960 492.105 374.360 ;
        RECT 3.990 372.320 492.505 372.960 ;
        RECT 4.400 370.920 492.505 372.320 ;
        RECT 3.990 370.280 492.505 370.920 ;
        RECT 3.990 368.880 492.105 370.280 ;
        RECT 3.990 368.240 492.505 368.880 ;
        RECT 4.400 366.840 492.105 368.240 ;
        RECT 3.990 366.200 492.505 366.840 ;
        RECT 4.400 364.800 492.505 366.200 ;
        RECT 3.990 364.160 492.505 364.800 ;
        RECT 3.990 362.760 492.105 364.160 ;
        RECT 3.990 362.120 492.505 362.760 ;
        RECT 4.400 360.720 492.505 362.120 ;
        RECT 3.990 360.080 492.505 360.720 ;
        RECT 3.990 358.680 492.105 360.080 ;
        RECT 3.990 358.040 492.505 358.680 ;
        RECT 4.400 356.640 492.105 358.040 ;
        RECT 3.990 356.000 492.505 356.640 ;
        RECT 4.400 354.600 492.505 356.000 ;
        RECT 3.990 353.960 492.505 354.600 ;
        RECT 3.990 352.560 492.105 353.960 ;
        RECT 3.990 351.920 492.505 352.560 ;
        RECT 4.400 350.520 492.505 351.920 ;
        RECT 3.990 349.880 492.505 350.520 ;
        RECT 3.990 348.480 492.105 349.880 ;
        RECT 3.990 347.840 492.505 348.480 ;
        RECT 4.400 346.440 492.105 347.840 ;
        RECT 3.990 345.800 492.505 346.440 ;
        RECT 4.400 344.400 492.505 345.800 ;
        RECT 3.990 343.760 492.505 344.400 ;
        RECT 3.990 342.360 492.105 343.760 ;
        RECT 3.990 341.720 492.505 342.360 ;
        RECT 4.400 340.320 492.505 341.720 ;
        RECT 3.990 339.680 492.505 340.320 ;
        RECT 3.990 338.280 492.105 339.680 ;
        RECT 3.990 337.640 492.505 338.280 ;
        RECT 4.400 336.240 492.105 337.640 ;
        RECT 3.990 335.600 492.505 336.240 ;
        RECT 4.400 334.200 492.505 335.600 ;
        RECT 3.990 333.560 492.505 334.200 ;
        RECT 3.990 332.160 492.105 333.560 ;
        RECT 3.990 331.520 492.505 332.160 ;
        RECT 4.400 330.120 492.505 331.520 ;
        RECT 3.990 329.480 492.505 330.120 ;
        RECT 3.990 328.080 492.105 329.480 ;
        RECT 3.990 327.440 492.505 328.080 ;
        RECT 4.400 326.040 492.105 327.440 ;
        RECT 3.990 325.400 492.505 326.040 ;
        RECT 4.400 324.000 492.505 325.400 ;
        RECT 3.990 323.360 492.505 324.000 ;
        RECT 3.990 321.960 492.105 323.360 ;
        RECT 3.990 321.320 492.505 321.960 ;
        RECT 4.400 319.920 492.505 321.320 ;
        RECT 3.990 319.280 492.505 319.920 ;
        RECT 3.990 317.880 492.105 319.280 ;
        RECT 3.990 317.240 492.505 317.880 ;
        RECT 4.400 315.840 492.105 317.240 ;
        RECT 3.990 315.200 492.505 315.840 ;
        RECT 4.400 313.800 492.505 315.200 ;
        RECT 3.990 313.160 492.505 313.800 ;
        RECT 3.990 311.760 492.105 313.160 ;
        RECT 3.990 311.120 492.505 311.760 ;
        RECT 4.400 309.720 492.105 311.120 ;
        RECT 3.990 307.040 492.505 309.720 ;
        RECT 4.400 305.640 492.105 307.040 ;
        RECT 3.990 305.000 492.505 305.640 ;
        RECT 4.400 303.600 492.505 305.000 ;
        RECT 3.990 302.960 492.505 303.600 ;
        RECT 3.990 301.560 492.105 302.960 ;
        RECT 3.990 300.920 492.505 301.560 ;
        RECT 4.400 299.520 492.105 300.920 ;
        RECT 3.990 296.840 492.505 299.520 ;
        RECT 4.400 295.440 492.105 296.840 ;
        RECT 3.990 294.800 492.505 295.440 ;
        RECT 4.400 293.400 492.505 294.800 ;
        RECT 3.990 292.760 492.505 293.400 ;
        RECT 3.990 291.360 492.105 292.760 ;
        RECT 3.990 290.720 492.505 291.360 ;
        RECT 4.400 289.320 492.105 290.720 ;
        RECT 3.990 286.640 492.505 289.320 ;
        RECT 4.400 285.240 492.105 286.640 ;
        RECT 3.990 284.600 492.505 285.240 ;
        RECT 4.400 283.200 492.505 284.600 ;
        RECT 3.990 282.560 492.505 283.200 ;
        RECT 3.990 281.160 492.105 282.560 ;
        RECT 3.990 280.520 492.505 281.160 ;
        RECT 4.400 279.120 492.105 280.520 ;
        RECT 3.990 276.440 492.505 279.120 ;
        RECT 4.400 275.040 492.105 276.440 ;
        RECT 3.990 274.400 492.505 275.040 ;
        RECT 4.400 273.000 492.505 274.400 ;
        RECT 3.990 272.360 492.505 273.000 ;
        RECT 3.990 270.960 492.105 272.360 ;
        RECT 3.990 270.320 492.505 270.960 ;
        RECT 4.400 268.920 492.105 270.320 ;
        RECT 3.990 266.240 492.505 268.920 ;
        RECT 4.400 264.840 492.105 266.240 ;
        RECT 3.990 264.200 492.505 264.840 ;
        RECT 4.400 262.800 492.505 264.200 ;
        RECT 3.990 262.160 492.505 262.800 ;
        RECT 3.990 260.760 492.105 262.160 ;
        RECT 3.990 260.120 492.505 260.760 ;
        RECT 4.400 258.720 492.105 260.120 ;
        RECT 3.990 256.040 492.505 258.720 ;
        RECT 4.400 254.640 492.105 256.040 ;
        RECT 3.990 254.000 492.505 254.640 ;
        RECT 4.400 252.600 492.505 254.000 ;
        RECT 3.990 251.960 492.505 252.600 ;
        RECT 3.990 250.560 492.105 251.960 ;
        RECT 3.990 249.920 492.505 250.560 ;
        RECT 4.400 248.520 492.105 249.920 ;
        RECT 3.990 247.880 492.505 248.520 ;
        RECT 4.400 246.480 492.505 247.880 ;
        RECT 3.990 245.840 492.505 246.480 ;
        RECT 3.990 244.440 492.105 245.840 ;
        RECT 3.990 243.800 492.505 244.440 ;
        RECT 4.400 242.400 492.505 243.800 ;
        RECT 3.990 241.760 492.505 242.400 ;
        RECT 3.990 240.360 492.105 241.760 ;
        RECT 3.990 239.720 492.505 240.360 ;
        RECT 4.400 238.320 492.105 239.720 ;
        RECT 3.990 237.680 492.505 238.320 ;
        RECT 4.400 236.280 492.505 237.680 ;
        RECT 3.990 235.640 492.505 236.280 ;
        RECT 3.990 234.240 492.105 235.640 ;
        RECT 3.990 233.600 492.505 234.240 ;
        RECT 4.400 232.200 492.505 233.600 ;
        RECT 3.990 231.560 492.505 232.200 ;
        RECT 3.990 230.160 492.105 231.560 ;
        RECT 3.990 229.520 492.505 230.160 ;
        RECT 4.400 228.120 492.105 229.520 ;
        RECT 3.990 227.480 492.505 228.120 ;
        RECT 4.400 226.080 492.505 227.480 ;
        RECT 3.990 225.440 492.505 226.080 ;
        RECT 3.990 224.040 492.105 225.440 ;
        RECT 3.990 223.400 492.505 224.040 ;
        RECT 4.400 222.000 492.505 223.400 ;
        RECT 3.990 221.360 492.505 222.000 ;
        RECT 3.990 219.960 492.105 221.360 ;
        RECT 3.990 219.320 492.505 219.960 ;
        RECT 4.400 217.920 492.105 219.320 ;
        RECT 3.990 217.280 492.505 217.920 ;
        RECT 4.400 215.880 492.505 217.280 ;
        RECT 3.990 215.240 492.505 215.880 ;
        RECT 3.990 213.840 492.105 215.240 ;
        RECT 3.990 213.200 492.505 213.840 ;
        RECT 4.400 211.800 492.505 213.200 ;
        RECT 3.990 211.160 492.505 211.800 ;
        RECT 3.990 209.760 492.105 211.160 ;
        RECT 3.990 209.120 492.505 209.760 ;
        RECT 4.400 207.720 492.105 209.120 ;
        RECT 3.990 207.080 492.505 207.720 ;
        RECT 4.400 205.680 492.505 207.080 ;
        RECT 3.990 205.040 492.505 205.680 ;
        RECT 3.990 203.640 492.105 205.040 ;
        RECT 3.990 203.000 492.505 203.640 ;
        RECT 4.400 201.600 492.505 203.000 ;
        RECT 3.990 200.960 492.505 201.600 ;
        RECT 3.990 199.560 492.105 200.960 ;
        RECT 3.990 198.920 492.505 199.560 ;
        RECT 4.400 197.520 492.105 198.920 ;
        RECT 3.990 196.880 492.505 197.520 ;
        RECT 4.400 195.480 492.505 196.880 ;
        RECT 3.990 194.840 492.505 195.480 ;
        RECT 3.990 193.440 492.105 194.840 ;
        RECT 3.990 192.800 492.505 193.440 ;
        RECT 4.400 191.400 492.105 192.800 ;
        RECT 3.990 188.720 492.505 191.400 ;
        RECT 4.400 187.320 492.105 188.720 ;
        RECT 3.990 186.680 492.505 187.320 ;
        RECT 4.400 185.280 492.505 186.680 ;
        RECT 3.990 184.640 492.505 185.280 ;
        RECT 3.990 183.240 492.105 184.640 ;
        RECT 3.990 182.600 492.505 183.240 ;
        RECT 4.400 181.200 492.105 182.600 ;
        RECT 3.990 178.520 492.505 181.200 ;
        RECT 4.400 177.120 492.105 178.520 ;
        RECT 3.990 176.480 492.505 177.120 ;
        RECT 4.400 175.080 492.505 176.480 ;
        RECT 3.990 174.440 492.505 175.080 ;
        RECT 3.990 173.040 492.105 174.440 ;
        RECT 3.990 172.400 492.505 173.040 ;
        RECT 4.400 171.000 492.105 172.400 ;
        RECT 3.990 168.320 492.505 171.000 ;
        RECT 4.400 166.920 492.105 168.320 ;
        RECT 3.990 166.280 492.505 166.920 ;
        RECT 4.400 164.880 492.505 166.280 ;
        RECT 3.990 164.240 492.505 164.880 ;
        RECT 3.990 162.840 492.105 164.240 ;
        RECT 3.990 162.200 492.505 162.840 ;
        RECT 4.400 160.800 492.105 162.200 ;
        RECT 3.990 158.120 492.505 160.800 ;
        RECT 4.400 156.720 492.105 158.120 ;
        RECT 3.990 156.080 492.505 156.720 ;
        RECT 4.400 154.680 492.505 156.080 ;
        RECT 3.990 154.040 492.505 154.680 ;
        RECT 3.990 152.640 492.105 154.040 ;
        RECT 3.990 152.000 492.505 152.640 ;
        RECT 4.400 150.600 492.105 152.000 ;
        RECT 3.990 147.920 492.505 150.600 ;
        RECT 4.400 146.520 492.105 147.920 ;
        RECT 3.990 145.880 492.505 146.520 ;
        RECT 4.400 144.480 492.505 145.880 ;
        RECT 3.990 143.840 492.505 144.480 ;
        RECT 3.990 142.440 492.105 143.840 ;
        RECT 3.990 141.800 492.505 142.440 ;
        RECT 4.400 140.400 492.105 141.800 ;
        RECT 3.990 137.720 492.505 140.400 ;
        RECT 4.400 136.320 492.105 137.720 ;
        RECT 3.990 135.680 492.505 136.320 ;
        RECT 4.400 134.280 492.505 135.680 ;
        RECT 3.990 133.640 492.505 134.280 ;
        RECT 3.990 132.240 492.105 133.640 ;
        RECT 3.990 131.600 492.505 132.240 ;
        RECT 4.400 130.200 492.105 131.600 ;
        RECT 3.990 127.520 492.505 130.200 ;
        RECT 4.400 126.120 492.105 127.520 ;
        RECT 3.990 125.480 492.505 126.120 ;
        RECT 4.400 124.080 492.505 125.480 ;
        RECT 3.990 123.440 492.505 124.080 ;
        RECT 3.990 122.040 492.105 123.440 ;
        RECT 3.990 121.400 492.505 122.040 ;
        RECT 4.400 120.000 492.105 121.400 ;
        RECT 3.990 119.360 492.505 120.000 ;
        RECT 4.400 117.960 492.505 119.360 ;
        RECT 3.990 117.320 492.505 117.960 ;
        RECT 3.990 115.920 492.105 117.320 ;
        RECT 3.990 115.280 492.505 115.920 ;
        RECT 4.400 113.880 492.505 115.280 ;
        RECT 3.990 113.240 492.505 113.880 ;
        RECT 3.990 111.840 492.105 113.240 ;
        RECT 3.990 111.200 492.505 111.840 ;
        RECT 4.400 109.800 492.105 111.200 ;
        RECT 3.990 109.160 492.505 109.800 ;
        RECT 4.400 107.760 492.505 109.160 ;
        RECT 3.990 107.120 492.505 107.760 ;
        RECT 3.990 105.720 492.105 107.120 ;
        RECT 3.990 105.080 492.505 105.720 ;
        RECT 4.400 103.680 492.505 105.080 ;
        RECT 3.990 103.040 492.505 103.680 ;
        RECT 3.990 101.640 492.105 103.040 ;
        RECT 3.990 101.000 492.505 101.640 ;
        RECT 4.400 99.600 492.105 101.000 ;
        RECT 3.990 98.960 492.505 99.600 ;
        RECT 4.400 97.560 492.505 98.960 ;
        RECT 3.990 96.920 492.505 97.560 ;
        RECT 3.990 95.520 492.105 96.920 ;
        RECT 3.990 94.880 492.505 95.520 ;
        RECT 4.400 93.480 492.505 94.880 ;
        RECT 3.990 92.840 492.505 93.480 ;
        RECT 3.990 91.440 492.105 92.840 ;
        RECT 3.990 90.800 492.505 91.440 ;
        RECT 4.400 89.400 492.105 90.800 ;
        RECT 3.990 88.760 492.505 89.400 ;
        RECT 4.400 87.360 492.505 88.760 ;
        RECT 3.990 86.720 492.505 87.360 ;
        RECT 3.990 85.320 492.105 86.720 ;
        RECT 3.990 84.680 492.505 85.320 ;
        RECT 4.400 83.280 492.505 84.680 ;
        RECT 3.990 82.640 492.505 83.280 ;
        RECT 3.990 81.240 492.105 82.640 ;
        RECT 3.990 80.600 492.505 81.240 ;
        RECT 4.400 79.200 492.105 80.600 ;
        RECT 3.990 78.560 492.505 79.200 ;
        RECT 4.400 77.160 492.505 78.560 ;
        RECT 3.990 76.520 492.505 77.160 ;
        RECT 3.990 75.120 492.105 76.520 ;
        RECT 3.990 74.480 492.505 75.120 ;
        RECT 4.400 73.080 492.505 74.480 ;
        RECT 3.990 72.440 492.505 73.080 ;
        RECT 3.990 71.040 492.105 72.440 ;
        RECT 3.990 70.400 492.505 71.040 ;
        RECT 4.400 69.000 492.105 70.400 ;
        RECT 3.990 68.360 492.505 69.000 ;
        RECT 4.400 66.960 492.505 68.360 ;
        RECT 3.990 66.320 492.505 66.960 ;
        RECT 3.990 64.920 492.105 66.320 ;
        RECT 3.990 64.280 492.505 64.920 ;
        RECT 4.400 62.880 492.105 64.280 ;
        RECT 3.990 60.200 492.505 62.880 ;
        RECT 4.400 58.800 492.105 60.200 ;
        RECT 3.990 58.160 492.505 58.800 ;
        RECT 4.400 56.760 492.505 58.160 ;
        RECT 3.990 56.120 492.505 56.760 ;
        RECT 3.990 54.720 492.105 56.120 ;
        RECT 3.990 54.080 492.505 54.720 ;
        RECT 4.400 52.680 492.105 54.080 ;
        RECT 3.990 50.000 492.505 52.680 ;
        RECT 4.400 48.600 492.105 50.000 ;
        RECT 3.990 47.960 492.505 48.600 ;
        RECT 4.400 46.560 492.505 47.960 ;
        RECT 3.990 45.920 492.505 46.560 ;
        RECT 3.990 44.520 492.105 45.920 ;
        RECT 3.990 43.880 492.505 44.520 ;
        RECT 4.400 42.480 492.105 43.880 ;
        RECT 3.990 39.800 492.505 42.480 ;
        RECT 4.400 38.400 492.105 39.800 ;
        RECT 3.990 37.760 492.505 38.400 ;
        RECT 4.400 36.360 492.505 37.760 ;
        RECT 3.990 35.720 492.505 36.360 ;
        RECT 3.990 34.320 492.105 35.720 ;
        RECT 3.990 33.680 492.505 34.320 ;
        RECT 4.400 32.280 492.105 33.680 ;
        RECT 3.990 29.600 492.505 32.280 ;
        RECT 4.400 28.200 492.105 29.600 ;
        RECT 3.990 27.560 492.505 28.200 ;
        RECT 4.400 26.160 492.505 27.560 ;
        RECT 3.990 25.520 492.505 26.160 ;
        RECT 3.990 24.120 492.105 25.520 ;
        RECT 3.990 23.480 492.505 24.120 ;
        RECT 4.400 22.080 492.105 23.480 ;
        RECT 3.990 19.400 492.505 22.080 ;
        RECT 4.400 18.000 492.105 19.400 ;
        RECT 3.990 17.360 492.505 18.000 ;
        RECT 4.400 15.960 492.505 17.360 ;
        RECT 3.990 15.320 492.505 15.960 ;
        RECT 3.990 13.920 492.105 15.320 ;
        RECT 3.990 13.280 492.505 13.920 ;
        RECT 4.400 11.880 492.105 13.280 ;
        RECT 3.990 9.200 492.505 11.880 ;
        RECT 4.400 7.800 492.105 9.200 ;
        RECT 3.990 7.160 492.505 7.800 ;
        RECT 4.400 5.760 492.505 7.160 ;
        RECT 3.990 5.120 492.505 5.760 ;
        RECT 3.990 3.720 492.105 5.120 ;
        RECT 3.990 3.080 492.505 3.720 ;
        RECT 4.400 2.215 492.105 3.080 ;
      LAYER met4 ;
        RECT 8.575 10.240 20.640 493.505 ;
        RECT 23.040 10.240 23.940 493.505 ;
        RECT 26.340 10.240 174.240 493.505 ;
        RECT 176.640 10.240 177.540 493.505 ;
        RECT 179.940 10.240 327.840 493.505 ;
        RECT 330.240 10.240 331.140 493.505 ;
        RECT 333.540 10.240 476.265 493.505 ;
        RECT 8.575 9.695 476.265 10.240 ;
  END
END Top_module
END LIBRARY

